VERSION 5.7 ;
BUSBITCHARS "[]" ;
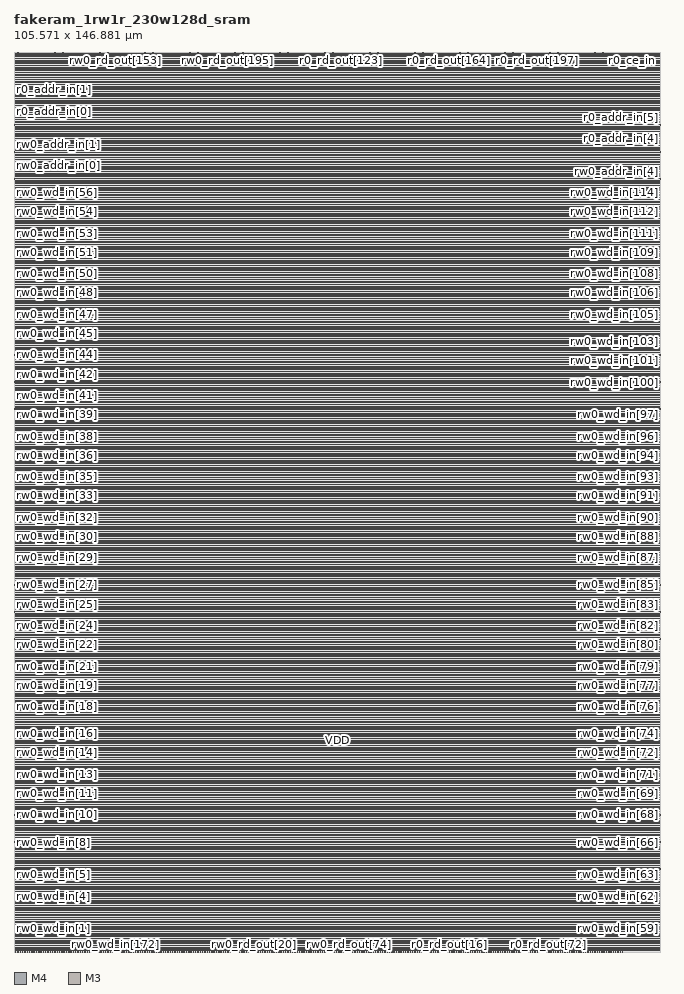
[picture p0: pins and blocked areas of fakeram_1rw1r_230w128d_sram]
MACRO fakeram_1rw1r_230w128d_sram
  FOREIGN fakeram_1rw1r_230w128d_sram 0 0 ;
  SYMMETRY X Y R90 ;
  SIZE 105.571 BY 146.881 ;
  CLASS BLOCK ;
  PIN rw0_wd_in[0]
    DIRECTION INPUT ;
    USE SIGNAL ;
    SHAPE ABUTMENT ;
    PORT
      LAYER M4 ;
      RECT 0.000 0.276 0.072 0.300 ;
    END
  END rw0_wd_in[0]
  PIN rw0_wd_in[1]
    DIRECTION INPUT ;
    USE SIGNAL ;
    SHAPE ABUTMENT ;
    PORT
      LAYER M4 ;
      RECT 0.000 2.484 0.072 2.508 ;
    END
  END rw0_wd_in[1]
  PIN rw0_wd_in[2]
    DIRECTION INPUT ;
    USE SIGNAL ;
    SHAPE ABUTMENT ;
    PORT
      LAYER M4 ;
      RECT 0.000 4.692 0.072 4.716 ;
    END
  END rw0_wd_in[2]
  PIN rw0_wd_in[3]
    DIRECTION INPUT ;
    USE SIGNAL ;
    SHAPE ABUTMENT ;
    PORT
      LAYER M4 ;
      RECT 0.000 6.900 0.072 6.924 ;
    END
  END rw0_wd_in[3]
  PIN rw0_wd_in[4]
    DIRECTION INPUT ;
    USE SIGNAL ;
    SHAPE ABUTMENT ;
    PORT
      LAYER M4 ;
      RECT 0.000 9.108 0.072 9.132 ;
    END
  END rw0_wd_in[4]
  PIN rw0_wd_in[5]
    DIRECTION INPUT ;
    USE SIGNAL ;
    SHAPE ABUTMENT ;
    PORT
      LAYER M4 ;
      RECT 0.000 11.316 0.072 11.340 ;
    END
  END rw0_wd_in[5]
  PIN rw0_wd_in[6]
    DIRECTION INPUT ;
    USE SIGNAL ;
    SHAPE ABUTMENT ;
    PORT
      LAYER M4 ;
      RECT 0.000 13.524 0.072 13.548 ;
    END
  END rw0_wd_in[6]
  PIN rw0_wd_in[7]
    DIRECTION INPUT ;
    USE SIGNAL ;
    SHAPE ABUTMENT ;
    PORT
      LAYER M4 ;
      RECT 0.000 15.732 0.072 15.756 ;
    END
  END rw0_wd_in[7]
  PIN rw0_wd_in[8]
    DIRECTION INPUT ;
    USE SIGNAL ;
    SHAPE ABUTMENT ;
    PORT
      LAYER M4 ;
      RECT 0.000 17.940 0.072 17.964 ;
    END
  END rw0_wd_in[8]
  PIN rw0_wd_in[9]
    DIRECTION INPUT ;
    USE SIGNAL ;
    SHAPE ABUTMENT ;
    PORT
      LAYER M4 ;
      RECT 0.000 20.148 0.072 20.172 ;
    END
  END rw0_wd_in[9]
  PIN rw0_wd_in[10]
    DIRECTION INPUT ;
    USE SIGNAL ;
    SHAPE ABUTMENT ;
    PORT
      LAYER M4 ;
      RECT 0.000 22.356 0.072 22.380 ;
    END
  END rw0_wd_in[10]
  PIN rw0_wd_in[11]
    DIRECTION INPUT ;
    USE SIGNAL ;
    SHAPE ABUTMENT ;
    PORT
      LAYER M4 ;
      RECT 0.000 24.564 0.072 24.588 ;
    END
  END rw0_wd_in[11]
  PIN rw0_wd_in[12]
    DIRECTION INPUT ;
    USE SIGNAL ;
    SHAPE ABUTMENT ;
    PORT
      LAYER M4 ;
      RECT 0.000 26.772 0.072 26.796 ;
    END
  END rw0_wd_in[12]
  PIN rw0_wd_in[13]
    DIRECTION INPUT ;
    USE SIGNAL ;
    SHAPE ABUTMENT ;
    PORT
      LAYER M4 ;
      RECT 0.000 28.980 0.072 29.004 ;
    END
  END rw0_wd_in[13]
  PIN rw0_wd_in[14]
    DIRECTION INPUT ;
    USE SIGNAL ;
    SHAPE ABUTMENT ;
    PORT
      LAYER M4 ;
      RECT 0.000 31.188 0.072 31.212 ;
    END
  END rw0_wd_in[14]
  PIN rw0_wd_in[15]
    DIRECTION INPUT ;
    USE SIGNAL ;
    SHAPE ABUTMENT ;
    PORT
      LAYER M4 ;
      RECT 0.000 33.396 0.072 33.420 ;
    END
  END rw0_wd_in[15]
  PIN rw0_wd_in[16]
    DIRECTION INPUT ;
    USE SIGNAL ;
    SHAPE ABUTMENT ;
    PORT
      LAYER M4 ;
      RECT 0.000 35.604 0.072 35.628 ;
    END
  END rw0_wd_in[16]
  PIN rw0_wd_in[17]
    DIRECTION INPUT ;
    USE SIGNAL ;
    SHAPE ABUTMENT ;
    PORT
      LAYER M4 ;
      RECT 0.000 37.812 0.072 37.836 ;
    END
  END rw0_wd_in[17]
  PIN rw0_wd_in[18]
    DIRECTION INPUT ;
    USE SIGNAL ;
    SHAPE ABUTMENT ;
    PORT
      LAYER M4 ;
      RECT 0.000 40.020 0.072 40.044 ;
    END
  END rw0_wd_in[18]
  PIN rw0_wd_in[19]
    DIRECTION INPUT ;
    USE SIGNAL ;
    SHAPE ABUTMENT ;
    PORT
      LAYER M4 ;
      RECT 0.000 42.228 0.072 42.252 ;
    END
  END rw0_wd_in[19]
  PIN rw0_wd_in[20]
    DIRECTION INPUT ;
    USE SIGNAL ;
    SHAPE ABUTMENT ;
    PORT
      LAYER M4 ;
      RECT 0.000 44.436 0.072 44.460 ;
    END
  END rw0_wd_in[20]
  PIN rw0_wd_in[21]
    DIRECTION INPUT ;
    USE SIGNAL ;
    SHAPE ABUTMENT ;
    PORT
      LAYER M4 ;
      RECT 0.000 46.644 0.072 46.668 ;
    END
  END rw0_wd_in[21]
  PIN rw0_wd_in[22]
    DIRECTION INPUT ;
    USE SIGNAL ;
    SHAPE ABUTMENT ;
    PORT
      LAYER M4 ;
      RECT 0.000 48.852 0.072 48.876 ;
    END
  END rw0_wd_in[22]
  PIN rw0_wd_in[23]
    DIRECTION INPUT ;
    USE SIGNAL ;
    SHAPE ABUTMENT ;
    PORT
      LAYER M4 ;
      RECT 0.000 51.060 0.072 51.084 ;
    END
  END rw0_wd_in[23]
  PIN rw0_wd_in[24]
    DIRECTION INPUT ;
    USE SIGNAL ;
    SHAPE ABUTMENT ;
    PORT
      LAYER M4 ;
      RECT 0.000 53.268 0.072 53.292 ;
    END
  END rw0_wd_in[24]
  PIN rw0_wd_in[25]
    DIRECTION INPUT ;
    USE SIGNAL ;
    SHAPE ABUTMENT ;
    PORT
      LAYER M4 ;
      RECT 0.000 55.476 0.072 55.500 ;
    END
  END rw0_wd_in[25]
  PIN rw0_wd_in[26]
    DIRECTION INPUT ;
    USE SIGNAL ;
    SHAPE ABUTMENT ;
    PORT
      LAYER M4 ;
      RECT 0.000 57.684 0.072 57.708 ;
    END
  END rw0_wd_in[26]
  PIN rw0_wd_in[27]
    DIRECTION INPUT ;
    USE SIGNAL ;
    SHAPE ABUTMENT ;
    PORT
      LAYER M4 ;
      RECT 0.000 59.892 0.072 59.916 ;
    END
  END rw0_wd_in[27]
  PIN rw0_wd_in[28]
    DIRECTION INPUT ;
    USE SIGNAL ;
    SHAPE ABUTMENT ;
    PORT
      LAYER M4 ;
      RECT 0.000 62.100 0.072 62.124 ;
    END
  END rw0_wd_in[28]
  PIN rw0_wd_in[29]
    DIRECTION INPUT ;
    USE SIGNAL ;
    SHAPE ABUTMENT ;
    PORT
      LAYER M4 ;
      RECT 0.000 64.308 0.072 64.332 ;
    END
  END rw0_wd_in[29]
  PIN rw0_wd_in[30]
    DIRECTION INPUT ;
    USE SIGNAL ;
    SHAPE ABUTMENT ;
    PORT
      LAYER M4 ;
      RECT 0.000 66.516 0.072 66.540 ;
    END
  END rw0_wd_in[30]
  PIN rw0_wd_in[31]
    DIRECTION INPUT ;
    USE SIGNAL ;
    SHAPE ABUTMENT ;
    PORT
      LAYER M4 ;
      RECT 0.000 68.724 0.072 68.748 ;
    END
  END rw0_wd_in[31]
  PIN rw0_wd_in[32]
    DIRECTION INPUT ;
    USE SIGNAL ;
    SHAPE ABUTMENT ;
    PORT
      LAYER M4 ;
      RECT 0.000 70.932 0.072 70.956 ;
    END
  END rw0_wd_in[32]
  PIN rw0_wd_in[33]
    DIRECTION INPUT ;
    USE SIGNAL ;
    SHAPE ABUTMENT ;
    PORT
      LAYER M4 ;
      RECT 0.000 73.140 0.072 73.164 ;
    END
  END rw0_wd_in[33]
  PIN rw0_wd_in[34]
    DIRECTION INPUT ;
    USE SIGNAL ;
    SHAPE ABUTMENT ;
    PORT
      LAYER M4 ;
      RECT 0.000 75.348 0.072 75.372 ;
    END
  END rw0_wd_in[34]
  PIN rw0_wd_in[35]
    DIRECTION INPUT ;
    USE SIGNAL ;
    SHAPE ABUTMENT ;
    PORT
      LAYER M4 ;
      RECT 0.000 77.556 0.072 77.580 ;
    END
  END rw0_wd_in[35]
  PIN rw0_wd_in[36]
    DIRECTION INPUT ;
    USE SIGNAL ;
    SHAPE ABUTMENT ;
    PORT
      LAYER M4 ;
      RECT 0.000 79.764 0.072 79.788 ;
    END
  END rw0_wd_in[36]
  PIN rw0_wd_in[37]
    DIRECTION INPUT ;
    USE SIGNAL ;
    SHAPE ABUTMENT ;
    PORT
      LAYER M4 ;
      RECT 0.000 81.972 0.072 81.996 ;
    END
  END rw0_wd_in[37]
  PIN rw0_wd_in[38]
    DIRECTION INPUT ;
    USE SIGNAL ;
    SHAPE ABUTMENT ;
    PORT
      LAYER M4 ;
      RECT 0.000 84.180 0.072 84.204 ;
    END
  END rw0_wd_in[38]
  PIN rw0_wd_in[39]
    DIRECTION INPUT ;
    USE SIGNAL ;
    SHAPE ABUTMENT ;
    PORT
      LAYER M4 ;
      RECT 0.000 86.388 0.072 86.412 ;
    END
  END rw0_wd_in[39]
  PIN rw0_wd_in[40]
    DIRECTION INPUT ;
    USE SIGNAL ;
    SHAPE ABUTMENT ;
    PORT
      LAYER M4 ;
      RECT 0.000 88.596 0.072 88.620 ;
    END
  END rw0_wd_in[40]
  PIN rw0_wd_in[41]
    DIRECTION INPUT ;
    USE SIGNAL ;
    SHAPE ABUTMENT ;
    PORT
      LAYER M4 ;
      RECT 0.000 90.804 0.072 90.828 ;
    END
  END rw0_wd_in[41]
  PIN rw0_wd_in[42]
    DIRECTION INPUT ;
    USE SIGNAL ;
    SHAPE ABUTMENT ;
    PORT
      LAYER M4 ;
      RECT 0.000 93.012 0.072 93.036 ;
    END
  END rw0_wd_in[42]
  PIN rw0_wd_in[43]
    DIRECTION INPUT ;
    USE SIGNAL ;
    SHAPE ABUTMENT ;
    PORT
      LAYER M4 ;
      RECT 0.000 95.220 0.072 95.244 ;
    END
  END rw0_wd_in[43]
  PIN rw0_wd_in[44]
    DIRECTION INPUT ;
    USE SIGNAL ;
    SHAPE ABUTMENT ;
    PORT
      LAYER M4 ;
      RECT 0.000 97.428 0.072 97.452 ;
    END
  END rw0_wd_in[44]
  PIN rw0_wd_in[45]
    DIRECTION INPUT ;
    USE SIGNAL ;
    SHAPE ABUTMENT ;
    PORT
      LAYER M4 ;
      RECT 0.000 99.636 0.072 99.660 ;
    END
  END rw0_wd_in[45]
  PIN rw0_wd_in[46]
    DIRECTION INPUT ;
    USE SIGNAL ;
    SHAPE ABUTMENT ;
    PORT
      LAYER M4 ;
      RECT 0.000 101.844 0.072 101.868 ;
    END
  END rw0_wd_in[46]
  PIN rw0_wd_in[47]
    DIRECTION INPUT ;
    USE SIGNAL ;
    SHAPE ABUTMENT ;
    PORT
      LAYER M4 ;
      RECT 0.000 104.052 0.072 104.076 ;
    END
  END rw0_wd_in[47]
  PIN rw0_wd_in[48]
    DIRECTION INPUT ;
    USE SIGNAL ;
    SHAPE ABUTMENT ;
    PORT
      LAYER M4 ;
      RECT 0.000 106.260 0.072 106.284 ;
    END
  END rw0_wd_in[48]
  PIN rw0_wd_in[49]
    DIRECTION INPUT ;
    USE SIGNAL ;
    SHAPE ABUTMENT ;
    PORT
      LAYER M4 ;
      RECT 0.000 108.468 0.072 108.492 ;
    END
  END rw0_wd_in[49]
  PIN rw0_wd_in[50]
    DIRECTION INPUT ;
    USE SIGNAL ;
    SHAPE ABUTMENT ;
    PORT
      LAYER M4 ;
      RECT 0.000 110.676 0.072 110.700 ;
    END
  END rw0_wd_in[50]
  PIN rw0_wd_in[51]
    DIRECTION INPUT ;
    USE SIGNAL ;
    SHAPE ABUTMENT ;
    PORT
      LAYER M4 ;
      RECT 0.000 112.884 0.072 112.908 ;
    END
  END rw0_wd_in[51]
  PIN rw0_wd_in[52]
    DIRECTION INPUT ;
    USE SIGNAL ;
    SHAPE ABUTMENT ;
    PORT
      LAYER M4 ;
      RECT 0.000 115.092 0.072 115.116 ;
    END
  END rw0_wd_in[52]
  PIN rw0_wd_in[53]
    DIRECTION INPUT ;
    USE SIGNAL ;
    SHAPE ABUTMENT ;
    PORT
      LAYER M4 ;
      RECT 0.000 117.300 0.072 117.324 ;
    END
  END rw0_wd_in[53]
  PIN rw0_wd_in[54]
    DIRECTION INPUT ;
    USE SIGNAL ;
    SHAPE ABUTMENT ;
    PORT
      LAYER M4 ;
      RECT 0.000 119.508 0.072 119.532 ;
    END
  END rw0_wd_in[54]
  PIN rw0_wd_in[55]
    DIRECTION INPUT ;
    USE SIGNAL ;
    SHAPE ABUTMENT ;
    PORT
      LAYER M4 ;
      RECT 0.000 121.716 0.072 121.740 ;
    END
  END rw0_wd_in[55]
  PIN rw0_wd_in[56]
    DIRECTION INPUT ;
    USE SIGNAL ;
    SHAPE ABUTMENT ;
    PORT
      LAYER M4 ;
      RECT 0.000 123.924 0.072 123.948 ;
    END
  END rw0_wd_in[56]
  PIN rw0_wd_in[57]
    DIRECTION INPUT ;
    USE SIGNAL ;
    SHAPE ABUTMENT ;
    PORT
      LAYER M4 ;
      RECT 0.000 126.132 0.072 126.156 ;
    END
  END rw0_wd_in[57]
  PIN rw0_wd_in[58]
    DIRECTION INPUT ;
    USE SIGNAL ;
    SHAPE ABUTMENT ;
    PORT
      LAYER M4 ;
      RECT 105.499 0.276 105.571 0.300 ;
    END
  END rw0_wd_in[58]
  PIN rw0_wd_in[59]
    DIRECTION INPUT ;
    USE SIGNAL ;
    SHAPE ABUTMENT ;
    PORT
      LAYER M4 ;
      RECT 105.499 2.484 105.571 2.508 ;
    END
  END rw0_wd_in[59]
  PIN rw0_wd_in[60]
    DIRECTION INPUT ;
    USE SIGNAL ;
    SHAPE ABUTMENT ;
    PORT
      LAYER M4 ;
      RECT 105.499 4.692 105.571 4.716 ;
    END
  END rw0_wd_in[60]
  PIN rw0_wd_in[61]
    DIRECTION INPUT ;
    USE SIGNAL ;
    SHAPE ABUTMENT ;
    PORT
      LAYER M4 ;
      RECT 105.499 6.900 105.571 6.924 ;
    END
  END rw0_wd_in[61]
  PIN rw0_wd_in[62]
    DIRECTION INPUT ;
    USE SIGNAL ;
    SHAPE ABUTMENT ;
    PORT
      LAYER M4 ;
      RECT 105.499 9.108 105.571 9.132 ;
    END
  END rw0_wd_in[62]
  PIN rw0_wd_in[63]
    DIRECTION INPUT ;
    USE SIGNAL ;
    SHAPE ABUTMENT ;
    PORT
      LAYER M4 ;
      RECT 105.499 11.316 105.571 11.340 ;
    END
  END rw0_wd_in[63]
  PIN rw0_wd_in[64]
    DIRECTION INPUT ;
    USE SIGNAL ;
    SHAPE ABUTMENT ;
    PORT
      LAYER M4 ;
      RECT 105.499 13.524 105.571 13.548 ;
    END
  END rw0_wd_in[64]
  PIN rw0_wd_in[65]
    DIRECTION INPUT ;
    USE SIGNAL ;
    SHAPE ABUTMENT ;
    PORT
      LAYER M4 ;
      RECT 105.499 15.732 105.571 15.756 ;
    END
  END rw0_wd_in[65]
  PIN rw0_wd_in[66]
    DIRECTION INPUT ;
    USE SIGNAL ;
    SHAPE ABUTMENT ;
    PORT
      LAYER M4 ;
      RECT 105.499 17.940 105.571 17.964 ;
    END
  END rw0_wd_in[66]
  PIN rw0_wd_in[67]
    DIRECTION INPUT ;
    USE SIGNAL ;
    SHAPE ABUTMENT ;
    PORT
      LAYER M4 ;
      RECT 105.499 20.148 105.571 20.172 ;
    END
  END rw0_wd_in[67]
  PIN rw0_wd_in[68]
    DIRECTION INPUT ;
    USE SIGNAL ;
    SHAPE ABUTMENT ;
    PORT
      LAYER M4 ;
      RECT 105.499 22.356 105.571 22.380 ;
    END
  END rw0_wd_in[68]
  PIN rw0_wd_in[69]
    DIRECTION INPUT ;
    USE SIGNAL ;
    SHAPE ABUTMENT ;
    PORT
      LAYER M4 ;
      RECT 105.499 24.564 105.571 24.588 ;
    END
  END rw0_wd_in[69]
  PIN rw0_wd_in[70]
    DIRECTION INPUT ;
    USE SIGNAL ;
    SHAPE ABUTMENT ;
    PORT
      LAYER M4 ;
      RECT 105.499 26.772 105.571 26.796 ;
    END
  END rw0_wd_in[70]
  PIN rw0_wd_in[71]
    DIRECTION INPUT ;
    USE SIGNAL ;
    SHAPE ABUTMENT ;
    PORT
      LAYER M4 ;
      RECT 105.499 28.980 105.571 29.004 ;
    END
  END rw0_wd_in[71]
  PIN rw0_wd_in[72]
    DIRECTION INPUT ;
    USE SIGNAL ;
    SHAPE ABUTMENT ;
    PORT
      LAYER M4 ;
      RECT 105.499 31.188 105.571 31.212 ;
    END
  END rw0_wd_in[72]
  PIN rw0_wd_in[73]
    DIRECTION INPUT ;
    USE SIGNAL ;
    SHAPE ABUTMENT ;
    PORT
      LAYER M4 ;
      RECT 105.499 33.396 105.571 33.420 ;
    END
  END rw0_wd_in[73]
  PIN rw0_wd_in[74]
    DIRECTION INPUT ;
    USE SIGNAL ;
    SHAPE ABUTMENT ;
    PORT
      LAYER M4 ;
      RECT 105.499 35.604 105.571 35.628 ;
    END
  END rw0_wd_in[74]
  PIN rw0_wd_in[75]
    DIRECTION INPUT ;
    USE SIGNAL ;
    SHAPE ABUTMENT ;
    PORT
      LAYER M4 ;
      RECT 105.499 37.812 105.571 37.836 ;
    END
  END rw0_wd_in[75]
  PIN rw0_wd_in[76]
    DIRECTION INPUT ;
    USE SIGNAL ;
    SHAPE ABUTMENT ;
    PORT
      LAYER M4 ;
      RECT 105.499 40.020 105.571 40.044 ;
    END
  END rw0_wd_in[76]
  PIN rw0_wd_in[77]
    DIRECTION INPUT ;
    USE SIGNAL ;
    SHAPE ABUTMENT ;
    PORT
      LAYER M4 ;
      RECT 105.499 42.228 105.571 42.252 ;
    END
  END rw0_wd_in[77]
  PIN rw0_wd_in[78]
    DIRECTION INPUT ;
    USE SIGNAL ;
    SHAPE ABUTMENT ;
    PORT
      LAYER M4 ;
      RECT 105.499 44.436 105.571 44.460 ;
    END
  END rw0_wd_in[78]
  PIN rw0_wd_in[79]
    DIRECTION INPUT ;
    USE SIGNAL ;
    SHAPE ABUTMENT ;
    PORT
      LAYER M4 ;
      RECT 105.499 46.644 105.571 46.668 ;
    END
  END rw0_wd_in[79]
  PIN rw0_wd_in[80]
    DIRECTION INPUT ;
    USE SIGNAL ;
    SHAPE ABUTMENT ;
    PORT
      LAYER M4 ;
      RECT 105.499 48.852 105.571 48.876 ;
    END
  END rw0_wd_in[80]
  PIN rw0_wd_in[81]
    DIRECTION INPUT ;
    USE SIGNAL ;
    SHAPE ABUTMENT ;
    PORT
      LAYER M4 ;
      RECT 105.499 51.060 105.571 51.084 ;
    END
  END rw0_wd_in[81]
  PIN rw0_wd_in[82]
    DIRECTION INPUT ;
    USE SIGNAL ;
    SHAPE ABUTMENT ;
    PORT
      LAYER M4 ;
      RECT 105.499 53.268 105.571 53.292 ;
    END
  END rw0_wd_in[82]
  PIN rw0_wd_in[83]
    DIRECTION INPUT ;
    USE SIGNAL ;
    SHAPE ABUTMENT ;
    PORT
      LAYER M4 ;
      RECT 105.499 55.476 105.571 55.500 ;
    END
  END rw0_wd_in[83]
  PIN rw0_wd_in[84]
    DIRECTION INPUT ;
    USE SIGNAL ;
    SHAPE ABUTMENT ;
    PORT
      LAYER M4 ;
      RECT 105.499 57.684 105.571 57.708 ;
    END
  END rw0_wd_in[84]
  PIN rw0_wd_in[85]
    DIRECTION INPUT ;
    USE SIGNAL ;
    SHAPE ABUTMENT ;
    PORT
      LAYER M4 ;
      RECT 105.499 59.892 105.571 59.916 ;
    END
  END rw0_wd_in[85]
  PIN rw0_wd_in[86]
    DIRECTION INPUT ;
    USE SIGNAL ;
    SHAPE ABUTMENT ;
    PORT
      LAYER M4 ;
      RECT 105.499 62.100 105.571 62.124 ;
    END
  END rw0_wd_in[86]
  PIN rw0_wd_in[87]
    DIRECTION INPUT ;
    USE SIGNAL ;
    SHAPE ABUTMENT ;
    PORT
      LAYER M4 ;
      RECT 105.499 64.308 105.571 64.332 ;
    END
  END rw0_wd_in[87]
  PIN rw0_wd_in[88]
    DIRECTION INPUT ;
    USE SIGNAL ;
    SHAPE ABUTMENT ;
    PORT
      LAYER M4 ;
      RECT 105.499 66.516 105.571 66.540 ;
    END
  END rw0_wd_in[88]
  PIN rw0_wd_in[89]
    DIRECTION INPUT ;
    USE SIGNAL ;
    SHAPE ABUTMENT ;
    PORT
      LAYER M4 ;
      RECT 105.499 68.724 105.571 68.748 ;
    END
  END rw0_wd_in[89]
  PIN rw0_wd_in[90]
    DIRECTION INPUT ;
    USE SIGNAL ;
    SHAPE ABUTMENT ;
    PORT
      LAYER M4 ;
      RECT 105.499 70.932 105.571 70.956 ;
    END
  END rw0_wd_in[90]
  PIN rw0_wd_in[91]
    DIRECTION INPUT ;
    USE SIGNAL ;
    SHAPE ABUTMENT ;
    PORT
      LAYER M4 ;
      RECT 105.499 73.140 105.571 73.164 ;
    END
  END rw0_wd_in[91]
  PIN rw0_wd_in[92]
    DIRECTION INPUT ;
    USE SIGNAL ;
    SHAPE ABUTMENT ;
    PORT
      LAYER M4 ;
      RECT 105.499 75.348 105.571 75.372 ;
    END
  END rw0_wd_in[92]
  PIN rw0_wd_in[93]
    DIRECTION INPUT ;
    USE SIGNAL ;
    SHAPE ABUTMENT ;
    PORT
      LAYER M4 ;
      RECT 105.499 77.556 105.571 77.580 ;
    END
  END rw0_wd_in[93]
  PIN rw0_wd_in[94]
    DIRECTION INPUT ;
    USE SIGNAL ;
    SHAPE ABUTMENT ;
    PORT
      LAYER M4 ;
      RECT 105.499 79.764 105.571 79.788 ;
    END
  END rw0_wd_in[94]
  PIN rw0_wd_in[95]
    DIRECTION INPUT ;
    USE SIGNAL ;
    SHAPE ABUTMENT ;
    PORT
      LAYER M4 ;
      RECT 105.499 81.972 105.571 81.996 ;
    END
  END rw0_wd_in[95]
  PIN rw0_wd_in[96]
    DIRECTION INPUT ;
    USE SIGNAL ;
    SHAPE ABUTMENT ;
    PORT
      LAYER M4 ;
      RECT 105.499 84.180 105.571 84.204 ;
    END
  END rw0_wd_in[96]
  PIN rw0_wd_in[97]
    DIRECTION INPUT ;
    USE SIGNAL ;
    SHAPE ABUTMENT ;
    PORT
      LAYER M4 ;
      RECT 105.499 86.388 105.571 86.412 ;
    END
  END rw0_wd_in[97]
  PIN rw0_wd_in[98]
    DIRECTION INPUT ;
    USE SIGNAL ;
    SHAPE ABUTMENT ;
    PORT
      LAYER M4 ;
      RECT 105.499 88.596 105.571 88.620 ;
    END
  END rw0_wd_in[98]
  PIN rw0_wd_in[99]
    DIRECTION INPUT ;
    USE SIGNAL ;
    SHAPE ABUTMENT ;
    PORT
      LAYER M4 ;
      RECT 105.499 90.804 105.571 90.828 ;
    END
  END rw0_wd_in[99]
  PIN rw0_wd_in[100]
    DIRECTION INPUT ;
    USE SIGNAL ;
    SHAPE ABUTMENT ;
    PORT
      LAYER M4 ;
      RECT 105.499 93.012 105.571 93.036 ;
    END
  END rw0_wd_in[100]
  PIN rw0_wd_in[101]
    DIRECTION INPUT ;
    USE SIGNAL ;
    SHAPE ABUTMENT ;
    PORT
      LAYER M4 ;
      RECT 105.499 95.220 105.571 95.244 ;
    END
  END rw0_wd_in[101]
  PIN rw0_wd_in[102]
    DIRECTION INPUT ;
    USE SIGNAL ;
    SHAPE ABUTMENT ;
    PORT
      LAYER M4 ;
      RECT 105.499 97.428 105.571 97.452 ;
    END
  END rw0_wd_in[102]
  PIN rw0_wd_in[103]
    DIRECTION INPUT ;
    USE SIGNAL ;
    SHAPE ABUTMENT ;
    PORT
      LAYER M4 ;
      RECT 105.499 99.636 105.571 99.660 ;
    END
  END rw0_wd_in[103]
  PIN rw0_wd_in[104]
    DIRECTION INPUT ;
    USE SIGNAL ;
    SHAPE ABUTMENT ;
    PORT
      LAYER M4 ;
      RECT 105.499 101.844 105.571 101.868 ;
    END
  END rw0_wd_in[104]
  PIN rw0_wd_in[105]
    DIRECTION INPUT ;
    USE SIGNAL ;
    SHAPE ABUTMENT ;
    PORT
      LAYER M4 ;
      RECT 105.499 104.052 105.571 104.076 ;
    END
  END rw0_wd_in[105]
  PIN rw0_wd_in[106]
    DIRECTION INPUT ;
    USE SIGNAL ;
    SHAPE ABUTMENT ;
    PORT
      LAYER M4 ;
      RECT 105.499 106.260 105.571 106.284 ;
    END
  END rw0_wd_in[106]
  PIN rw0_wd_in[107]
    DIRECTION INPUT ;
    USE SIGNAL ;
    SHAPE ABUTMENT ;
    PORT
      LAYER M4 ;
      RECT 105.499 108.468 105.571 108.492 ;
    END
  END rw0_wd_in[107]
  PIN rw0_wd_in[108]
    DIRECTION INPUT ;
    USE SIGNAL ;
    SHAPE ABUTMENT ;
    PORT
      LAYER M4 ;
      RECT 105.499 110.676 105.571 110.700 ;
    END
  END rw0_wd_in[108]
  PIN rw0_wd_in[109]
    DIRECTION INPUT ;
    USE SIGNAL ;
    SHAPE ABUTMENT ;
    PORT
      LAYER M4 ;
      RECT 105.499 112.884 105.571 112.908 ;
    END
  END rw0_wd_in[109]
  PIN rw0_wd_in[110]
    DIRECTION INPUT ;
    USE SIGNAL ;
    SHAPE ABUTMENT ;
    PORT
      LAYER M4 ;
      RECT 105.499 115.092 105.571 115.116 ;
    END
  END rw0_wd_in[110]
  PIN rw0_wd_in[111]
    DIRECTION INPUT ;
    USE SIGNAL ;
    SHAPE ABUTMENT ;
    PORT
      LAYER M4 ;
      RECT 105.499 117.300 105.571 117.324 ;
    END
  END rw0_wd_in[111]
  PIN rw0_wd_in[112]
    DIRECTION INPUT ;
    USE SIGNAL ;
    SHAPE ABUTMENT ;
    PORT
      LAYER M4 ;
      RECT 105.499 119.508 105.571 119.532 ;
    END
  END rw0_wd_in[112]
  PIN rw0_wd_in[113]
    DIRECTION INPUT ;
    USE SIGNAL ;
    SHAPE ABUTMENT ;
    PORT
      LAYER M4 ;
      RECT 105.499 121.716 105.571 121.740 ;
    END
  END rw0_wd_in[113]
  PIN rw0_wd_in[114]
    DIRECTION INPUT ;
    USE SIGNAL ;
    SHAPE ABUTMENT ;
    PORT
      LAYER M4 ;
      RECT 105.499 123.924 105.571 123.948 ;
    END
  END rw0_wd_in[114]
  PIN rw0_wd_in[115]
    DIRECTION INPUT ;
    USE SIGNAL ;
    SHAPE ABUTMENT ;
    PORT
      LAYER M3 ;
      RECT 0.207 0.000 0.225 0.054 ;
    END
  END rw0_wd_in[115]
  PIN rw0_wd_in[116]
    DIRECTION INPUT ;
    USE SIGNAL ;
    SHAPE ABUTMENT ;
    PORT
      LAYER M3 ;
      RECT 0.495 0.000 0.513 0.054 ;
    END
  END rw0_wd_in[116]
  PIN rw0_wd_in[117]
    DIRECTION INPUT ;
    USE SIGNAL ;
    SHAPE ABUTMENT ;
    PORT
      LAYER M3 ;
      RECT 0.783 0.000 0.801 0.054 ;
    END
  END rw0_wd_in[117]
  PIN rw0_wd_in[118]
    DIRECTION INPUT ;
    USE SIGNAL ;
    SHAPE ABUTMENT ;
    PORT
      LAYER M3 ;
      RECT 1.071 0.000 1.089 0.054 ;
    END
  END rw0_wd_in[118]
  PIN rw0_wd_in[119]
    DIRECTION INPUT ;
    USE SIGNAL ;
    SHAPE ABUTMENT ;
    PORT
      LAYER M3 ;
      RECT 1.359 0.000 1.377 0.054 ;
    END
  END rw0_wd_in[119]
  PIN rw0_wd_in[120]
    DIRECTION INPUT ;
    USE SIGNAL ;
    SHAPE ABUTMENT ;
    PORT
      LAYER M3 ;
      RECT 1.647 0.000 1.665 0.054 ;
    END
  END rw0_wd_in[120]
  PIN rw0_wd_in[121]
    DIRECTION INPUT ;
    USE SIGNAL ;
    SHAPE ABUTMENT ;
    PORT
      LAYER M3 ;
      RECT 1.935 0.000 1.953 0.054 ;
    END
  END rw0_wd_in[121]
  PIN rw0_wd_in[122]
    DIRECTION INPUT ;
    USE SIGNAL ;
    SHAPE ABUTMENT ;
    PORT
      LAYER M3 ;
      RECT 2.223 0.000 2.241 0.054 ;
    END
  END rw0_wd_in[122]
  PIN rw0_wd_in[123]
    DIRECTION INPUT ;
    USE SIGNAL ;
    SHAPE ABUTMENT ;
    PORT
      LAYER M3 ;
      RECT 2.511 0.000 2.529 0.054 ;
    END
  END rw0_wd_in[123]
  PIN rw0_wd_in[124]
    DIRECTION INPUT ;
    USE SIGNAL ;
    SHAPE ABUTMENT ;
    PORT
      LAYER M3 ;
      RECT 2.799 0.000 2.817 0.054 ;
    END
  END rw0_wd_in[124]
  PIN rw0_wd_in[125]
    DIRECTION INPUT ;
    USE SIGNAL ;
    SHAPE ABUTMENT ;
    PORT
      LAYER M3 ;
      RECT 3.087 0.000 3.105 0.054 ;
    END
  END rw0_wd_in[125]
  PIN rw0_wd_in[126]
    DIRECTION INPUT ;
    USE SIGNAL ;
    SHAPE ABUTMENT ;
    PORT
      LAYER M3 ;
      RECT 3.375 0.000 3.393 0.054 ;
    END
  END rw0_wd_in[126]
  PIN rw0_wd_in[127]
    DIRECTION INPUT ;
    USE SIGNAL ;
    SHAPE ABUTMENT ;
    PORT
      LAYER M3 ;
      RECT 3.663 0.000 3.681 0.054 ;
    END
  END rw0_wd_in[127]
  PIN rw0_wd_in[128]
    DIRECTION INPUT ;
    USE SIGNAL ;
    SHAPE ABUTMENT ;
    PORT
      LAYER M3 ;
      RECT 3.951 0.000 3.969 0.054 ;
    END
  END rw0_wd_in[128]
  PIN rw0_wd_in[129]
    DIRECTION INPUT ;
    USE SIGNAL ;
    SHAPE ABUTMENT ;
    PORT
      LAYER M3 ;
      RECT 4.239 0.000 4.257 0.054 ;
    END
  END rw0_wd_in[129]
  PIN rw0_wd_in[130]
    DIRECTION INPUT ;
    USE SIGNAL ;
    SHAPE ABUTMENT ;
    PORT
      LAYER M3 ;
      RECT 4.527 0.000 4.545 0.054 ;
    END
  END rw0_wd_in[130]
  PIN rw0_wd_in[131]
    DIRECTION INPUT ;
    USE SIGNAL ;
    SHAPE ABUTMENT ;
    PORT
      LAYER M3 ;
      RECT 4.815 0.000 4.833 0.054 ;
    END
  END rw0_wd_in[131]
  PIN rw0_wd_in[132]
    DIRECTION INPUT ;
    USE SIGNAL ;
    SHAPE ABUTMENT ;
    PORT
      LAYER M3 ;
      RECT 5.103 0.000 5.121 0.054 ;
    END
  END rw0_wd_in[132]
  PIN rw0_wd_in[133]
    DIRECTION INPUT ;
    USE SIGNAL ;
    SHAPE ABUTMENT ;
    PORT
      LAYER M3 ;
      RECT 5.391 0.000 5.409 0.054 ;
    END
  END rw0_wd_in[133]
  PIN rw0_wd_in[134]
    DIRECTION INPUT ;
    USE SIGNAL ;
    SHAPE ABUTMENT ;
    PORT
      LAYER M3 ;
      RECT 5.679 0.000 5.697 0.054 ;
    END
  END rw0_wd_in[134]
  PIN rw0_wd_in[135]
    DIRECTION INPUT ;
    USE SIGNAL ;
    SHAPE ABUTMENT ;
    PORT
      LAYER M3 ;
      RECT 5.967 0.000 5.985 0.054 ;
    END
  END rw0_wd_in[135]
  PIN rw0_wd_in[136]
    DIRECTION INPUT ;
    USE SIGNAL ;
    SHAPE ABUTMENT ;
    PORT
      LAYER M3 ;
      RECT 6.255 0.000 6.273 0.054 ;
    END
  END rw0_wd_in[136]
  PIN rw0_wd_in[137]
    DIRECTION INPUT ;
    USE SIGNAL ;
    SHAPE ABUTMENT ;
    PORT
      LAYER M3 ;
      RECT 6.543 0.000 6.561 0.054 ;
    END
  END rw0_wd_in[137]
  PIN rw0_wd_in[138]
    DIRECTION INPUT ;
    USE SIGNAL ;
    SHAPE ABUTMENT ;
    PORT
      LAYER M3 ;
      RECT 6.831 0.000 6.849 0.054 ;
    END
  END rw0_wd_in[138]
  PIN rw0_wd_in[139]
    DIRECTION INPUT ;
    USE SIGNAL ;
    SHAPE ABUTMENT ;
    PORT
      LAYER M3 ;
      RECT 7.119 0.000 7.137 0.054 ;
    END
  END rw0_wd_in[139]
  PIN rw0_wd_in[140]
    DIRECTION INPUT ;
    USE SIGNAL ;
    SHAPE ABUTMENT ;
    PORT
      LAYER M3 ;
      RECT 7.407 0.000 7.425 0.054 ;
    END
  END rw0_wd_in[140]
  PIN rw0_wd_in[141]
    DIRECTION INPUT ;
    USE SIGNAL ;
    SHAPE ABUTMENT ;
    PORT
      LAYER M3 ;
      RECT 7.695 0.000 7.713 0.054 ;
    END
  END rw0_wd_in[141]
  PIN rw0_wd_in[142]
    DIRECTION INPUT ;
    USE SIGNAL ;
    SHAPE ABUTMENT ;
    PORT
      LAYER M3 ;
      RECT 7.983 0.000 8.001 0.054 ;
    END
  END rw0_wd_in[142]
  PIN rw0_wd_in[143]
    DIRECTION INPUT ;
    USE SIGNAL ;
    SHAPE ABUTMENT ;
    PORT
      LAYER M3 ;
      RECT 8.271 0.000 8.289 0.054 ;
    END
  END rw0_wd_in[143]
  PIN rw0_wd_in[144]
    DIRECTION INPUT ;
    USE SIGNAL ;
    SHAPE ABUTMENT ;
    PORT
      LAYER M3 ;
      RECT 8.559 0.000 8.577 0.054 ;
    END
  END rw0_wd_in[144]
  PIN rw0_wd_in[145]
    DIRECTION INPUT ;
    USE SIGNAL ;
    SHAPE ABUTMENT ;
    PORT
      LAYER M3 ;
      RECT 8.847 0.000 8.865 0.054 ;
    END
  END rw0_wd_in[145]
  PIN rw0_wd_in[146]
    DIRECTION INPUT ;
    USE SIGNAL ;
    SHAPE ABUTMENT ;
    PORT
      LAYER M3 ;
      RECT 9.135 0.000 9.153 0.054 ;
    END
  END rw0_wd_in[146]
  PIN rw0_wd_in[147]
    DIRECTION INPUT ;
    USE SIGNAL ;
    SHAPE ABUTMENT ;
    PORT
      LAYER M3 ;
      RECT 9.423 0.000 9.441 0.054 ;
    END
  END rw0_wd_in[147]
  PIN rw0_wd_in[148]
    DIRECTION INPUT ;
    USE SIGNAL ;
    SHAPE ABUTMENT ;
    PORT
      LAYER M3 ;
      RECT 9.711 0.000 9.729 0.054 ;
    END
  END rw0_wd_in[148]
  PIN rw0_wd_in[149]
    DIRECTION INPUT ;
    USE SIGNAL ;
    SHAPE ABUTMENT ;
    PORT
      LAYER M3 ;
      RECT 9.999 0.000 10.017 0.054 ;
    END
  END rw0_wd_in[149]
  PIN rw0_wd_in[150]
    DIRECTION INPUT ;
    USE SIGNAL ;
    SHAPE ABUTMENT ;
    PORT
      LAYER M3 ;
      RECT 10.287 0.000 10.305 0.054 ;
    END
  END rw0_wd_in[150]
  PIN rw0_wd_in[151]
    DIRECTION INPUT ;
    USE SIGNAL ;
    SHAPE ABUTMENT ;
    PORT
      LAYER M3 ;
      RECT 10.575 0.000 10.593 0.054 ;
    END
  END rw0_wd_in[151]
  PIN rw0_wd_in[152]
    DIRECTION INPUT ;
    USE SIGNAL ;
    SHAPE ABUTMENT ;
    PORT
      LAYER M3 ;
      RECT 10.863 0.000 10.881 0.054 ;
    END
  END rw0_wd_in[152]
  PIN rw0_wd_in[153]
    DIRECTION INPUT ;
    USE SIGNAL ;
    SHAPE ABUTMENT ;
    PORT
      LAYER M3 ;
      RECT 11.151 0.000 11.169 0.054 ;
    END
  END rw0_wd_in[153]
  PIN rw0_wd_in[154]
    DIRECTION INPUT ;
    USE SIGNAL ;
    SHAPE ABUTMENT ;
    PORT
      LAYER M3 ;
      RECT 11.439 0.000 11.457 0.054 ;
    END
  END rw0_wd_in[154]
  PIN rw0_wd_in[155]
    DIRECTION INPUT ;
    USE SIGNAL ;
    SHAPE ABUTMENT ;
    PORT
      LAYER M3 ;
      RECT 11.727 0.000 11.745 0.054 ;
    END
  END rw0_wd_in[155]
  PIN rw0_wd_in[156]
    DIRECTION INPUT ;
    USE SIGNAL ;
    SHAPE ABUTMENT ;
    PORT
      LAYER M3 ;
      RECT 12.015 0.000 12.033 0.054 ;
    END
  END rw0_wd_in[156]
  PIN rw0_wd_in[157]
    DIRECTION INPUT ;
    USE SIGNAL ;
    SHAPE ABUTMENT ;
    PORT
      LAYER M3 ;
      RECT 12.303 0.000 12.321 0.054 ;
    END
  END rw0_wd_in[157]
  PIN rw0_wd_in[158]
    DIRECTION INPUT ;
    USE SIGNAL ;
    SHAPE ABUTMENT ;
    PORT
      LAYER M3 ;
      RECT 12.591 0.000 12.609 0.054 ;
    END
  END rw0_wd_in[158]
  PIN rw0_wd_in[159]
    DIRECTION INPUT ;
    USE SIGNAL ;
    SHAPE ABUTMENT ;
    PORT
      LAYER M3 ;
      RECT 12.879 0.000 12.897 0.054 ;
    END
  END rw0_wd_in[159]
  PIN rw0_wd_in[160]
    DIRECTION INPUT ;
    USE SIGNAL ;
    SHAPE ABUTMENT ;
    PORT
      LAYER M3 ;
      RECT 13.167 0.000 13.185 0.054 ;
    END
  END rw0_wd_in[160]
  PIN rw0_wd_in[161]
    DIRECTION INPUT ;
    USE SIGNAL ;
    SHAPE ABUTMENT ;
    PORT
      LAYER M3 ;
      RECT 13.455 0.000 13.473 0.054 ;
    END
  END rw0_wd_in[161]
  PIN rw0_wd_in[162]
    DIRECTION INPUT ;
    USE SIGNAL ;
    SHAPE ABUTMENT ;
    PORT
      LAYER M3 ;
      RECT 13.743 0.000 13.761 0.054 ;
    END
  END rw0_wd_in[162]
  PIN rw0_wd_in[163]
    DIRECTION INPUT ;
    USE SIGNAL ;
    SHAPE ABUTMENT ;
    PORT
      LAYER M3 ;
      RECT 14.031 0.000 14.049 0.054 ;
    END
  END rw0_wd_in[163]
  PIN rw0_wd_in[164]
    DIRECTION INPUT ;
    USE SIGNAL ;
    SHAPE ABUTMENT ;
    PORT
      LAYER M3 ;
      RECT 14.319 0.000 14.337 0.054 ;
    END
  END rw0_wd_in[164]
  PIN rw0_wd_in[165]
    DIRECTION INPUT ;
    USE SIGNAL ;
    SHAPE ABUTMENT ;
    PORT
      LAYER M3 ;
      RECT 14.607 0.000 14.625 0.054 ;
    END
  END rw0_wd_in[165]
  PIN rw0_wd_in[166]
    DIRECTION INPUT ;
    USE SIGNAL ;
    SHAPE ABUTMENT ;
    PORT
      LAYER M3 ;
      RECT 14.895 0.000 14.913 0.054 ;
    END
  END rw0_wd_in[166]
  PIN rw0_wd_in[167]
    DIRECTION INPUT ;
    USE SIGNAL ;
    SHAPE ABUTMENT ;
    PORT
      LAYER M3 ;
      RECT 15.183 0.000 15.201 0.054 ;
    END
  END rw0_wd_in[167]
  PIN rw0_wd_in[168]
    DIRECTION INPUT ;
    USE SIGNAL ;
    SHAPE ABUTMENT ;
    PORT
      LAYER M3 ;
      RECT 15.471 0.000 15.489 0.054 ;
    END
  END rw0_wd_in[168]
  PIN rw0_wd_in[169]
    DIRECTION INPUT ;
    USE SIGNAL ;
    SHAPE ABUTMENT ;
    PORT
      LAYER M3 ;
      RECT 15.759 0.000 15.777 0.054 ;
    END
  END rw0_wd_in[169]
  PIN rw0_wd_in[170]
    DIRECTION INPUT ;
    USE SIGNAL ;
    SHAPE ABUTMENT ;
    PORT
      LAYER M3 ;
      RECT 16.047 0.000 16.065 0.054 ;
    END
  END rw0_wd_in[170]
  PIN rw0_wd_in[171]
    DIRECTION INPUT ;
    USE SIGNAL ;
    SHAPE ABUTMENT ;
    PORT
      LAYER M3 ;
      RECT 16.335 0.000 16.353 0.054 ;
    END
  END rw0_wd_in[171]
  PIN rw0_wd_in[172]
    DIRECTION INPUT ;
    USE SIGNAL ;
    SHAPE ABUTMENT ;
    PORT
      LAYER M3 ;
      RECT 16.623 0.000 16.641 0.054 ;
    END
  END rw0_wd_in[172]
  PIN rw0_wd_in[173]
    DIRECTION INPUT ;
    USE SIGNAL ;
    SHAPE ABUTMENT ;
    PORT
      LAYER M3 ;
      RECT 16.911 0.000 16.929 0.054 ;
    END
  END rw0_wd_in[173]
  PIN rw0_wd_in[174]
    DIRECTION INPUT ;
    USE SIGNAL ;
    SHAPE ABUTMENT ;
    PORT
      LAYER M3 ;
      RECT 17.199 0.000 17.217 0.054 ;
    END
  END rw0_wd_in[174]
  PIN rw0_wd_in[175]
    DIRECTION INPUT ;
    USE SIGNAL ;
    SHAPE ABUTMENT ;
    PORT
      LAYER M3 ;
      RECT 17.487 0.000 17.505 0.054 ;
    END
  END rw0_wd_in[175]
  PIN rw0_wd_in[176]
    DIRECTION INPUT ;
    USE SIGNAL ;
    SHAPE ABUTMENT ;
    PORT
      LAYER M3 ;
      RECT 17.775 0.000 17.793 0.054 ;
    END
  END rw0_wd_in[176]
  PIN rw0_wd_in[177]
    DIRECTION INPUT ;
    USE SIGNAL ;
    SHAPE ABUTMENT ;
    PORT
      LAYER M3 ;
      RECT 18.063 0.000 18.081 0.054 ;
    END
  END rw0_wd_in[177]
  PIN rw0_wd_in[178]
    DIRECTION INPUT ;
    USE SIGNAL ;
    SHAPE ABUTMENT ;
    PORT
      LAYER M3 ;
      RECT 18.351 0.000 18.369 0.054 ;
    END
  END rw0_wd_in[178]
  PIN rw0_wd_in[179]
    DIRECTION INPUT ;
    USE SIGNAL ;
    SHAPE ABUTMENT ;
    PORT
      LAYER M3 ;
      RECT 18.639 0.000 18.657 0.054 ;
    END
  END rw0_wd_in[179]
  PIN rw0_wd_in[180]
    DIRECTION INPUT ;
    USE SIGNAL ;
    SHAPE ABUTMENT ;
    PORT
      LAYER M3 ;
      RECT 18.927 0.000 18.945 0.054 ;
    END
  END rw0_wd_in[180]
  PIN rw0_wd_in[181]
    DIRECTION INPUT ;
    USE SIGNAL ;
    SHAPE ABUTMENT ;
    PORT
      LAYER M3 ;
      RECT 19.215 0.000 19.233 0.054 ;
    END
  END rw0_wd_in[181]
  PIN rw0_wd_in[182]
    DIRECTION INPUT ;
    USE SIGNAL ;
    SHAPE ABUTMENT ;
    PORT
      LAYER M3 ;
      RECT 19.503 0.000 19.521 0.054 ;
    END
  END rw0_wd_in[182]
  PIN rw0_wd_in[183]
    DIRECTION INPUT ;
    USE SIGNAL ;
    SHAPE ABUTMENT ;
    PORT
      LAYER M3 ;
      RECT 19.791 0.000 19.809 0.054 ;
    END
  END rw0_wd_in[183]
  PIN rw0_wd_in[184]
    DIRECTION INPUT ;
    USE SIGNAL ;
    SHAPE ABUTMENT ;
    PORT
      LAYER M3 ;
      RECT 20.079 0.000 20.097 0.054 ;
    END
  END rw0_wd_in[184]
  PIN rw0_wd_in[185]
    DIRECTION INPUT ;
    USE SIGNAL ;
    SHAPE ABUTMENT ;
    PORT
      LAYER M3 ;
      RECT 20.367 0.000 20.385 0.054 ;
    END
  END rw0_wd_in[185]
  PIN rw0_wd_in[186]
    DIRECTION INPUT ;
    USE SIGNAL ;
    SHAPE ABUTMENT ;
    PORT
      LAYER M3 ;
      RECT 20.655 0.000 20.673 0.054 ;
    END
  END rw0_wd_in[186]
  PIN rw0_wd_in[187]
    DIRECTION INPUT ;
    USE SIGNAL ;
    SHAPE ABUTMENT ;
    PORT
      LAYER M3 ;
      RECT 20.943 0.000 20.961 0.054 ;
    END
  END rw0_wd_in[187]
  PIN rw0_wd_in[188]
    DIRECTION INPUT ;
    USE SIGNAL ;
    SHAPE ABUTMENT ;
    PORT
      LAYER M3 ;
      RECT 21.231 0.000 21.249 0.054 ;
    END
  END rw0_wd_in[188]
  PIN rw0_wd_in[189]
    DIRECTION INPUT ;
    USE SIGNAL ;
    SHAPE ABUTMENT ;
    PORT
      LAYER M3 ;
      RECT 21.519 0.000 21.537 0.054 ;
    END
  END rw0_wd_in[189]
  PIN rw0_wd_in[190]
    DIRECTION INPUT ;
    USE SIGNAL ;
    SHAPE ABUTMENT ;
    PORT
      LAYER M3 ;
      RECT 21.807 0.000 21.825 0.054 ;
    END
  END rw0_wd_in[190]
  PIN rw0_wd_in[191]
    DIRECTION INPUT ;
    USE SIGNAL ;
    SHAPE ABUTMENT ;
    PORT
      LAYER M3 ;
      RECT 22.095 0.000 22.113 0.054 ;
    END
  END rw0_wd_in[191]
  PIN rw0_wd_in[192]
    DIRECTION INPUT ;
    USE SIGNAL ;
    SHAPE ABUTMENT ;
    PORT
      LAYER M3 ;
      RECT 22.383 0.000 22.401 0.054 ;
    END
  END rw0_wd_in[192]
  PIN rw0_wd_in[193]
    DIRECTION INPUT ;
    USE SIGNAL ;
    SHAPE ABUTMENT ;
    PORT
      LAYER M3 ;
      RECT 22.671 0.000 22.689 0.054 ;
    END
  END rw0_wd_in[193]
  PIN rw0_wd_in[194]
    DIRECTION INPUT ;
    USE SIGNAL ;
    SHAPE ABUTMENT ;
    PORT
      LAYER M3 ;
      RECT 22.959 0.000 22.977 0.054 ;
    END
  END rw0_wd_in[194]
  PIN rw0_wd_in[195]
    DIRECTION INPUT ;
    USE SIGNAL ;
    SHAPE ABUTMENT ;
    PORT
      LAYER M3 ;
      RECT 23.247 0.000 23.265 0.054 ;
    END
  END rw0_wd_in[195]
  PIN rw0_wd_in[196]
    DIRECTION INPUT ;
    USE SIGNAL ;
    SHAPE ABUTMENT ;
    PORT
      LAYER M3 ;
      RECT 23.535 0.000 23.553 0.054 ;
    END
  END rw0_wd_in[196]
  PIN rw0_wd_in[197]
    DIRECTION INPUT ;
    USE SIGNAL ;
    SHAPE ABUTMENT ;
    PORT
      LAYER M3 ;
      RECT 23.823 0.000 23.841 0.054 ;
    END
  END rw0_wd_in[197]
  PIN rw0_wd_in[198]
    DIRECTION INPUT ;
    USE SIGNAL ;
    SHAPE ABUTMENT ;
    PORT
      LAYER M3 ;
      RECT 24.111 0.000 24.129 0.054 ;
    END
  END rw0_wd_in[198]
  PIN rw0_wd_in[199]
    DIRECTION INPUT ;
    USE SIGNAL ;
    SHAPE ABUTMENT ;
    PORT
      LAYER M3 ;
      RECT 24.399 0.000 24.417 0.054 ;
    END
  END rw0_wd_in[199]
  PIN rw0_wd_in[200]
    DIRECTION INPUT ;
    USE SIGNAL ;
    SHAPE ABUTMENT ;
    PORT
      LAYER M3 ;
      RECT 24.687 0.000 24.705 0.054 ;
    END
  END rw0_wd_in[200]
  PIN rw0_wd_in[201]
    DIRECTION INPUT ;
    USE SIGNAL ;
    SHAPE ABUTMENT ;
    PORT
      LAYER M3 ;
      RECT 24.975 0.000 24.993 0.054 ;
    END
  END rw0_wd_in[201]
  PIN rw0_wd_in[202]
    DIRECTION INPUT ;
    USE SIGNAL ;
    SHAPE ABUTMENT ;
    PORT
      LAYER M3 ;
      RECT 25.263 0.000 25.281 0.054 ;
    END
  END rw0_wd_in[202]
  PIN rw0_wd_in[203]
    DIRECTION INPUT ;
    USE SIGNAL ;
    SHAPE ABUTMENT ;
    PORT
      LAYER M3 ;
      RECT 25.551 0.000 25.569 0.054 ;
    END
  END rw0_wd_in[203]
  PIN rw0_wd_in[204]
    DIRECTION INPUT ;
    USE SIGNAL ;
    SHAPE ABUTMENT ;
    PORT
      LAYER M3 ;
      RECT 25.839 0.000 25.857 0.054 ;
    END
  END rw0_wd_in[204]
  PIN rw0_wd_in[205]
    DIRECTION INPUT ;
    USE SIGNAL ;
    SHAPE ABUTMENT ;
    PORT
      LAYER M3 ;
      RECT 26.127 0.000 26.145 0.054 ;
    END
  END rw0_wd_in[205]
  PIN rw0_wd_in[206]
    DIRECTION INPUT ;
    USE SIGNAL ;
    SHAPE ABUTMENT ;
    PORT
      LAYER M3 ;
      RECT 26.415 0.000 26.433 0.054 ;
    END
  END rw0_wd_in[206]
  PIN rw0_wd_in[207]
    DIRECTION INPUT ;
    USE SIGNAL ;
    SHAPE ABUTMENT ;
    PORT
      LAYER M3 ;
      RECT 26.703 0.000 26.721 0.054 ;
    END
  END rw0_wd_in[207]
  PIN rw0_wd_in[208]
    DIRECTION INPUT ;
    USE SIGNAL ;
    SHAPE ABUTMENT ;
    PORT
      LAYER M3 ;
      RECT 26.991 0.000 27.009 0.054 ;
    END
  END rw0_wd_in[208]
  PIN rw0_wd_in[209]
    DIRECTION INPUT ;
    USE SIGNAL ;
    SHAPE ABUTMENT ;
    PORT
      LAYER M3 ;
      RECT 27.279 0.000 27.297 0.054 ;
    END
  END rw0_wd_in[209]
  PIN rw0_wd_in[210]
    DIRECTION INPUT ;
    USE SIGNAL ;
    SHAPE ABUTMENT ;
    PORT
      LAYER M3 ;
      RECT 27.567 0.000 27.585 0.054 ;
    END
  END rw0_wd_in[210]
  PIN rw0_wd_in[211]
    DIRECTION INPUT ;
    USE SIGNAL ;
    SHAPE ABUTMENT ;
    PORT
      LAYER M3 ;
      RECT 27.855 0.000 27.873 0.054 ;
    END
  END rw0_wd_in[211]
  PIN rw0_wd_in[212]
    DIRECTION INPUT ;
    USE SIGNAL ;
    SHAPE ABUTMENT ;
    PORT
      LAYER M3 ;
      RECT 28.143 0.000 28.161 0.054 ;
    END
  END rw0_wd_in[212]
  PIN rw0_wd_in[213]
    DIRECTION INPUT ;
    USE SIGNAL ;
    SHAPE ABUTMENT ;
    PORT
      LAYER M3 ;
      RECT 28.431 0.000 28.449 0.054 ;
    END
  END rw0_wd_in[213]
  PIN rw0_wd_in[214]
    DIRECTION INPUT ;
    USE SIGNAL ;
    SHAPE ABUTMENT ;
    PORT
      LAYER M3 ;
      RECT 28.719 0.000 28.737 0.054 ;
    END
  END rw0_wd_in[214]
  PIN rw0_wd_in[215]
    DIRECTION INPUT ;
    USE SIGNAL ;
    SHAPE ABUTMENT ;
    PORT
      LAYER M3 ;
      RECT 29.007 0.000 29.025 0.054 ;
    END
  END rw0_wd_in[215]
  PIN rw0_wd_in[216]
    DIRECTION INPUT ;
    USE SIGNAL ;
    SHAPE ABUTMENT ;
    PORT
      LAYER M3 ;
      RECT 29.295 0.000 29.313 0.054 ;
    END
  END rw0_wd_in[216]
  PIN rw0_wd_in[217]
    DIRECTION INPUT ;
    USE SIGNAL ;
    SHAPE ABUTMENT ;
    PORT
      LAYER M3 ;
      RECT 29.583 0.000 29.601 0.054 ;
    END
  END rw0_wd_in[217]
  PIN rw0_wd_in[218]
    DIRECTION INPUT ;
    USE SIGNAL ;
    SHAPE ABUTMENT ;
    PORT
      LAYER M3 ;
      RECT 29.871 0.000 29.889 0.054 ;
    END
  END rw0_wd_in[218]
  PIN rw0_wd_in[219]
    DIRECTION INPUT ;
    USE SIGNAL ;
    SHAPE ABUTMENT ;
    PORT
      LAYER M3 ;
      RECT 30.159 0.000 30.177 0.054 ;
    END
  END rw0_wd_in[219]
  PIN rw0_wd_in[220]
    DIRECTION INPUT ;
    USE SIGNAL ;
    SHAPE ABUTMENT ;
    PORT
      LAYER M3 ;
      RECT 30.447 0.000 30.465 0.054 ;
    END
  END rw0_wd_in[220]
  PIN rw0_wd_in[221]
    DIRECTION INPUT ;
    USE SIGNAL ;
    SHAPE ABUTMENT ;
    PORT
      LAYER M3 ;
      RECT 30.735 0.000 30.753 0.054 ;
    END
  END rw0_wd_in[221]
  PIN rw0_wd_in[222]
    DIRECTION INPUT ;
    USE SIGNAL ;
    SHAPE ABUTMENT ;
    PORT
      LAYER M3 ;
      RECT 31.023 0.000 31.041 0.054 ;
    END
  END rw0_wd_in[222]
  PIN rw0_wd_in[223]
    DIRECTION INPUT ;
    USE SIGNAL ;
    SHAPE ABUTMENT ;
    PORT
      LAYER M3 ;
      RECT 31.311 0.000 31.329 0.054 ;
    END
  END rw0_wd_in[223]
  PIN rw0_wd_in[224]
    DIRECTION INPUT ;
    USE SIGNAL ;
    SHAPE ABUTMENT ;
    PORT
      LAYER M3 ;
      RECT 31.599 0.000 31.617 0.054 ;
    END
  END rw0_wd_in[224]
  PIN rw0_wd_in[225]
    DIRECTION INPUT ;
    USE SIGNAL ;
    SHAPE ABUTMENT ;
    PORT
      LAYER M3 ;
      RECT 31.887 0.000 31.905 0.054 ;
    END
  END rw0_wd_in[225]
  PIN rw0_wd_in[226]
    DIRECTION INPUT ;
    USE SIGNAL ;
    SHAPE ABUTMENT ;
    PORT
      LAYER M3 ;
      RECT 32.175 0.000 32.193 0.054 ;
    END
  END rw0_wd_in[226]
  PIN rw0_wd_in[227]
    DIRECTION INPUT ;
    USE SIGNAL ;
    SHAPE ABUTMENT ;
    PORT
      LAYER M3 ;
      RECT 32.463 0.000 32.481 0.054 ;
    END
  END rw0_wd_in[227]
  PIN rw0_wd_in[228]
    DIRECTION INPUT ;
    USE SIGNAL ;
    SHAPE ABUTMENT ;
    PORT
      LAYER M3 ;
      RECT 32.751 0.000 32.769 0.054 ;
    END
  END rw0_wd_in[228]
  PIN rw0_wd_in[229]
    DIRECTION INPUT ;
    USE SIGNAL ;
    SHAPE ABUTMENT ;
    PORT
      LAYER M3 ;
      RECT 33.039 0.000 33.057 0.054 ;
    END
  END rw0_wd_in[229]
  PIN rw0_rd_out[0]
    DIRECTION OUTPUT ;
    USE SIGNAL ;
    SHAPE ABUTMENT ;
    PORT
      LAYER M3 ;
      RECT 33.327 0.000 33.345 0.054 ;
    END
  END rw0_rd_out[0]
  PIN rw0_rd_out[1]
    DIRECTION OUTPUT ;
    USE SIGNAL ;
    SHAPE ABUTMENT ;
    PORT
      LAYER M3 ;
      RECT 33.615 0.000 33.633 0.054 ;
    END
  END rw0_rd_out[1]
  PIN rw0_rd_out[2]
    DIRECTION OUTPUT ;
    USE SIGNAL ;
    SHAPE ABUTMENT ;
    PORT
      LAYER M3 ;
      RECT 33.903 0.000 33.921 0.054 ;
    END
  END rw0_rd_out[2]
  PIN rw0_rd_out[3]
    DIRECTION OUTPUT ;
    USE SIGNAL ;
    SHAPE ABUTMENT ;
    PORT
      LAYER M3 ;
      RECT 34.191 0.000 34.209 0.054 ;
    END
  END rw0_rd_out[3]
  PIN rw0_rd_out[4]
    DIRECTION OUTPUT ;
    USE SIGNAL ;
    SHAPE ABUTMENT ;
    PORT
      LAYER M3 ;
      RECT 34.479 0.000 34.497 0.054 ;
    END
  END rw0_rd_out[4]
  PIN rw0_rd_out[5]
    DIRECTION OUTPUT ;
    USE SIGNAL ;
    SHAPE ABUTMENT ;
    PORT
      LAYER M3 ;
      RECT 34.767 0.000 34.785 0.054 ;
    END
  END rw0_rd_out[5]
  PIN rw0_rd_out[6]
    DIRECTION OUTPUT ;
    USE SIGNAL ;
    SHAPE ABUTMENT ;
    PORT
      LAYER M3 ;
      RECT 35.055 0.000 35.073 0.054 ;
    END
  END rw0_rd_out[6]
  PIN rw0_rd_out[7]
    DIRECTION OUTPUT ;
    USE SIGNAL ;
    SHAPE ABUTMENT ;
    PORT
      LAYER M3 ;
      RECT 35.343 0.000 35.361 0.054 ;
    END
  END rw0_rd_out[7]
  PIN rw0_rd_out[8]
    DIRECTION OUTPUT ;
    USE SIGNAL ;
    SHAPE ABUTMENT ;
    PORT
      LAYER M3 ;
      RECT 35.631 0.000 35.649 0.054 ;
    END
  END rw0_rd_out[8]
  PIN rw0_rd_out[9]
    DIRECTION OUTPUT ;
    USE SIGNAL ;
    SHAPE ABUTMENT ;
    PORT
      LAYER M3 ;
      RECT 35.919 0.000 35.937 0.054 ;
    END
  END rw0_rd_out[9]
  PIN rw0_rd_out[10]
    DIRECTION OUTPUT ;
    USE SIGNAL ;
    SHAPE ABUTMENT ;
    PORT
      LAYER M3 ;
      RECT 36.207 0.000 36.225 0.054 ;
    END
  END rw0_rd_out[10]
  PIN rw0_rd_out[11]
    DIRECTION OUTPUT ;
    USE SIGNAL ;
    SHAPE ABUTMENT ;
    PORT
      LAYER M3 ;
      RECT 36.495 0.000 36.513 0.054 ;
    END
  END rw0_rd_out[11]
  PIN rw0_rd_out[12]
    DIRECTION OUTPUT ;
    USE SIGNAL ;
    SHAPE ABUTMENT ;
    PORT
      LAYER M3 ;
      RECT 36.783 0.000 36.801 0.054 ;
    END
  END rw0_rd_out[12]
  PIN rw0_rd_out[13]
    DIRECTION OUTPUT ;
    USE SIGNAL ;
    SHAPE ABUTMENT ;
    PORT
      LAYER M3 ;
      RECT 37.071 0.000 37.089 0.054 ;
    END
  END rw0_rd_out[13]
  PIN rw0_rd_out[14]
    DIRECTION OUTPUT ;
    USE SIGNAL ;
    SHAPE ABUTMENT ;
    PORT
      LAYER M3 ;
      RECT 37.359 0.000 37.377 0.054 ;
    END
  END rw0_rd_out[14]
  PIN rw0_rd_out[15]
    DIRECTION OUTPUT ;
    USE SIGNAL ;
    SHAPE ABUTMENT ;
    PORT
      LAYER M3 ;
      RECT 37.647 0.000 37.665 0.054 ;
    END
  END rw0_rd_out[15]
  PIN rw0_rd_out[16]
    DIRECTION OUTPUT ;
    USE SIGNAL ;
    SHAPE ABUTMENT ;
    PORT
      LAYER M3 ;
      RECT 37.935 0.000 37.953 0.054 ;
    END
  END rw0_rd_out[16]
  PIN rw0_rd_out[17]
    DIRECTION OUTPUT ;
    USE SIGNAL ;
    SHAPE ABUTMENT ;
    PORT
      LAYER M3 ;
      RECT 38.223 0.000 38.241 0.054 ;
    END
  END rw0_rd_out[17]
  PIN rw0_rd_out[18]
    DIRECTION OUTPUT ;
    USE SIGNAL ;
    SHAPE ABUTMENT ;
    PORT
      LAYER M3 ;
      RECT 38.511 0.000 38.529 0.054 ;
    END
  END rw0_rd_out[18]
  PIN rw0_rd_out[19]
    DIRECTION OUTPUT ;
    USE SIGNAL ;
    SHAPE ABUTMENT ;
    PORT
      LAYER M3 ;
      RECT 38.799 0.000 38.817 0.054 ;
    END
  END rw0_rd_out[19]
  PIN rw0_rd_out[20]
    DIRECTION OUTPUT ;
    USE SIGNAL ;
    SHAPE ABUTMENT ;
    PORT
      LAYER M3 ;
      RECT 39.087 0.000 39.105 0.054 ;
    END
  END rw0_rd_out[20]
  PIN rw0_rd_out[21]
    DIRECTION OUTPUT ;
    USE SIGNAL ;
    SHAPE ABUTMENT ;
    PORT
      LAYER M3 ;
      RECT 39.375 0.000 39.393 0.054 ;
    END
  END rw0_rd_out[21]
  PIN rw0_rd_out[22]
    DIRECTION OUTPUT ;
    USE SIGNAL ;
    SHAPE ABUTMENT ;
    PORT
      LAYER M3 ;
      RECT 39.663 0.000 39.681 0.054 ;
    END
  END rw0_rd_out[22]
  PIN rw0_rd_out[23]
    DIRECTION OUTPUT ;
    USE SIGNAL ;
    SHAPE ABUTMENT ;
    PORT
      LAYER M3 ;
      RECT 39.951 0.000 39.969 0.054 ;
    END
  END rw0_rd_out[23]
  PIN rw0_rd_out[24]
    DIRECTION OUTPUT ;
    USE SIGNAL ;
    SHAPE ABUTMENT ;
    PORT
      LAYER M3 ;
      RECT 40.239 0.000 40.257 0.054 ;
    END
  END rw0_rd_out[24]
  PIN rw0_rd_out[25]
    DIRECTION OUTPUT ;
    USE SIGNAL ;
    SHAPE ABUTMENT ;
    PORT
      LAYER M3 ;
      RECT 40.527 0.000 40.545 0.054 ;
    END
  END rw0_rd_out[25]
  PIN rw0_rd_out[26]
    DIRECTION OUTPUT ;
    USE SIGNAL ;
    SHAPE ABUTMENT ;
    PORT
      LAYER M3 ;
      RECT 40.815 0.000 40.833 0.054 ;
    END
  END rw0_rd_out[26]
  PIN rw0_rd_out[27]
    DIRECTION OUTPUT ;
    USE SIGNAL ;
    SHAPE ABUTMENT ;
    PORT
      LAYER M3 ;
      RECT 41.103 0.000 41.121 0.054 ;
    END
  END rw0_rd_out[27]
  PIN rw0_rd_out[28]
    DIRECTION OUTPUT ;
    USE SIGNAL ;
    SHAPE ABUTMENT ;
    PORT
      LAYER M3 ;
      RECT 41.391 0.000 41.409 0.054 ;
    END
  END rw0_rd_out[28]
  PIN rw0_rd_out[29]
    DIRECTION OUTPUT ;
    USE SIGNAL ;
    SHAPE ABUTMENT ;
    PORT
      LAYER M3 ;
      RECT 41.679 0.000 41.697 0.054 ;
    END
  END rw0_rd_out[29]
  PIN rw0_rd_out[30]
    DIRECTION OUTPUT ;
    USE SIGNAL ;
    SHAPE ABUTMENT ;
    PORT
      LAYER M3 ;
      RECT 41.967 0.000 41.985 0.054 ;
    END
  END rw0_rd_out[30]
  PIN rw0_rd_out[31]
    DIRECTION OUTPUT ;
    USE SIGNAL ;
    SHAPE ABUTMENT ;
    PORT
      LAYER M3 ;
      RECT 42.255 0.000 42.273 0.054 ;
    END
  END rw0_rd_out[31]
  PIN rw0_rd_out[32]
    DIRECTION OUTPUT ;
    USE SIGNAL ;
    SHAPE ABUTMENT ;
    PORT
      LAYER M3 ;
      RECT 42.543 0.000 42.561 0.054 ;
    END
  END rw0_rd_out[32]
  PIN rw0_rd_out[33]
    DIRECTION OUTPUT ;
    USE SIGNAL ;
    SHAPE ABUTMENT ;
    PORT
      LAYER M3 ;
      RECT 42.831 0.000 42.849 0.054 ;
    END
  END rw0_rd_out[33]
  PIN rw0_rd_out[34]
    DIRECTION OUTPUT ;
    USE SIGNAL ;
    SHAPE ABUTMENT ;
    PORT
      LAYER M3 ;
      RECT 43.119 0.000 43.137 0.054 ;
    END
  END rw0_rd_out[34]
  PIN rw0_rd_out[35]
    DIRECTION OUTPUT ;
    USE SIGNAL ;
    SHAPE ABUTMENT ;
    PORT
      LAYER M3 ;
      RECT 43.407 0.000 43.425 0.054 ;
    END
  END rw0_rd_out[35]
  PIN rw0_rd_out[36]
    DIRECTION OUTPUT ;
    USE SIGNAL ;
    SHAPE ABUTMENT ;
    PORT
      LAYER M3 ;
      RECT 43.695 0.000 43.713 0.054 ;
    END
  END rw0_rd_out[36]
  PIN rw0_rd_out[37]
    DIRECTION OUTPUT ;
    USE SIGNAL ;
    SHAPE ABUTMENT ;
    PORT
      LAYER M3 ;
      RECT 43.983 0.000 44.001 0.054 ;
    END
  END rw0_rd_out[37]
  PIN rw0_rd_out[38]
    DIRECTION OUTPUT ;
    USE SIGNAL ;
    SHAPE ABUTMENT ;
    PORT
      LAYER M3 ;
      RECT 44.271 0.000 44.289 0.054 ;
    END
  END rw0_rd_out[38]
  PIN rw0_rd_out[39]
    DIRECTION OUTPUT ;
    USE SIGNAL ;
    SHAPE ABUTMENT ;
    PORT
      LAYER M3 ;
      RECT 44.559 0.000 44.577 0.054 ;
    END
  END rw0_rd_out[39]
  PIN rw0_rd_out[40]
    DIRECTION OUTPUT ;
    USE SIGNAL ;
    SHAPE ABUTMENT ;
    PORT
      LAYER M3 ;
      RECT 44.847 0.000 44.865 0.054 ;
    END
  END rw0_rd_out[40]
  PIN rw0_rd_out[41]
    DIRECTION OUTPUT ;
    USE SIGNAL ;
    SHAPE ABUTMENT ;
    PORT
      LAYER M3 ;
      RECT 45.135 0.000 45.153 0.054 ;
    END
  END rw0_rd_out[41]
  PIN rw0_rd_out[42]
    DIRECTION OUTPUT ;
    USE SIGNAL ;
    SHAPE ABUTMENT ;
    PORT
      LAYER M3 ;
      RECT 45.423 0.000 45.441 0.054 ;
    END
  END rw0_rd_out[42]
  PIN rw0_rd_out[43]
    DIRECTION OUTPUT ;
    USE SIGNAL ;
    SHAPE ABUTMENT ;
    PORT
      LAYER M3 ;
      RECT 45.711 0.000 45.729 0.054 ;
    END
  END rw0_rd_out[43]
  PIN rw0_rd_out[44]
    DIRECTION OUTPUT ;
    USE SIGNAL ;
    SHAPE ABUTMENT ;
    PORT
      LAYER M3 ;
      RECT 45.999 0.000 46.017 0.054 ;
    END
  END rw0_rd_out[44]
  PIN rw0_rd_out[45]
    DIRECTION OUTPUT ;
    USE SIGNAL ;
    SHAPE ABUTMENT ;
    PORT
      LAYER M3 ;
      RECT 46.287 0.000 46.305 0.054 ;
    END
  END rw0_rd_out[45]
  PIN rw0_rd_out[46]
    DIRECTION OUTPUT ;
    USE SIGNAL ;
    SHAPE ABUTMENT ;
    PORT
      LAYER M3 ;
      RECT 46.575 0.000 46.593 0.054 ;
    END
  END rw0_rd_out[46]
  PIN rw0_rd_out[47]
    DIRECTION OUTPUT ;
    USE SIGNAL ;
    SHAPE ABUTMENT ;
    PORT
      LAYER M3 ;
      RECT 46.863 0.000 46.881 0.054 ;
    END
  END rw0_rd_out[47]
  PIN rw0_rd_out[48]
    DIRECTION OUTPUT ;
    USE SIGNAL ;
    SHAPE ABUTMENT ;
    PORT
      LAYER M3 ;
      RECT 47.151 0.000 47.169 0.054 ;
    END
  END rw0_rd_out[48]
  PIN rw0_rd_out[49]
    DIRECTION OUTPUT ;
    USE SIGNAL ;
    SHAPE ABUTMENT ;
    PORT
      LAYER M3 ;
      RECT 47.439 0.000 47.457 0.054 ;
    END
  END rw0_rd_out[49]
  PIN rw0_rd_out[50]
    DIRECTION OUTPUT ;
    USE SIGNAL ;
    SHAPE ABUTMENT ;
    PORT
      LAYER M3 ;
      RECT 47.727 0.000 47.745 0.054 ;
    END
  END rw0_rd_out[50]
  PIN rw0_rd_out[51]
    DIRECTION OUTPUT ;
    USE SIGNAL ;
    SHAPE ABUTMENT ;
    PORT
      LAYER M3 ;
      RECT 48.015 0.000 48.033 0.054 ;
    END
  END rw0_rd_out[51]
  PIN rw0_rd_out[52]
    DIRECTION OUTPUT ;
    USE SIGNAL ;
    SHAPE ABUTMENT ;
    PORT
      LAYER M3 ;
      RECT 48.303 0.000 48.321 0.054 ;
    END
  END rw0_rd_out[52]
  PIN rw0_rd_out[53]
    DIRECTION OUTPUT ;
    USE SIGNAL ;
    SHAPE ABUTMENT ;
    PORT
      LAYER M3 ;
      RECT 48.591 0.000 48.609 0.054 ;
    END
  END rw0_rd_out[53]
  PIN rw0_rd_out[54]
    DIRECTION OUTPUT ;
    USE SIGNAL ;
    SHAPE ABUTMENT ;
    PORT
      LAYER M3 ;
      RECT 48.879 0.000 48.897 0.054 ;
    END
  END rw0_rd_out[54]
  PIN rw0_rd_out[55]
    DIRECTION OUTPUT ;
    USE SIGNAL ;
    SHAPE ABUTMENT ;
    PORT
      LAYER M3 ;
      RECT 49.167 0.000 49.185 0.054 ;
    END
  END rw0_rd_out[55]
  PIN rw0_rd_out[56]
    DIRECTION OUTPUT ;
    USE SIGNAL ;
    SHAPE ABUTMENT ;
    PORT
      LAYER M3 ;
      RECT 49.455 0.000 49.473 0.054 ;
    END
  END rw0_rd_out[56]
  PIN rw0_rd_out[57]
    DIRECTION OUTPUT ;
    USE SIGNAL ;
    SHAPE ABUTMENT ;
    PORT
      LAYER M3 ;
      RECT 49.743 0.000 49.761 0.054 ;
    END
  END rw0_rd_out[57]
  PIN rw0_rd_out[58]
    DIRECTION OUTPUT ;
    USE SIGNAL ;
    SHAPE ABUTMENT ;
    PORT
      LAYER M3 ;
      RECT 50.031 0.000 50.049 0.054 ;
    END
  END rw0_rd_out[58]
  PIN rw0_rd_out[59]
    DIRECTION OUTPUT ;
    USE SIGNAL ;
    SHAPE ABUTMENT ;
    PORT
      LAYER M3 ;
      RECT 50.319 0.000 50.337 0.054 ;
    END
  END rw0_rd_out[59]
  PIN rw0_rd_out[60]
    DIRECTION OUTPUT ;
    USE SIGNAL ;
    SHAPE ABUTMENT ;
    PORT
      LAYER M3 ;
      RECT 50.607 0.000 50.625 0.054 ;
    END
  END rw0_rd_out[60]
  PIN rw0_rd_out[61]
    DIRECTION OUTPUT ;
    USE SIGNAL ;
    SHAPE ABUTMENT ;
    PORT
      LAYER M3 ;
      RECT 50.895 0.000 50.913 0.054 ;
    END
  END rw0_rd_out[61]
  PIN rw0_rd_out[62]
    DIRECTION OUTPUT ;
    USE SIGNAL ;
    SHAPE ABUTMENT ;
    PORT
      LAYER M3 ;
      RECT 51.183 0.000 51.201 0.054 ;
    END
  END rw0_rd_out[62]
  PIN rw0_rd_out[63]
    DIRECTION OUTPUT ;
    USE SIGNAL ;
    SHAPE ABUTMENT ;
    PORT
      LAYER M3 ;
      RECT 51.471 0.000 51.489 0.054 ;
    END
  END rw0_rd_out[63]
  PIN rw0_rd_out[64]
    DIRECTION OUTPUT ;
    USE SIGNAL ;
    SHAPE ABUTMENT ;
    PORT
      LAYER M3 ;
      RECT 51.759 0.000 51.777 0.054 ;
    END
  END rw0_rd_out[64]
  PIN rw0_rd_out[65]
    DIRECTION OUTPUT ;
    USE SIGNAL ;
    SHAPE ABUTMENT ;
    PORT
      LAYER M3 ;
      RECT 52.047 0.000 52.065 0.054 ;
    END
  END rw0_rd_out[65]
  PIN rw0_rd_out[66]
    DIRECTION OUTPUT ;
    USE SIGNAL ;
    SHAPE ABUTMENT ;
    PORT
      LAYER M3 ;
      RECT 52.335 0.000 52.353 0.054 ;
    END
  END rw0_rd_out[66]
  PIN rw0_rd_out[67]
    DIRECTION OUTPUT ;
    USE SIGNAL ;
    SHAPE ABUTMENT ;
    PORT
      LAYER M3 ;
      RECT 52.623 0.000 52.641 0.054 ;
    END
  END rw0_rd_out[67]
  PIN rw0_rd_out[68]
    DIRECTION OUTPUT ;
    USE SIGNAL ;
    SHAPE ABUTMENT ;
    PORT
      LAYER M3 ;
      RECT 52.911 0.000 52.929 0.054 ;
    END
  END rw0_rd_out[68]
  PIN rw0_rd_out[69]
    DIRECTION OUTPUT ;
    USE SIGNAL ;
    SHAPE ABUTMENT ;
    PORT
      LAYER M3 ;
      RECT 53.199 0.000 53.217 0.054 ;
    END
  END rw0_rd_out[69]
  PIN rw0_rd_out[70]
    DIRECTION OUTPUT ;
    USE SIGNAL ;
    SHAPE ABUTMENT ;
    PORT
      LAYER M3 ;
      RECT 53.487 0.000 53.505 0.054 ;
    END
  END rw0_rd_out[70]
  PIN rw0_rd_out[71]
    DIRECTION OUTPUT ;
    USE SIGNAL ;
    SHAPE ABUTMENT ;
    PORT
      LAYER M3 ;
      RECT 53.775 0.000 53.793 0.054 ;
    END
  END rw0_rd_out[71]
  PIN rw0_rd_out[72]
    DIRECTION OUTPUT ;
    USE SIGNAL ;
    SHAPE ABUTMENT ;
    PORT
      LAYER M3 ;
      RECT 54.063 0.000 54.081 0.054 ;
    END
  END rw0_rd_out[72]
  PIN rw0_rd_out[73]
    DIRECTION OUTPUT ;
    USE SIGNAL ;
    SHAPE ABUTMENT ;
    PORT
      LAYER M3 ;
      RECT 54.351 0.000 54.369 0.054 ;
    END
  END rw0_rd_out[73]
  PIN rw0_rd_out[74]
    DIRECTION OUTPUT ;
    USE SIGNAL ;
    SHAPE ABUTMENT ;
    PORT
      LAYER M3 ;
      RECT 54.639 0.000 54.657 0.054 ;
    END
  END rw0_rd_out[74]
  PIN rw0_rd_out[75]
    DIRECTION OUTPUT ;
    USE SIGNAL ;
    SHAPE ABUTMENT ;
    PORT
      LAYER M3 ;
      RECT 54.927 0.000 54.945 0.054 ;
    END
  END rw0_rd_out[75]
  PIN rw0_rd_out[76]
    DIRECTION OUTPUT ;
    USE SIGNAL ;
    SHAPE ABUTMENT ;
    PORT
      LAYER M3 ;
      RECT 55.215 0.000 55.233 0.054 ;
    END
  END rw0_rd_out[76]
  PIN rw0_rd_out[77]
    DIRECTION OUTPUT ;
    USE SIGNAL ;
    SHAPE ABUTMENT ;
    PORT
      LAYER M3 ;
      RECT 55.503 0.000 55.521 0.054 ;
    END
  END rw0_rd_out[77]
  PIN rw0_rd_out[78]
    DIRECTION OUTPUT ;
    USE SIGNAL ;
    SHAPE ABUTMENT ;
    PORT
      LAYER M3 ;
      RECT 55.791 0.000 55.809 0.054 ;
    END
  END rw0_rd_out[78]
  PIN rw0_rd_out[79]
    DIRECTION OUTPUT ;
    USE SIGNAL ;
    SHAPE ABUTMENT ;
    PORT
      LAYER M3 ;
      RECT 56.079 0.000 56.097 0.054 ;
    END
  END rw0_rd_out[79]
  PIN rw0_rd_out[80]
    DIRECTION OUTPUT ;
    USE SIGNAL ;
    SHAPE ABUTMENT ;
    PORT
      LAYER M3 ;
      RECT 56.367 0.000 56.385 0.054 ;
    END
  END rw0_rd_out[80]
  PIN rw0_rd_out[81]
    DIRECTION OUTPUT ;
    USE SIGNAL ;
    SHAPE ABUTMENT ;
    PORT
      LAYER M3 ;
      RECT 56.655 0.000 56.673 0.054 ;
    END
  END rw0_rd_out[81]
  PIN rw0_rd_out[82]
    DIRECTION OUTPUT ;
    USE SIGNAL ;
    SHAPE ABUTMENT ;
    PORT
      LAYER M3 ;
      RECT 56.943 0.000 56.961 0.054 ;
    END
  END rw0_rd_out[82]
  PIN rw0_rd_out[83]
    DIRECTION OUTPUT ;
    USE SIGNAL ;
    SHAPE ABUTMENT ;
    PORT
      LAYER M3 ;
      RECT 57.231 0.000 57.249 0.054 ;
    END
  END rw0_rd_out[83]
  PIN rw0_rd_out[84]
    DIRECTION OUTPUT ;
    USE SIGNAL ;
    SHAPE ABUTMENT ;
    PORT
      LAYER M3 ;
      RECT 57.519 0.000 57.537 0.054 ;
    END
  END rw0_rd_out[84]
  PIN rw0_rd_out[85]
    DIRECTION OUTPUT ;
    USE SIGNAL ;
    SHAPE ABUTMENT ;
    PORT
      LAYER M3 ;
      RECT 57.807 0.000 57.825 0.054 ;
    END
  END rw0_rd_out[85]
  PIN rw0_rd_out[86]
    DIRECTION OUTPUT ;
    USE SIGNAL ;
    SHAPE ABUTMENT ;
    PORT
      LAYER M3 ;
      RECT 58.095 0.000 58.113 0.054 ;
    END
  END rw0_rd_out[86]
  PIN rw0_rd_out[87]
    DIRECTION OUTPUT ;
    USE SIGNAL ;
    SHAPE ABUTMENT ;
    PORT
      LAYER M3 ;
      RECT 58.383 0.000 58.401 0.054 ;
    END
  END rw0_rd_out[87]
  PIN rw0_rd_out[88]
    DIRECTION OUTPUT ;
    USE SIGNAL ;
    SHAPE ABUTMENT ;
    PORT
      LAYER M3 ;
      RECT 58.671 0.000 58.689 0.054 ;
    END
  END rw0_rd_out[88]
  PIN rw0_rd_out[89]
    DIRECTION OUTPUT ;
    USE SIGNAL ;
    SHAPE ABUTMENT ;
    PORT
      LAYER M3 ;
      RECT 58.959 0.000 58.977 0.054 ;
    END
  END rw0_rd_out[89]
  PIN rw0_rd_out[90]
    DIRECTION OUTPUT ;
    USE SIGNAL ;
    SHAPE ABUTMENT ;
    PORT
      LAYER M3 ;
      RECT 59.247 0.000 59.265 0.054 ;
    END
  END rw0_rd_out[90]
  PIN rw0_rd_out[91]
    DIRECTION OUTPUT ;
    USE SIGNAL ;
    SHAPE ABUTMENT ;
    PORT
      LAYER M3 ;
      RECT 59.535 0.000 59.553 0.054 ;
    END
  END rw0_rd_out[91]
  PIN rw0_rd_out[92]
    DIRECTION OUTPUT ;
    USE SIGNAL ;
    SHAPE ABUTMENT ;
    PORT
      LAYER M3 ;
      RECT 59.823 0.000 59.841 0.054 ;
    END
  END rw0_rd_out[92]
  PIN rw0_rd_out[93]
    DIRECTION OUTPUT ;
    USE SIGNAL ;
    SHAPE ABUTMENT ;
    PORT
      LAYER M3 ;
      RECT 60.111 0.000 60.129 0.054 ;
    END
  END rw0_rd_out[93]
  PIN rw0_rd_out[94]
    DIRECTION OUTPUT ;
    USE SIGNAL ;
    SHAPE ABUTMENT ;
    PORT
      LAYER M3 ;
      RECT 60.399 0.000 60.417 0.054 ;
    END
  END rw0_rd_out[94]
  PIN rw0_rd_out[95]
    DIRECTION OUTPUT ;
    USE SIGNAL ;
    SHAPE ABUTMENT ;
    PORT
      LAYER M3 ;
      RECT 60.687 0.000 60.705 0.054 ;
    END
  END rw0_rd_out[95]
  PIN rw0_rd_out[96]
    DIRECTION OUTPUT ;
    USE SIGNAL ;
    SHAPE ABUTMENT ;
    PORT
      LAYER M3 ;
      RECT 60.975 0.000 60.993 0.054 ;
    END
  END rw0_rd_out[96]
  PIN rw0_rd_out[97]
    DIRECTION OUTPUT ;
    USE SIGNAL ;
    SHAPE ABUTMENT ;
    PORT
      LAYER M3 ;
      RECT 61.263 0.000 61.281 0.054 ;
    END
  END rw0_rd_out[97]
  PIN rw0_rd_out[98]
    DIRECTION OUTPUT ;
    USE SIGNAL ;
    SHAPE ABUTMENT ;
    PORT
      LAYER M3 ;
      RECT 61.551 0.000 61.569 0.054 ;
    END
  END rw0_rd_out[98]
  PIN rw0_rd_out[99]
    DIRECTION OUTPUT ;
    USE SIGNAL ;
    SHAPE ABUTMENT ;
    PORT
      LAYER M3 ;
      RECT 61.839 0.000 61.857 0.054 ;
    END
  END rw0_rd_out[99]
  PIN rw0_rd_out[100]
    DIRECTION OUTPUT ;
    USE SIGNAL ;
    SHAPE ABUTMENT ;
    PORT
      LAYER M3 ;
      RECT 62.127 0.000 62.145 0.054 ;
    END
  END rw0_rd_out[100]
  PIN rw0_rd_out[101]
    DIRECTION OUTPUT ;
    USE SIGNAL ;
    SHAPE ABUTMENT ;
    PORT
      LAYER M3 ;
      RECT 62.415 0.000 62.433 0.054 ;
    END
  END rw0_rd_out[101]
  PIN rw0_rd_out[102]
    DIRECTION OUTPUT ;
    USE SIGNAL ;
    SHAPE ABUTMENT ;
    PORT
      LAYER M3 ;
      RECT 62.703 0.000 62.721 0.054 ;
    END
  END rw0_rd_out[102]
  PIN rw0_rd_out[103]
    DIRECTION OUTPUT ;
    USE SIGNAL ;
    SHAPE ABUTMENT ;
    PORT
      LAYER M3 ;
      RECT 62.991 0.000 63.009 0.054 ;
    END
  END rw0_rd_out[103]
  PIN rw0_rd_out[104]
    DIRECTION OUTPUT ;
    USE SIGNAL ;
    SHAPE ABUTMENT ;
    PORT
      LAYER M3 ;
      RECT 63.279 0.000 63.297 0.054 ;
    END
  END rw0_rd_out[104]
  PIN rw0_rd_out[105]
    DIRECTION OUTPUT ;
    USE SIGNAL ;
    SHAPE ABUTMENT ;
    PORT
      LAYER M3 ;
      RECT 63.567 0.000 63.585 0.054 ;
    END
  END rw0_rd_out[105]
  PIN rw0_rd_out[106]
    DIRECTION OUTPUT ;
    USE SIGNAL ;
    SHAPE ABUTMENT ;
    PORT
      LAYER M3 ;
      RECT 63.855 0.000 63.873 0.054 ;
    END
  END rw0_rd_out[106]
  PIN rw0_rd_out[107]
    DIRECTION OUTPUT ;
    USE SIGNAL ;
    SHAPE ABUTMENT ;
    PORT
      LAYER M3 ;
      RECT 64.143 0.000 64.161 0.054 ;
    END
  END rw0_rd_out[107]
  PIN rw0_rd_out[108]
    DIRECTION OUTPUT ;
    USE SIGNAL ;
    SHAPE ABUTMENT ;
    PORT
      LAYER M3 ;
      RECT 64.431 0.000 64.449 0.054 ;
    END
  END rw0_rd_out[108]
  PIN rw0_rd_out[109]
    DIRECTION OUTPUT ;
    USE SIGNAL ;
    SHAPE ABUTMENT ;
    PORT
      LAYER M3 ;
      RECT 64.719 0.000 64.737 0.054 ;
    END
  END rw0_rd_out[109]
  PIN rw0_rd_out[110]
    DIRECTION OUTPUT ;
    USE SIGNAL ;
    SHAPE ABUTMENT ;
    PORT
      LAYER M3 ;
      RECT 65.007 0.000 65.025 0.054 ;
    END
  END rw0_rd_out[110]
  PIN rw0_rd_out[111]
    DIRECTION OUTPUT ;
    USE SIGNAL ;
    SHAPE ABUTMENT ;
    PORT
      LAYER M3 ;
      RECT 65.295 0.000 65.313 0.054 ;
    END
  END rw0_rd_out[111]
  PIN rw0_rd_out[112]
    DIRECTION OUTPUT ;
    USE SIGNAL ;
    SHAPE ABUTMENT ;
    PORT
      LAYER M3 ;
      RECT 65.583 0.000 65.601 0.054 ;
    END
  END rw0_rd_out[112]
  PIN rw0_rd_out[113]
    DIRECTION OUTPUT ;
    USE SIGNAL ;
    SHAPE ABUTMENT ;
    PORT
      LAYER M3 ;
      RECT 65.871 0.000 65.889 0.054 ;
    END
  END rw0_rd_out[113]
  PIN rw0_rd_out[114]
    DIRECTION OUTPUT ;
    USE SIGNAL ;
    SHAPE ABUTMENT ;
    PORT
      LAYER M3 ;
      RECT 66.159 0.000 66.177 0.054 ;
    END
  END rw0_rd_out[114]
  PIN rw0_rd_out[115]
    DIRECTION OUTPUT ;
    USE SIGNAL ;
    SHAPE ABUTMENT ;
    PORT
      LAYER M3 ;
      RECT 0.207 146.827 0.225 146.881 ;
    END
  END rw0_rd_out[115]
  PIN rw0_rd_out[116]
    DIRECTION OUTPUT ;
    USE SIGNAL ;
    SHAPE ABUTMENT ;
    PORT
      LAYER M3 ;
      RECT 0.639 146.827 0.657 146.881 ;
    END
  END rw0_rd_out[116]
  PIN rw0_rd_out[117]
    DIRECTION OUTPUT ;
    USE SIGNAL ;
    SHAPE ABUTMENT ;
    PORT
      LAYER M3 ;
      RECT 1.071 146.827 1.089 146.881 ;
    END
  END rw0_rd_out[117]
  PIN rw0_rd_out[118]
    DIRECTION OUTPUT ;
    USE SIGNAL ;
    SHAPE ABUTMENT ;
    PORT
      LAYER M3 ;
      RECT 1.503 146.827 1.521 146.881 ;
    END
  END rw0_rd_out[118]
  PIN rw0_rd_out[119]
    DIRECTION OUTPUT ;
    USE SIGNAL ;
    SHAPE ABUTMENT ;
    PORT
      LAYER M3 ;
      RECT 1.935 146.827 1.953 146.881 ;
    END
  END rw0_rd_out[119]
  PIN rw0_rd_out[120]
    DIRECTION OUTPUT ;
    USE SIGNAL ;
    SHAPE ABUTMENT ;
    PORT
      LAYER M3 ;
      RECT 2.367 146.827 2.385 146.881 ;
    END
  END rw0_rd_out[120]
  PIN rw0_rd_out[121]
    DIRECTION OUTPUT ;
    USE SIGNAL ;
    SHAPE ABUTMENT ;
    PORT
      LAYER M3 ;
      RECT 2.799 146.827 2.817 146.881 ;
    END
  END rw0_rd_out[121]
  PIN rw0_rd_out[122]
    DIRECTION OUTPUT ;
    USE SIGNAL ;
    SHAPE ABUTMENT ;
    PORT
      LAYER M3 ;
      RECT 3.231 146.827 3.249 146.881 ;
    END
  END rw0_rd_out[122]
  PIN rw0_rd_out[123]
    DIRECTION OUTPUT ;
    USE SIGNAL ;
    SHAPE ABUTMENT ;
    PORT
      LAYER M3 ;
      RECT 3.663 146.827 3.681 146.881 ;
    END
  END rw0_rd_out[123]
  PIN rw0_rd_out[124]
    DIRECTION OUTPUT ;
    USE SIGNAL ;
    SHAPE ABUTMENT ;
    PORT
      LAYER M3 ;
      RECT 4.095 146.827 4.113 146.881 ;
    END
  END rw0_rd_out[124]
  PIN rw0_rd_out[125]
    DIRECTION OUTPUT ;
    USE SIGNAL ;
    SHAPE ABUTMENT ;
    PORT
      LAYER M3 ;
      RECT 4.527 146.827 4.545 146.881 ;
    END
  END rw0_rd_out[125]
  PIN rw0_rd_out[126]
    DIRECTION OUTPUT ;
    USE SIGNAL ;
    SHAPE ABUTMENT ;
    PORT
      LAYER M3 ;
      RECT 4.959 146.827 4.977 146.881 ;
    END
  END rw0_rd_out[126]
  PIN rw0_rd_out[127]
    DIRECTION OUTPUT ;
    USE SIGNAL ;
    SHAPE ABUTMENT ;
    PORT
      LAYER M3 ;
      RECT 5.391 146.827 5.409 146.881 ;
    END
  END rw0_rd_out[127]
  PIN rw0_rd_out[128]
    DIRECTION OUTPUT ;
    USE SIGNAL ;
    SHAPE ABUTMENT ;
    PORT
      LAYER M3 ;
      RECT 5.823 146.827 5.841 146.881 ;
    END
  END rw0_rd_out[128]
  PIN rw0_rd_out[129]
    DIRECTION OUTPUT ;
    USE SIGNAL ;
    SHAPE ABUTMENT ;
    PORT
      LAYER M3 ;
      RECT 6.255 146.827 6.273 146.881 ;
    END
  END rw0_rd_out[129]
  PIN rw0_rd_out[130]
    DIRECTION OUTPUT ;
    USE SIGNAL ;
    SHAPE ABUTMENT ;
    PORT
      LAYER M3 ;
      RECT 6.687 146.827 6.705 146.881 ;
    END
  END rw0_rd_out[130]
  PIN rw0_rd_out[131]
    DIRECTION OUTPUT ;
    USE SIGNAL ;
    SHAPE ABUTMENT ;
    PORT
      LAYER M3 ;
      RECT 7.119 146.827 7.137 146.881 ;
    END
  END rw0_rd_out[131]
  PIN rw0_rd_out[132]
    DIRECTION OUTPUT ;
    USE SIGNAL ;
    SHAPE ABUTMENT ;
    PORT
      LAYER M3 ;
      RECT 7.551 146.827 7.569 146.881 ;
    END
  END rw0_rd_out[132]
  PIN rw0_rd_out[133]
    DIRECTION OUTPUT ;
    USE SIGNAL ;
    SHAPE ABUTMENT ;
    PORT
      LAYER M3 ;
      RECT 7.983 146.827 8.001 146.881 ;
    END
  END rw0_rd_out[133]
  PIN rw0_rd_out[134]
    DIRECTION OUTPUT ;
    USE SIGNAL ;
    SHAPE ABUTMENT ;
    PORT
      LAYER M3 ;
      RECT 8.415 146.827 8.433 146.881 ;
    END
  END rw0_rd_out[134]
  PIN rw0_rd_out[135]
    DIRECTION OUTPUT ;
    USE SIGNAL ;
    SHAPE ABUTMENT ;
    PORT
      LAYER M3 ;
      RECT 8.847 146.827 8.865 146.881 ;
    END
  END rw0_rd_out[135]
  PIN rw0_rd_out[136]
    DIRECTION OUTPUT ;
    USE SIGNAL ;
    SHAPE ABUTMENT ;
    PORT
      LAYER M3 ;
      RECT 9.279 146.827 9.297 146.881 ;
    END
  END rw0_rd_out[136]
  PIN rw0_rd_out[137]
    DIRECTION OUTPUT ;
    USE SIGNAL ;
    SHAPE ABUTMENT ;
    PORT
      LAYER M3 ;
      RECT 9.711 146.827 9.729 146.881 ;
    END
  END rw0_rd_out[137]
  PIN rw0_rd_out[138]
    DIRECTION OUTPUT ;
    USE SIGNAL ;
    SHAPE ABUTMENT ;
    PORT
      LAYER M3 ;
      RECT 10.143 146.827 10.161 146.881 ;
    END
  END rw0_rd_out[138]
  PIN rw0_rd_out[139]
    DIRECTION OUTPUT ;
    USE SIGNAL ;
    SHAPE ABUTMENT ;
    PORT
      LAYER M3 ;
      RECT 10.575 146.827 10.593 146.881 ;
    END
  END rw0_rd_out[139]
  PIN rw0_rd_out[140]
    DIRECTION OUTPUT ;
    USE SIGNAL ;
    SHAPE ABUTMENT ;
    PORT
      LAYER M3 ;
      RECT 11.007 146.827 11.025 146.881 ;
    END
  END rw0_rd_out[140]
  PIN rw0_rd_out[141]
    DIRECTION OUTPUT ;
    USE SIGNAL ;
    SHAPE ABUTMENT ;
    PORT
      LAYER M3 ;
      RECT 11.439 146.827 11.457 146.881 ;
    END
  END rw0_rd_out[141]
  PIN rw0_rd_out[142]
    DIRECTION OUTPUT ;
    USE SIGNAL ;
    SHAPE ABUTMENT ;
    PORT
      LAYER M3 ;
      RECT 11.871 146.827 11.889 146.881 ;
    END
  END rw0_rd_out[142]
  PIN rw0_rd_out[143]
    DIRECTION OUTPUT ;
    USE SIGNAL ;
    SHAPE ABUTMENT ;
    PORT
      LAYER M3 ;
      RECT 12.303 146.827 12.321 146.881 ;
    END
  END rw0_rd_out[143]
  PIN rw0_rd_out[144]
    DIRECTION OUTPUT ;
    USE SIGNAL ;
    SHAPE ABUTMENT ;
    PORT
      LAYER M3 ;
      RECT 12.735 146.827 12.753 146.881 ;
    END
  END rw0_rd_out[144]
  PIN rw0_rd_out[145]
    DIRECTION OUTPUT ;
    USE SIGNAL ;
    SHAPE ABUTMENT ;
    PORT
      LAYER M3 ;
      RECT 13.167 146.827 13.185 146.881 ;
    END
  END rw0_rd_out[145]
  PIN rw0_rd_out[146]
    DIRECTION OUTPUT ;
    USE SIGNAL ;
    SHAPE ABUTMENT ;
    PORT
      LAYER M3 ;
      RECT 13.599 146.827 13.617 146.881 ;
    END
  END rw0_rd_out[146]
  PIN rw0_rd_out[147]
    DIRECTION OUTPUT ;
    USE SIGNAL ;
    SHAPE ABUTMENT ;
    PORT
      LAYER M3 ;
      RECT 14.031 146.827 14.049 146.881 ;
    END
  END rw0_rd_out[147]
  PIN rw0_rd_out[148]
    DIRECTION OUTPUT ;
    USE SIGNAL ;
    SHAPE ABUTMENT ;
    PORT
      LAYER M3 ;
      RECT 14.463 146.827 14.481 146.881 ;
    END
  END rw0_rd_out[148]
  PIN rw0_rd_out[149]
    DIRECTION OUTPUT ;
    USE SIGNAL ;
    SHAPE ABUTMENT ;
    PORT
      LAYER M3 ;
      RECT 14.895 146.827 14.913 146.881 ;
    END
  END rw0_rd_out[149]
  PIN rw0_rd_out[150]
    DIRECTION OUTPUT ;
    USE SIGNAL ;
    SHAPE ABUTMENT ;
    PORT
      LAYER M3 ;
      RECT 15.327 146.827 15.345 146.881 ;
    END
  END rw0_rd_out[150]
  PIN rw0_rd_out[151]
    DIRECTION OUTPUT ;
    USE SIGNAL ;
    SHAPE ABUTMENT ;
    PORT
      LAYER M3 ;
      RECT 15.759 146.827 15.777 146.881 ;
    END
  END rw0_rd_out[151]
  PIN rw0_rd_out[152]
    DIRECTION OUTPUT ;
    USE SIGNAL ;
    SHAPE ABUTMENT ;
    PORT
      LAYER M3 ;
      RECT 16.191 146.827 16.209 146.881 ;
    END
  END rw0_rd_out[152]
  PIN rw0_rd_out[153]
    DIRECTION OUTPUT ;
    USE SIGNAL ;
    SHAPE ABUTMENT ;
    PORT
      LAYER M3 ;
      RECT 16.623 146.827 16.641 146.881 ;
    END
  END rw0_rd_out[153]
  PIN rw0_rd_out[154]
    DIRECTION OUTPUT ;
    USE SIGNAL ;
    SHAPE ABUTMENT ;
    PORT
      LAYER M3 ;
      RECT 17.055 146.827 17.073 146.881 ;
    END
  END rw0_rd_out[154]
  PIN rw0_rd_out[155]
    DIRECTION OUTPUT ;
    USE SIGNAL ;
    SHAPE ABUTMENT ;
    PORT
      LAYER M3 ;
      RECT 17.487 146.827 17.505 146.881 ;
    END
  END rw0_rd_out[155]
  PIN rw0_rd_out[156]
    DIRECTION OUTPUT ;
    USE SIGNAL ;
    SHAPE ABUTMENT ;
    PORT
      LAYER M3 ;
      RECT 17.919 146.827 17.937 146.881 ;
    END
  END rw0_rd_out[156]
  PIN rw0_rd_out[157]
    DIRECTION OUTPUT ;
    USE SIGNAL ;
    SHAPE ABUTMENT ;
    PORT
      LAYER M3 ;
      RECT 18.351 146.827 18.369 146.881 ;
    END
  END rw0_rd_out[157]
  PIN rw0_rd_out[158]
    DIRECTION OUTPUT ;
    USE SIGNAL ;
    SHAPE ABUTMENT ;
    PORT
      LAYER M3 ;
      RECT 18.783 146.827 18.801 146.881 ;
    END
  END rw0_rd_out[158]
  PIN rw0_rd_out[159]
    DIRECTION OUTPUT ;
    USE SIGNAL ;
    SHAPE ABUTMENT ;
    PORT
      LAYER M3 ;
      RECT 19.215 146.827 19.233 146.881 ;
    END
  END rw0_rd_out[159]
  PIN rw0_rd_out[160]
    DIRECTION OUTPUT ;
    USE SIGNAL ;
    SHAPE ABUTMENT ;
    PORT
      LAYER M3 ;
      RECT 19.647 146.827 19.665 146.881 ;
    END
  END rw0_rd_out[160]
  PIN rw0_rd_out[161]
    DIRECTION OUTPUT ;
    USE SIGNAL ;
    SHAPE ABUTMENT ;
    PORT
      LAYER M3 ;
      RECT 20.079 146.827 20.097 146.881 ;
    END
  END rw0_rd_out[161]
  PIN rw0_rd_out[162]
    DIRECTION OUTPUT ;
    USE SIGNAL ;
    SHAPE ABUTMENT ;
    PORT
      LAYER M3 ;
      RECT 20.511 146.827 20.529 146.881 ;
    END
  END rw0_rd_out[162]
  PIN rw0_rd_out[163]
    DIRECTION OUTPUT ;
    USE SIGNAL ;
    SHAPE ABUTMENT ;
    PORT
      LAYER M3 ;
      RECT 20.943 146.827 20.961 146.881 ;
    END
  END rw0_rd_out[163]
  PIN rw0_rd_out[164]
    DIRECTION OUTPUT ;
    USE SIGNAL ;
    SHAPE ABUTMENT ;
    PORT
      LAYER M3 ;
      RECT 21.375 146.827 21.393 146.881 ;
    END
  END rw0_rd_out[164]
  PIN rw0_rd_out[165]
    DIRECTION OUTPUT ;
    USE SIGNAL ;
    SHAPE ABUTMENT ;
    PORT
      LAYER M3 ;
      RECT 21.807 146.827 21.825 146.881 ;
    END
  END rw0_rd_out[165]
  PIN rw0_rd_out[166]
    DIRECTION OUTPUT ;
    USE SIGNAL ;
    SHAPE ABUTMENT ;
    PORT
      LAYER M3 ;
      RECT 22.239 146.827 22.257 146.881 ;
    END
  END rw0_rd_out[166]
  PIN rw0_rd_out[167]
    DIRECTION OUTPUT ;
    USE SIGNAL ;
    SHAPE ABUTMENT ;
    PORT
      LAYER M3 ;
      RECT 22.671 146.827 22.689 146.881 ;
    END
  END rw0_rd_out[167]
  PIN rw0_rd_out[168]
    DIRECTION OUTPUT ;
    USE SIGNAL ;
    SHAPE ABUTMENT ;
    PORT
      LAYER M3 ;
      RECT 23.103 146.827 23.121 146.881 ;
    END
  END rw0_rd_out[168]
  PIN rw0_rd_out[169]
    DIRECTION OUTPUT ;
    USE SIGNAL ;
    SHAPE ABUTMENT ;
    PORT
      LAYER M3 ;
      RECT 23.535 146.827 23.553 146.881 ;
    END
  END rw0_rd_out[169]
  PIN rw0_rd_out[170]
    DIRECTION OUTPUT ;
    USE SIGNAL ;
    SHAPE ABUTMENT ;
    PORT
      LAYER M3 ;
      RECT 23.967 146.827 23.985 146.881 ;
    END
  END rw0_rd_out[170]
  PIN rw0_rd_out[171]
    DIRECTION OUTPUT ;
    USE SIGNAL ;
    SHAPE ABUTMENT ;
    PORT
      LAYER M3 ;
      RECT 24.399 146.827 24.417 146.881 ;
    END
  END rw0_rd_out[171]
  PIN rw0_rd_out[172]
    DIRECTION OUTPUT ;
    USE SIGNAL ;
    SHAPE ABUTMENT ;
    PORT
      LAYER M3 ;
      RECT 24.831 146.827 24.849 146.881 ;
    END
  END rw0_rd_out[172]
  PIN rw0_rd_out[173]
    DIRECTION OUTPUT ;
    USE SIGNAL ;
    SHAPE ABUTMENT ;
    PORT
      LAYER M3 ;
      RECT 25.263 146.827 25.281 146.881 ;
    END
  END rw0_rd_out[173]
  PIN rw0_rd_out[174]
    DIRECTION OUTPUT ;
    USE SIGNAL ;
    SHAPE ABUTMENT ;
    PORT
      LAYER M3 ;
      RECT 25.695 146.827 25.713 146.881 ;
    END
  END rw0_rd_out[174]
  PIN rw0_rd_out[175]
    DIRECTION OUTPUT ;
    USE SIGNAL ;
    SHAPE ABUTMENT ;
    PORT
      LAYER M3 ;
      RECT 26.127 146.827 26.145 146.881 ;
    END
  END rw0_rd_out[175]
  PIN rw0_rd_out[176]
    DIRECTION OUTPUT ;
    USE SIGNAL ;
    SHAPE ABUTMENT ;
    PORT
      LAYER M3 ;
      RECT 26.559 146.827 26.577 146.881 ;
    END
  END rw0_rd_out[176]
  PIN rw0_rd_out[177]
    DIRECTION OUTPUT ;
    USE SIGNAL ;
    SHAPE ABUTMENT ;
    PORT
      LAYER M3 ;
      RECT 26.991 146.827 27.009 146.881 ;
    END
  END rw0_rd_out[177]
  PIN rw0_rd_out[178]
    DIRECTION OUTPUT ;
    USE SIGNAL ;
    SHAPE ABUTMENT ;
    PORT
      LAYER M3 ;
      RECT 27.423 146.827 27.441 146.881 ;
    END
  END rw0_rd_out[178]
  PIN rw0_rd_out[179]
    DIRECTION OUTPUT ;
    USE SIGNAL ;
    SHAPE ABUTMENT ;
    PORT
      LAYER M3 ;
      RECT 27.855 146.827 27.873 146.881 ;
    END
  END rw0_rd_out[179]
  PIN rw0_rd_out[180]
    DIRECTION OUTPUT ;
    USE SIGNAL ;
    SHAPE ABUTMENT ;
    PORT
      LAYER M3 ;
      RECT 28.287 146.827 28.305 146.881 ;
    END
  END rw0_rd_out[180]
  PIN rw0_rd_out[181]
    DIRECTION OUTPUT ;
    USE SIGNAL ;
    SHAPE ABUTMENT ;
    PORT
      LAYER M3 ;
      RECT 28.719 146.827 28.737 146.881 ;
    END
  END rw0_rd_out[181]
  PIN rw0_rd_out[182]
    DIRECTION OUTPUT ;
    USE SIGNAL ;
    SHAPE ABUTMENT ;
    PORT
      LAYER M3 ;
      RECT 29.151 146.827 29.169 146.881 ;
    END
  END rw0_rd_out[182]
  PIN rw0_rd_out[183]
    DIRECTION OUTPUT ;
    USE SIGNAL ;
    SHAPE ABUTMENT ;
    PORT
      LAYER M3 ;
      RECT 29.583 146.827 29.601 146.881 ;
    END
  END rw0_rd_out[183]
  PIN rw0_rd_out[184]
    DIRECTION OUTPUT ;
    USE SIGNAL ;
    SHAPE ABUTMENT ;
    PORT
      LAYER M3 ;
      RECT 30.015 146.827 30.033 146.881 ;
    END
  END rw0_rd_out[184]
  PIN rw0_rd_out[185]
    DIRECTION OUTPUT ;
    USE SIGNAL ;
    SHAPE ABUTMENT ;
    PORT
      LAYER M3 ;
      RECT 30.447 146.827 30.465 146.881 ;
    END
  END rw0_rd_out[185]
  PIN rw0_rd_out[186]
    DIRECTION OUTPUT ;
    USE SIGNAL ;
    SHAPE ABUTMENT ;
    PORT
      LAYER M3 ;
      RECT 30.879 146.827 30.897 146.881 ;
    END
  END rw0_rd_out[186]
  PIN rw0_rd_out[187]
    DIRECTION OUTPUT ;
    USE SIGNAL ;
    SHAPE ABUTMENT ;
    PORT
      LAYER M3 ;
      RECT 31.311 146.827 31.329 146.881 ;
    END
  END rw0_rd_out[187]
  PIN rw0_rd_out[188]
    DIRECTION OUTPUT ;
    USE SIGNAL ;
    SHAPE ABUTMENT ;
    PORT
      LAYER M3 ;
      RECT 31.743 146.827 31.761 146.881 ;
    END
  END rw0_rd_out[188]
  PIN rw0_rd_out[189]
    DIRECTION OUTPUT ;
    USE SIGNAL ;
    SHAPE ABUTMENT ;
    PORT
      LAYER M3 ;
      RECT 32.175 146.827 32.193 146.881 ;
    END
  END rw0_rd_out[189]
  PIN rw0_rd_out[190]
    DIRECTION OUTPUT ;
    USE SIGNAL ;
    SHAPE ABUTMENT ;
    PORT
      LAYER M3 ;
      RECT 32.607 146.827 32.625 146.881 ;
    END
  END rw0_rd_out[190]
  PIN rw0_rd_out[191]
    DIRECTION OUTPUT ;
    USE SIGNAL ;
    SHAPE ABUTMENT ;
    PORT
      LAYER M3 ;
      RECT 33.039 146.827 33.057 146.881 ;
    END
  END rw0_rd_out[191]
  PIN rw0_rd_out[192]
    DIRECTION OUTPUT ;
    USE SIGNAL ;
    SHAPE ABUTMENT ;
    PORT
      LAYER M3 ;
      RECT 33.471 146.827 33.489 146.881 ;
    END
  END rw0_rd_out[192]
  PIN rw0_rd_out[193]
    DIRECTION OUTPUT ;
    USE SIGNAL ;
    SHAPE ABUTMENT ;
    PORT
      LAYER M3 ;
      RECT 33.903 146.827 33.921 146.881 ;
    END
  END rw0_rd_out[193]
  PIN rw0_rd_out[194]
    DIRECTION OUTPUT ;
    USE SIGNAL ;
    SHAPE ABUTMENT ;
    PORT
      LAYER M3 ;
      RECT 34.335 146.827 34.353 146.881 ;
    END
  END rw0_rd_out[194]
  PIN rw0_rd_out[195]
    DIRECTION OUTPUT ;
    USE SIGNAL ;
    SHAPE ABUTMENT ;
    PORT
      LAYER M3 ;
      RECT 34.767 146.827 34.785 146.881 ;
    END
  END rw0_rd_out[195]
  PIN rw0_rd_out[196]
    DIRECTION OUTPUT ;
    USE SIGNAL ;
    SHAPE ABUTMENT ;
    PORT
      LAYER M3 ;
      RECT 35.199 146.827 35.217 146.881 ;
    END
  END rw0_rd_out[196]
  PIN rw0_rd_out[197]
    DIRECTION OUTPUT ;
    USE SIGNAL ;
    SHAPE ABUTMENT ;
    PORT
      LAYER M3 ;
      RECT 35.631 146.827 35.649 146.881 ;
    END
  END rw0_rd_out[197]
  PIN rw0_rd_out[198]
    DIRECTION OUTPUT ;
    USE SIGNAL ;
    SHAPE ABUTMENT ;
    PORT
      LAYER M3 ;
      RECT 36.063 146.827 36.081 146.881 ;
    END
  END rw0_rd_out[198]
  PIN rw0_rd_out[199]
    DIRECTION OUTPUT ;
    USE SIGNAL ;
    SHAPE ABUTMENT ;
    PORT
      LAYER M3 ;
      RECT 36.495 146.827 36.513 146.881 ;
    END
  END rw0_rd_out[199]
  PIN rw0_rd_out[200]
    DIRECTION OUTPUT ;
    USE SIGNAL ;
    SHAPE ABUTMENT ;
    PORT
      LAYER M3 ;
      RECT 36.927 146.827 36.945 146.881 ;
    END
  END rw0_rd_out[200]
  PIN rw0_rd_out[201]
    DIRECTION OUTPUT ;
    USE SIGNAL ;
    SHAPE ABUTMENT ;
    PORT
      LAYER M3 ;
      RECT 37.359 146.827 37.377 146.881 ;
    END
  END rw0_rd_out[201]
  PIN rw0_rd_out[202]
    DIRECTION OUTPUT ;
    USE SIGNAL ;
    SHAPE ABUTMENT ;
    PORT
      LAYER M3 ;
      RECT 37.791 146.827 37.809 146.881 ;
    END
  END rw0_rd_out[202]
  PIN rw0_rd_out[203]
    DIRECTION OUTPUT ;
    USE SIGNAL ;
    SHAPE ABUTMENT ;
    PORT
      LAYER M3 ;
      RECT 38.223 146.827 38.241 146.881 ;
    END
  END rw0_rd_out[203]
  PIN rw0_rd_out[204]
    DIRECTION OUTPUT ;
    USE SIGNAL ;
    SHAPE ABUTMENT ;
    PORT
      LAYER M3 ;
      RECT 38.655 146.827 38.673 146.881 ;
    END
  END rw0_rd_out[204]
  PIN rw0_rd_out[205]
    DIRECTION OUTPUT ;
    USE SIGNAL ;
    SHAPE ABUTMENT ;
    PORT
      LAYER M3 ;
      RECT 39.087 146.827 39.105 146.881 ;
    END
  END rw0_rd_out[205]
  PIN rw0_rd_out[206]
    DIRECTION OUTPUT ;
    USE SIGNAL ;
    SHAPE ABUTMENT ;
    PORT
      LAYER M3 ;
      RECT 39.519 146.827 39.537 146.881 ;
    END
  END rw0_rd_out[206]
  PIN rw0_rd_out[207]
    DIRECTION OUTPUT ;
    USE SIGNAL ;
    SHAPE ABUTMENT ;
    PORT
      LAYER M3 ;
      RECT 39.951 146.827 39.969 146.881 ;
    END
  END rw0_rd_out[207]
  PIN rw0_rd_out[208]
    DIRECTION OUTPUT ;
    USE SIGNAL ;
    SHAPE ABUTMENT ;
    PORT
      LAYER M3 ;
      RECT 40.383 146.827 40.401 146.881 ;
    END
  END rw0_rd_out[208]
  PIN rw0_rd_out[209]
    DIRECTION OUTPUT ;
    USE SIGNAL ;
    SHAPE ABUTMENT ;
    PORT
      LAYER M3 ;
      RECT 40.815 146.827 40.833 146.881 ;
    END
  END rw0_rd_out[209]
  PIN rw0_rd_out[210]
    DIRECTION OUTPUT ;
    USE SIGNAL ;
    SHAPE ABUTMENT ;
    PORT
      LAYER M3 ;
      RECT 41.247 146.827 41.265 146.881 ;
    END
  END rw0_rd_out[210]
  PIN rw0_rd_out[211]
    DIRECTION OUTPUT ;
    USE SIGNAL ;
    SHAPE ABUTMENT ;
    PORT
      LAYER M3 ;
      RECT 41.679 146.827 41.697 146.881 ;
    END
  END rw0_rd_out[211]
  PIN rw0_rd_out[212]
    DIRECTION OUTPUT ;
    USE SIGNAL ;
    SHAPE ABUTMENT ;
    PORT
      LAYER M3 ;
      RECT 42.111 146.827 42.129 146.881 ;
    END
  END rw0_rd_out[212]
  PIN rw0_rd_out[213]
    DIRECTION OUTPUT ;
    USE SIGNAL ;
    SHAPE ABUTMENT ;
    PORT
      LAYER M3 ;
      RECT 42.543 146.827 42.561 146.881 ;
    END
  END rw0_rd_out[213]
  PIN rw0_rd_out[214]
    DIRECTION OUTPUT ;
    USE SIGNAL ;
    SHAPE ABUTMENT ;
    PORT
      LAYER M3 ;
      RECT 42.975 146.827 42.993 146.881 ;
    END
  END rw0_rd_out[214]
  PIN rw0_rd_out[215]
    DIRECTION OUTPUT ;
    USE SIGNAL ;
    SHAPE ABUTMENT ;
    PORT
      LAYER M3 ;
      RECT 43.407 146.827 43.425 146.881 ;
    END
  END rw0_rd_out[215]
  PIN rw0_rd_out[216]
    DIRECTION OUTPUT ;
    USE SIGNAL ;
    SHAPE ABUTMENT ;
    PORT
      LAYER M3 ;
      RECT 43.839 146.827 43.857 146.881 ;
    END
  END rw0_rd_out[216]
  PIN rw0_rd_out[217]
    DIRECTION OUTPUT ;
    USE SIGNAL ;
    SHAPE ABUTMENT ;
    PORT
      LAYER M3 ;
      RECT 44.271 146.827 44.289 146.881 ;
    END
  END rw0_rd_out[217]
  PIN rw0_rd_out[218]
    DIRECTION OUTPUT ;
    USE SIGNAL ;
    SHAPE ABUTMENT ;
    PORT
      LAYER M3 ;
      RECT 44.703 146.827 44.721 146.881 ;
    END
  END rw0_rd_out[218]
  PIN rw0_rd_out[219]
    DIRECTION OUTPUT ;
    USE SIGNAL ;
    SHAPE ABUTMENT ;
    PORT
      LAYER M3 ;
      RECT 45.135 146.827 45.153 146.881 ;
    END
  END rw0_rd_out[219]
  PIN rw0_rd_out[220]
    DIRECTION OUTPUT ;
    USE SIGNAL ;
    SHAPE ABUTMENT ;
    PORT
      LAYER M3 ;
      RECT 45.567 146.827 45.585 146.881 ;
    END
  END rw0_rd_out[220]
  PIN rw0_rd_out[221]
    DIRECTION OUTPUT ;
    USE SIGNAL ;
    SHAPE ABUTMENT ;
    PORT
      LAYER M3 ;
      RECT 45.999 146.827 46.017 146.881 ;
    END
  END rw0_rd_out[221]
  PIN rw0_rd_out[222]
    DIRECTION OUTPUT ;
    USE SIGNAL ;
    SHAPE ABUTMENT ;
    PORT
      LAYER M3 ;
      RECT 46.431 146.827 46.449 146.881 ;
    END
  END rw0_rd_out[222]
  PIN rw0_rd_out[223]
    DIRECTION OUTPUT ;
    USE SIGNAL ;
    SHAPE ABUTMENT ;
    PORT
      LAYER M3 ;
      RECT 46.863 146.827 46.881 146.881 ;
    END
  END rw0_rd_out[223]
  PIN rw0_rd_out[224]
    DIRECTION OUTPUT ;
    USE SIGNAL ;
    SHAPE ABUTMENT ;
    PORT
      LAYER M3 ;
      RECT 47.295 146.827 47.313 146.881 ;
    END
  END rw0_rd_out[224]
  PIN rw0_rd_out[225]
    DIRECTION OUTPUT ;
    USE SIGNAL ;
    SHAPE ABUTMENT ;
    PORT
      LAYER M3 ;
      RECT 47.727 146.827 47.745 146.881 ;
    END
  END rw0_rd_out[225]
  PIN rw0_rd_out[226]
    DIRECTION OUTPUT ;
    USE SIGNAL ;
    SHAPE ABUTMENT ;
    PORT
      LAYER M3 ;
      RECT 48.159 146.827 48.177 146.881 ;
    END
  END rw0_rd_out[226]
  PIN rw0_rd_out[227]
    DIRECTION OUTPUT ;
    USE SIGNAL ;
    SHAPE ABUTMENT ;
    PORT
      LAYER M3 ;
      RECT 48.591 146.827 48.609 146.881 ;
    END
  END rw0_rd_out[227]
  PIN rw0_rd_out[228]
    DIRECTION OUTPUT ;
    USE SIGNAL ;
    SHAPE ABUTMENT ;
    PORT
      LAYER M3 ;
      RECT 49.023 146.827 49.041 146.881 ;
    END
  END rw0_rd_out[228]
  PIN rw0_rd_out[229]
    DIRECTION OUTPUT ;
    USE SIGNAL ;
    SHAPE ABUTMENT ;
    PORT
      LAYER M3 ;
      RECT 49.455 146.827 49.473 146.881 ;
    END
  END rw0_rd_out[229]
  PIN r0_rd_out[0]
    DIRECTION OUTPUT ;
    USE SIGNAL ;
    SHAPE ABUTMENT ;
    PORT
      LAYER M3 ;
      RECT 66.447 0.000 66.465 0.054 ;
    END
  END r0_rd_out[0]
  PIN r0_rd_out[1]
    DIRECTION OUTPUT ;
    USE SIGNAL ;
    SHAPE ABUTMENT ;
    PORT
      LAYER M3 ;
      RECT 66.735 0.000 66.753 0.054 ;
    END
  END r0_rd_out[1]
  PIN r0_rd_out[2]
    DIRECTION OUTPUT ;
    USE SIGNAL ;
    SHAPE ABUTMENT ;
    PORT
      LAYER M3 ;
      RECT 67.023 0.000 67.041 0.054 ;
    END
  END r0_rd_out[2]
  PIN r0_rd_out[3]
    DIRECTION OUTPUT ;
    USE SIGNAL ;
    SHAPE ABUTMENT ;
    PORT
      LAYER M3 ;
      RECT 67.311 0.000 67.329 0.054 ;
    END
  END r0_rd_out[3]
  PIN r0_rd_out[4]
    DIRECTION OUTPUT ;
    USE SIGNAL ;
    SHAPE ABUTMENT ;
    PORT
      LAYER M3 ;
      RECT 67.599 0.000 67.617 0.054 ;
    END
  END r0_rd_out[4]
  PIN r0_rd_out[5]
    DIRECTION OUTPUT ;
    USE SIGNAL ;
    SHAPE ABUTMENT ;
    PORT
      LAYER M3 ;
      RECT 67.887 0.000 67.905 0.054 ;
    END
  END r0_rd_out[5]
  PIN r0_rd_out[6]
    DIRECTION OUTPUT ;
    USE SIGNAL ;
    SHAPE ABUTMENT ;
    PORT
      LAYER M3 ;
      RECT 68.175 0.000 68.193 0.054 ;
    END
  END r0_rd_out[6]
  PIN r0_rd_out[7]
    DIRECTION OUTPUT ;
    USE SIGNAL ;
    SHAPE ABUTMENT ;
    PORT
      LAYER M3 ;
      RECT 68.463 0.000 68.481 0.054 ;
    END
  END r0_rd_out[7]
  PIN r0_rd_out[8]
    DIRECTION OUTPUT ;
    USE SIGNAL ;
    SHAPE ABUTMENT ;
    PORT
      LAYER M3 ;
      RECT 68.751 0.000 68.769 0.054 ;
    END
  END r0_rd_out[8]
  PIN r0_rd_out[9]
    DIRECTION OUTPUT ;
    USE SIGNAL ;
    SHAPE ABUTMENT ;
    PORT
      LAYER M3 ;
      RECT 69.039 0.000 69.057 0.054 ;
    END
  END r0_rd_out[9]
  PIN r0_rd_out[10]
    DIRECTION OUTPUT ;
    USE SIGNAL ;
    SHAPE ABUTMENT ;
    PORT
      LAYER M3 ;
      RECT 69.327 0.000 69.345 0.054 ;
    END
  END r0_rd_out[10]
  PIN r0_rd_out[11]
    DIRECTION OUTPUT ;
    USE SIGNAL ;
    SHAPE ABUTMENT ;
    PORT
      LAYER M3 ;
      RECT 69.615 0.000 69.633 0.054 ;
    END
  END r0_rd_out[11]
  PIN r0_rd_out[12]
    DIRECTION OUTPUT ;
    USE SIGNAL ;
    SHAPE ABUTMENT ;
    PORT
      LAYER M3 ;
      RECT 69.903 0.000 69.921 0.054 ;
    END
  END r0_rd_out[12]
  PIN r0_rd_out[13]
    DIRECTION OUTPUT ;
    USE SIGNAL ;
    SHAPE ABUTMENT ;
    PORT
      LAYER M3 ;
      RECT 70.191 0.000 70.209 0.054 ;
    END
  END r0_rd_out[13]
  PIN r0_rd_out[14]
    DIRECTION OUTPUT ;
    USE SIGNAL ;
    SHAPE ABUTMENT ;
    PORT
      LAYER M3 ;
      RECT 70.479 0.000 70.497 0.054 ;
    END
  END r0_rd_out[14]
  PIN r0_rd_out[15]
    DIRECTION OUTPUT ;
    USE SIGNAL ;
    SHAPE ABUTMENT ;
    PORT
      LAYER M3 ;
      RECT 70.767 0.000 70.785 0.054 ;
    END
  END r0_rd_out[15]
  PIN r0_rd_out[16]
    DIRECTION OUTPUT ;
    USE SIGNAL ;
    SHAPE ABUTMENT ;
    PORT
      LAYER M3 ;
      RECT 71.055 0.000 71.073 0.054 ;
    END
  END r0_rd_out[16]
  PIN r0_rd_out[17]
    DIRECTION OUTPUT ;
    USE SIGNAL ;
    SHAPE ABUTMENT ;
    PORT
      LAYER M3 ;
      RECT 71.343 0.000 71.361 0.054 ;
    END
  END r0_rd_out[17]
  PIN r0_rd_out[18]
    DIRECTION OUTPUT ;
    USE SIGNAL ;
    SHAPE ABUTMENT ;
    PORT
      LAYER M3 ;
      RECT 71.631 0.000 71.649 0.054 ;
    END
  END r0_rd_out[18]
  PIN r0_rd_out[19]
    DIRECTION OUTPUT ;
    USE SIGNAL ;
    SHAPE ABUTMENT ;
    PORT
      LAYER M3 ;
      RECT 71.919 0.000 71.937 0.054 ;
    END
  END r0_rd_out[19]
  PIN r0_rd_out[20]
    DIRECTION OUTPUT ;
    USE SIGNAL ;
    SHAPE ABUTMENT ;
    PORT
      LAYER M3 ;
      RECT 72.207 0.000 72.225 0.054 ;
    END
  END r0_rd_out[20]
  PIN r0_rd_out[21]
    DIRECTION OUTPUT ;
    USE SIGNAL ;
    SHAPE ABUTMENT ;
    PORT
      LAYER M3 ;
      RECT 72.495 0.000 72.513 0.054 ;
    END
  END r0_rd_out[21]
  PIN r0_rd_out[22]
    DIRECTION OUTPUT ;
    USE SIGNAL ;
    SHAPE ABUTMENT ;
    PORT
      LAYER M3 ;
      RECT 72.783 0.000 72.801 0.054 ;
    END
  END r0_rd_out[22]
  PIN r0_rd_out[23]
    DIRECTION OUTPUT ;
    USE SIGNAL ;
    SHAPE ABUTMENT ;
    PORT
      LAYER M3 ;
      RECT 73.071 0.000 73.089 0.054 ;
    END
  END r0_rd_out[23]
  PIN r0_rd_out[24]
    DIRECTION OUTPUT ;
    USE SIGNAL ;
    SHAPE ABUTMENT ;
    PORT
      LAYER M3 ;
      RECT 73.359 0.000 73.377 0.054 ;
    END
  END r0_rd_out[24]
  PIN r0_rd_out[25]
    DIRECTION OUTPUT ;
    USE SIGNAL ;
    SHAPE ABUTMENT ;
    PORT
      LAYER M3 ;
      RECT 73.647 0.000 73.665 0.054 ;
    END
  END r0_rd_out[25]
  PIN r0_rd_out[26]
    DIRECTION OUTPUT ;
    USE SIGNAL ;
    SHAPE ABUTMENT ;
    PORT
      LAYER M3 ;
      RECT 73.935 0.000 73.953 0.054 ;
    END
  END r0_rd_out[26]
  PIN r0_rd_out[27]
    DIRECTION OUTPUT ;
    USE SIGNAL ;
    SHAPE ABUTMENT ;
    PORT
      LAYER M3 ;
      RECT 74.223 0.000 74.241 0.054 ;
    END
  END r0_rd_out[27]
  PIN r0_rd_out[28]
    DIRECTION OUTPUT ;
    USE SIGNAL ;
    SHAPE ABUTMENT ;
    PORT
      LAYER M3 ;
      RECT 74.511 0.000 74.529 0.054 ;
    END
  END r0_rd_out[28]
  PIN r0_rd_out[29]
    DIRECTION OUTPUT ;
    USE SIGNAL ;
    SHAPE ABUTMENT ;
    PORT
      LAYER M3 ;
      RECT 74.799 0.000 74.817 0.054 ;
    END
  END r0_rd_out[29]
  PIN r0_rd_out[30]
    DIRECTION OUTPUT ;
    USE SIGNAL ;
    SHAPE ABUTMENT ;
    PORT
      LAYER M3 ;
      RECT 75.087 0.000 75.105 0.054 ;
    END
  END r0_rd_out[30]
  PIN r0_rd_out[31]
    DIRECTION OUTPUT ;
    USE SIGNAL ;
    SHAPE ABUTMENT ;
    PORT
      LAYER M3 ;
      RECT 75.375 0.000 75.393 0.054 ;
    END
  END r0_rd_out[31]
  PIN r0_rd_out[32]
    DIRECTION OUTPUT ;
    USE SIGNAL ;
    SHAPE ABUTMENT ;
    PORT
      LAYER M3 ;
      RECT 75.663 0.000 75.681 0.054 ;
    END
  END r0_rd_out[32]
  PIN r0_rd_out[33]
    DIRECTION OUTPUT ;
    USE SIGNAL ;
    SHAPE ABUTMENT ;
    PORT
      LAYER M3 ;
      RECT 75.951 0.000 75.969 0.054 ;
    END
  END r0_rd_out[33]
  PIN r0_rd_out[34]
    DIRECTION OUTPUT ;
    USE SIGNAL ;
    SHAPE ABUTMENT ;
    PORT
      LAYER M3 ;
      RECT 76.239 0.000 76.257 0.054 ;
    END
  END r0_rd_out[34]
  PIN r0_rd_out[35]
    DIRECTION OUTPUT ;
    USE SIGNAL ;
    SHAPE ABUTMENT ;
    PORT
      LAYER M3 ;
      RECT 76.527 0.000 76.545 0.054 ;
    END
  END r0_rd_out[35]
  PIN r0_rd_out[36]
    DIRECTION OUTPUT ;
    USE SIGNAL ;
    SHAPE ABUTMENT ;
    PORT
      LAYER M3 ;
      RECT 76.815 0.000 76.833 0.054 ;
    END
  END r0_rd_out[36]
  PIN r0_rd_out[37]
    DIRECTION OUTPUT ;
    USE SIGNAL ;
    SHAPE ABUTMENT ;
    PORT
      LAYER M3 ;
      RECT 77.103 0.000 77.121 0.054 ;
    END
  END r0_rd_out[37]
  PIN r0_rd_out[38]
    DIRECTION OUTPUT ;
    USE SIGNAL ;
    SHAPE ABUTMENT ;
    PORT
      LAYER M3 ;
      RECT 77.391 0.000 77.409 0.054 ;
    END
  END r0_rd_out[38]
  PIN r0_rd_out[39]
    DIRECTION OUTPUT ;
    USE SIGNAL ;
    SHAPE ABUTMENT ;
    PORT
      LAYER M3 ;
      RECT 77.679 0.000 77.697 0.054 ;
    END
  END r0_rd_out[39]
  PIN r0_rd_out[40]
    DIRECTION OUTPUT ;
    USE SIGNAL ;
    SHAPE ABUTMENT ;
    PORT
      LAYER M3 ;
      RECT 77.967 0.000 77.985 0.054 ;
    END
  END r0_rd_out[40]
  PIN r0_rd_out[41]
    DIRECTION OUTPUT ;
    USE SIGNAL ;
    SHAPE ABUTMENT ;
    PORT
      LAYER M3 ;
      RECT 78.255 0.000 78.273 0.054 ;
    END
  END r0_rd_out[41]
  PIN r0_rd_out[42]
    DIRECTION OUTPUT ;
    USE SIGNAL ;
    SHAPE ABUTMENT ;
    PORT
      LAYER M3 ;
      RECT 78.543 0.000 78.561 0.054 ;
    END
  END r0_rd_out[42]
  PIN r0_rd_out[43]
    DIRECTION OUTPUT ;
    USE SIGNAL ;
    SHAPE ABUTMENT ;
    PORT
      LAYER M3 ;
      RECT 78.831 0.000 78.849 0.054 ;
    END
  END r0_rd_out[43]
  PIN r0_rd_out[44]
    DIRECTION OUTPUT ;
    USE SIGNAL ;
    SHAPE ABUTMENT ;
    PORT
      LAYER M3 ;
      RECT 79.119 0.000 79.137 0.054 ;
    END
  END r0_rd_out[44]
  PIN r0_rd_out[45]
    DIRECTION OUTPUT ;
    USE SIGNAL ;
    SHAPE ABUTMENT ;
    PORT
      LAYER M3 ;
      RECT 79.407 0.000 79.425 0.054 ;
    END
  END r0_rd_out[45]
  PIN r0_rd_out[46]
    DIRECTION OUTPUT ;
    USE SIGNAL ;
    SHAPE ABUTMENT ;
    PORT
      LAYER M3 ;
      RECT 79.695 0.000 79.713 0.054 ;
    END
  END r0_rd_out[46]
  PIN r0_rd_out[47]
    DIRECTION OUTPUT ;
    USE SIGNAL ;
    SHAPE ABUTMENT ;
    PORT
      LAYER M3 ;
      RECT 79.983 0.000 80.001 0.054 ;
    END
  END r0_rd_out[47]
  PIN r0_rd_out[48]
    DIRECTION OUTPUT ;
    USE SIGNAL ;
    SHAPE ABUTMENT ;
    PORT
      LAYER M3 ;
      RECT 80.271 0.000 80.289 0.054 ;
    END
  END r0_rd_out[48]
  PIN r0_rd_out[49]
    DIRECTION OUTPUT ;
    USE SIGNAL ;
    SHAPE ABUTMENT ;
    PORT
      LAYER M3 ;
      RECT 80.559 0.000 80.577 0.054 ;
    END
  END r0_rd_out[49]
  PIN r0_rd_out[50]
    DIRECTION OUTPUT ;
    USE SIGNAL ;
    SHAPE ABUTMENT ;
    PORT
      LAYER M3 ;
      RECT 80.847 0.000 80.865 0.054 ;
    END
  END r0_rd_out[50]
  PIN r0_rd_out[51]
    DIRECTION OUTPUT ;
    USE SIGNAL ;
    SHAPE ABUTMENT ;
    PORT
      LAYER M3 ;
      RECT 81.135 0.000 81.153 0.054 ;
    END
  END r0_rd_out[51]
  PIN r0_rd_out[52]
    DIRECTION OUTPUT ;
    USE SIGNAL ;
    SHAPE ABUTMENT ;
    PORT
      LAYER M3 ;
      RECT 81.423 0.000 81.441 0.054 ;
    END
  END r0_rd_out[52]
  PIN r0_rd_out[53]
    DIRECTION OUTPUT ;
    USE SIGNAL ;
    SHAPE ABUTMENT ;
    PORT
      LAYER M3 ;
      RECT 81.711 0.000 81.729 0.054 ;
    END
  END r0_rd_out[53]
  PIN r0_rd_out[54]
    DIRECTION OUTPUT ;
    USE SIGNAL ;
    SHAPE ABUTMENT ;
    PORT
      LAYER M3 ;
      RECT 81.999 0.000 82.017 0.054 ;
    END
  END r0_rd_out[54]
  PIN r0_rd_out[55]
    DIRECTION OUTPUT ;
    USE SIGNAL ;
    SHAPE ABUTMENT ;
    PORT
      LAYER M3 ;
      RECT 82.287 0.000 82.305 0.054 ;
    END
  END r0_rd_out[55]
  PIN r0_rd_out[56]
    DIRECTION OUTPUT ;
    USE SIGNAL ;
    SHAPE ABUTMENT ;
    PORT
      LAYER M3 ;
      RECT 82.575 0.000 82.593 0.054 ;
    END
  END r0_rd_out[56]
  PIN r0_rd_out[57]
    DIRECTION OUTPUT ;
    USE SIGNAL ;
    SHAPE ABUTMENT ;
    PORT
      LAYER M3 ;
      RECT 82.863 0.000 82.881 0.054 ;
    END
  END r0_rd_out[57]
  PIN r0_rd_out[58]
    DIRECTION OUTPUT ;
    USE SIGNAL ;
    SHAPE ABUTMENT ;
    PORT
      LAYER M3 ;
      RECT 83.151 0.000 83.169 0.054 ;
    END
  END r0_rd_out[58]
  PIN r0_rd_out[59]
    DIRECTION OUTPUT ;
    USE SIGNAL ;
    SHAPE ABUTMENT ;
    PORT
      LAYER M3 ;
      RECT 83.439 0.000 83.457 0.054 ;
    END
  END r0_rd_out[59]
  PIN r0_rd_out[60]
    DIRECTION OUTPUT ;
    USE SIGNAL ;
    SHAPE ABUTMENT ;
    PORT
      LAYER M3 ;
      RECT 83.727 0.000 83.745 0.054 ;
    END
  END r0_rd_out[60]
  PIN r0_rd_out[61]
    DIRECTION OUTPUT ;
    USE SIGNAL ;
    SHAPE ABUTMENT ;
    PORT
      LAYER M3 ;
      RECT 84.015 0.000 84.033 0.054 ;
    END
  END r0_rd_out[61]
  PIN r0_rd_out[62]
    DIRECTION OUTPUT ;
    USE SIGNAL ;
    SHAPE ABUTMENT ;
    PORT
      LAYER M3 ;
      RECT 84.303 0.000 84.321 0.054 ;
    END
  END r0_rd_out[62]
  PIN r0_rd_out[63]
    DIRECTION OUTPUT ;
    USE SIGNAL ;
    SHAPE ABUTMENT ;
    PORT
      LAYER M3 ;
      RECT 84.591 0.000 84.609 0.054 ;
    END
  END r0_rd_out[63]
  PIN r0_rd_out[64]
    DIRECTION OUTPUT ;
    USE SIGNAL ;
    SHAPE ABUTMENT ;
    PORT
      LAYER M3 ;
      RECT 84.879 0.000 84.897 0.054 ;
    END
  END r0_rd_out[64]
  PIN r0_rd_out[65]
    DIRECTION OUTPUT ;
    USE SIGNAL ;
    SHAPE ABUTMENT ;
    PORT
      LAYER M3 ;
      RECT 85.167 0.000 85.185 0.054 ;
    END
  END r0_rd_out[65]
  PIN r0_rd_out[66]
    DIRECTION OUTPUT ;
    USE SIGNAL ;
    SHAPE ABUTMENT ;
    PORT
      LAYER M3 ;
      RECT 85.455 0.000 85.473 0.054 ;
    END
  END r0_rd_out[66]
  PIN r0_rd_out[67]
    DIRECTION OUTPUT ;
    USE SIGNAL ;
    SHAPE ABUTMENT ;
    PORT
      LAYER M3 ;
      RECT 85.743 0.000 85.761 0.054 ;
    END
  END r0_rd_out[67]
  PIN r0_rd_out[68]
    DIRECTION OUTPUT ;
    USE SIGNAL ;
    SHAPE ABUTMENT ;
    PORT
      LAYER M3 ;
      RECT 86.031 0.000 86.049 0.054 ;
    END
  END r0_rd_out[68]
  PIN r0_rd_out[69]
    DIRECTION OUTPUT ;
    USE SIGNAL ;
    SHAPE ABUTMENT ;
    PORT
      LAYER M3 ;
      RECT 86.319 0.000 86.337 0.054 ;
    END
  END r0_rd_out[69]
  PIN r0_rd_out[70]
    DIRECTION OUTPUT ;
    USE SIGNAL ;
    SHAPE ABUTMENT ;
    PORT
      LAYER M3 ;
      RECT 86.607 0.000 86.625 0.054 ;
    END
  END r0_rd_out[70]
  PIN r0_rd_out[71]
    DIRECTION OUTPUT ;
    USE SIGNAL ;
    SHAPE ABUTMENT ;
    PORT
      LAYER M3 ;
      RECT 86.895 0.000 86.913 0.054 ;
    END
  END r0_rd_out[71]
  PIN r0_rd_out[72]
    DIRECTION OUTPUT ;
    USE SIGNAL ;
    SHAPE ABUTMENT ;
    PORT
      LAYER M3 ;
      RECT 87.183 0.000 87.201 0.054 ;
    END
  END r0_rd_out[72]
  PIN r0_rd_out[73]
    DIRECTION OUTPUT ;
    USE SIGNAL ;
    SHAPE ABUTMENT ;
    PORT
      LAYER M3 ;
      RECT 87.471 0.000 87.489 0.054 ;
    END
  END r0_rd_out[73]
  PIN r0_rd_out[74]
    DIRECTION OUTPUT ;
    USE SIGNAL ;
    SHAPE ABUTMENT ;
    PORT
      LAYER M3 ;
      RECT 87.759 0.000 87.777 0.054 ;
    END
  END r0_rd_out[74]
  PIN r0_rd_out[75]
    DIRECTION OUTPUT ;
    USE SIGNAL ;
    SHAPE ABUTMENT ;
    PORT
      LAYER M3 ;
      RECT 88.047 0.000 88.065 0.054 ;
    END
  END r0_rd_out[75]
  PIN r0_rd_out[76]
    DIRECTION OUTPUT ;
    USE SIGNAL ;
    SHAPE ABUTMENT ;
    PORT
      LAYER M3 ;
      RECT 88.335 0.000 88.353 0.054 ;
    END
  END r0_rd_out[76]
  PIN r0_rd_out[77]
    DIRECTION OUTPUT ;
    USE SIGNAL ;
    SHAPE ABUTMENT ;
    PORT
      LAYER M3 ;
      RECT 88.623 0.000 88.641 0.054 ;
    END
  END r0_rd_out[77]
  PIN r0_rd_out[78]
    DIRECTION OUTPUT ;
    USE SIGNAL ;
    SHAPE ABUTMENT ;
    PORT
      LAYER M3 ;
      RECT 88.911 0.000 88.929 0.054 ;
    END
  END r0_rd_out[78]
  PIN r0_rd_out[79]
    DIRECTION OUTPUT ;
    USE SIGNAL ;
    SHAPE ABUTMENT ;
    PORT
      LAYER M3 ;
      RECT 89.199 0.000 89.217 0.054 ;
    END
  END r0_rd_out[79]
  PIN r0_rd_out[80]
    DIRECTION OUTPUT ;
    USE SIGNAL ;
    SHAPE ABUTMENT ;
    PORT
      LAYER M3 ;
      RECT 89.487 0.000 89.505 0.054 ;
    END
  END r0_rd_out[80]
  PIN r0_rd_out[81]
    DIRECTION OUTPUT ;
    USE SIGNAL ;
    SHAPE ABUTMENT ;
    PORT
      LAYER M3 ;
      RECT 89.775 0.000 89.793 0.054 ;
    END
  END r0_rd_out[81]
  PIN r0_rd_out[82]
    DIRECTION OUTPUT ;
    USE SIGNAL ;
    SHAPE ABUTMENT ;
    PORT
      LAYER M3 ;
      RECT 90.063 0.000 90.081 0.054 ;
    END
  END r0_rd_out[82]
  PIN r0_rd_out[83]
    DIRECTION OUTPUT ;
    USE SIGNAL ;
    SHAPE ABUTMENT ;
    PORT
      LAYER M3 ;
      RECT 90.351 0.000 90.369 0.054 ;
    END
  END r0_rd_out[83]
  PIN r0_rd_out[84]
    DIRECTION OUTPUT ;
    USE SIGNAL ;
    SHAPE ABUTMENT ;
    PORT
      LAYER M3 ;
      RECT 90.639 0.000 90.657 0.054 ;
    END
  END r0_rd_out[84]
  PIN r0_rd_out[85]
    DIRECTION OUTPUT ;
    USE SIGNAL ;
    SHAPE ABUTMENT ;
    PORT
      LAYER M3 ;
      RECT 90.927 0.000 90.945 0.054 ;
    END
  END r0_rd_out[85]
  PIN r0_rd_out[86]
    DIRECTION OUTPUT ;
    USE SIGNAL ;
    SHAPE ABUTMENT ;
    PORT
      LAYER M3 ;
      RECT 91.215 0.000 91.233 0.054 ;
    END
  END r0_rd_out[86]
  PIN r0_rd_out[87]
    DIRECTION OUTPUT ;
    USE SIGNAL ;
    SHAPE ABUTMENT ;
    PORT
      LAYER M3 ;
      RECT 91.503 0.000 91.521 0.054 ;
    END
  END r0_rd_out[87]
  PIN r0_rd_out[88]
    DIRECTION OUTPUT ;
    USE SIGNAL ;
    SHAPE ABUTMENT ;
    PORT
      LAYER M3 ;
      RECT 91.791 0.000 91.809 0.054 ;
    END
  END r0_rd_out[88]
  PIN r0_rd_out[89]
    DIRECTION OUTPUT ;
    USE SIGNAL ;
    SHAPE ABUTMENT ;
    PORT
      LAYER M3 ;
      RECT 92.079 0.000 92.097 0.054 ;
    END
  END r0_rd_out[89]
  PIN r0_rd_out[90]
    DIRECTION OUTPUT ;
    USE SIGNAL ;
    SHAPE ABUTMENT ;
    PORT
      LAYER M3 ;
      RECT 92.367 0.000 92.385 0.054 ;
    END
  END r0_rd_out[90]
  PIN r0_rd_out[91]
    DIRECTION OUTPUT ;
    USE SIGNAL ;
    SHAPE ABUTMENT ;
    PORT
      LAYER M3 ;
      RECT 92.655 0.000 92.673 0.054 ;
    END
  END r0_rd_out[91]
  PIN r0_rd_out[92]
    DIRECTION OUTPUT ;
    USE SIGNAL ;
    SHAPE ABUTMENT ;
    PORT
      LAYER M3 ;
      RECT 92.943 0.000 92.961 0.054 ;
    END
  END r0_rd_out[92]
  PIN r0_rd_out[93]
    DIRECTION OUTPUT ;
    USE SIGNAL ;
    SHAPE ABUTMENT ;
    PORT
      LAYER M3 ;
      RECT 93.231 0.000 93.249 0.054 ;
    END
  END r0_rd_out[93]
  PIN r0_rd_out[94]
    DIRECTION OUTPUT ;
    USE SIGNAL ;
    SHAPE ABUTMENT ;
    PORT
      LAYER M3 ;
      RECT 93.519 0.000 93.537 0.054 ;
    END
  END r0_rd_out[94]
  PIN r0_rd_out[95]
    DIRECTION OUTPUT ;
    USE SIGNAL ;
    SHAPE ABUTMENT ;
    PORT
      LAYER M3 ;
      RECT 93.807 0.000 93.825 0.054 ;
    END
  END r0_rd_out[95]
  PIN r0_rd_out[96]
    DIRECTION OUTPUT ;
    USE SIGNAL ;
    SHAPE ABUTMENT ;
    PORT
      LAYER M3 ;
      RECT 94.095 0.000 94.113 0.054 ;
    END
  END r0_rd_out[96]
  PIN r0_rd_out[97]
    DIRECTION OUTPUT ;
    USE SIGNAL ;
    SHAPE ABUTMENT ;
    PORT
      LAYER M3 ;
      RECT 94.383 0.000 94.401 0.054 ;
    END
  END r0_rd_out[97]
  PIN r0_rd_out[98]
    DIRECTION OUTPUT ;
    USE SIGNAL ;
    SHAPE ABUTMENT ;
    PORT
      LAYER M3 ;
      RECT 94.671 0.000 94.689 0.054 ;
    END
  END r0_rd_out[98]
  PIN r0_rd_out[99]
    DIRECTION OUTPUT ;
    USE SIGNAL ;
    SHAPE ABUTMENT ;
    PORT
      LAYER M3 ;
      RECT 94.959 0.000 94.977 0.054 ;
    END
  END r0_rd_out[99]
  PIN r0_rd_out[100]
    DIRECTION OUTPUT ;
    USE SIGNAL ;
    SHAPE ABUTMENT ;
    PORT
      LAYER M3 ;
      RECT 95.247 0.000 95.265 0.054 ;
    END
  END r0_rd_out[100]
  PIN r0_rd_out[101]
    DIRECTION OUTPUT ;
    USE SIGNAL ;
    SHAPE ABUTMENT ;
    PORT
      LAYER M3 ;
      RECT 95.535 0.000 95.553 0.054 ;
    END
  END r0_rd_out[101]
  PIN r0_rd_out[102]
    DIRECTION OUTPUT ;
    USE SIGNAL ;
    SHAPE ABUTMENT ;
    PORT
      LAYER M3 ;
      RECT 95.823 0.000 95.841 0.054 ;
    END
  END r0_rd_out[102]
  PIN r0_rd_out[103]
    DIRECTION OUTPUT ;
    USE SIGNAL ;
    SHAPE ABUTMENT ;
    PORT
      LAYER M3 ;
      RECT 96.111 0.000 96.129 0.054 ;
    END
  END r0_rd_out[103]
  PIN r0_rd_out[104]
    DIRECTION OUTPUT ;
    USE SIGNAL ;
    SHAPE ABUTMENT ;
    PORT
      LAYER M3 ;
      RECT 96.399 0.000 96.417 0.054 ;
    END
  END r0_rd_out[104]
  PIN r0_rd_out[105]
    DIRECTION OUTPUT ;
    USE SIGNAL ;
    SHAPE ABUTMENT ;
    PORT
      LAYER M3 ;
      RECT 96.687 0.000 96.705 0.054 ;
    END
  END r0_rd_out[105]
  PIN r0_rd_out[106]
    DIRECTION OUTPUT ;
    USE SIGNAL ;
    SHAPE ABUTMENT ;
    PORT
      LAYER M3 ;
      RECT 96.975 0.000 96.993 0.054 ;
    END
  END r0_rd_out[106]
  PIN r0_rd_out[107]
    DIRECTION OUTPUT ;
    USE SIGNAL ;
    SHAPE ABUTMENT ;
    PORT
      LAYER M3 ;
      RECT 97.263 0.000 97.281 0.054 ;
    END
  END r0_rd_out[107]
  PIN r0_rd_out[108]
    DIRECTION OUTPUT ;
    USE SIGNAL ;
    SHAPE ABUTMENT ;
    PORT
      LAYER M3 ;
      RECT 97.551 0.000 97.569 0.054 ;
    END
  END r0_rd_out[108]
  PIN r0_rd_out[109]
    DIRECTION OUTPUT ;
    USE SIGNAL ;
    SHAPE ABUTMENT ;
    PORT
      LAYER M3 ;
      RECT 97.839 0.000 97.857 0.054 ;
    END
  END r0_rd_out[109]
  PIN r0_rd_out[110]
    DIRECTION OUTPUT ;
    USE SIGNAL ;
    SHAPE ABUTMENT ;
    PORT
      LAYER M3 ;
      RECT 98.127 0.000 98.145 0.054 ;
    END
  END r0_rd_out[110]
  PIN r0_rd_out[111]
    DIRECTION OUTPUT ;
    USE SIGNAL ;
    SHAPE ABUTMENT ;
    PORT
      LAYER M3 ;
      RECT 98.415 0.000 98.433 0.054 ;
    END
  END r0_rd_out[111]
  PIN r0_rd_out[112]
    DIRECTION OUTPUT ;
    USE SIGNAL ;
    SHAPE ABUTMENT ;
    PORT
      LAYER M3 ;
      RECT 98.703 0.000 98.721 0.054 ;
    END
  END r0_rd_out[112]
  PIN r0_rd_out[113]
    DIRECTION OUTPUT ;
    USE SIGNAL ;
    SHAPE ABUTMENT ;
    PORT
      LAYER M3 ;
      RECT 98.991 0.000 99.009 0.054 ;
    END
  END r0_rd_out[113]
  PIN r0_rd_out[114]
    DIRECTION OUTPUT ;
    USE SIGNAL ;
    SHAPE ABUTMENT ;
    PORT
      LAYER M3 ;
      RECT 99.279 0.000 99.297 0.054 ;
    END
  END r0_rd_out[114]
  PIN r0_rd_out[115]
    DIRECTION OUTPUT ;
    USE SIGNAL ;
    SHAPE ABUTMENT ;
    PORT
      LAYER M3 ;
      RECT 49.887 146.827 49.905 146.881 ;
    END
  END r0_rd_out[115]
  PIN r0_rd_out[116]
    DIRECTION OUTPUT ;
    USE SIGNAL ;
    SHAPE ABUTMENT ;
    PORT
      LAYER M3 ;
      RECT 50.319 146.827 50.337 146.881 ;
    END
  END r0_rd_out[116]
  PIN r0_rd_out[117]
    DIRECTION OUTPUT ;
    USE SIGNAL ;
    SHAPE ABUTMENT ;
    PORT
      LAYER M3 ;
      RECT 50.751 146.827 50.769 146.881 ;
    END
  END r0_rd_out[117]
  PIN r0_rd_out[118]
    DIRECTION OUTPUT ;
    USE SIGNAL ;
    SHAPE ABUTMENT ;
    PORT
      LAYER M3 ;
      RECT 51.183 146.827 51.201 146.881 ;
    END
  END r0_rd_out[118]
  PIN r0_rd_out[119]
    DIRECTION OUTPUT ;
    USE SIGNAL ;
    SHAPE ABUTMENT ;
    PORT
      LAYER M3 ;
      RECT 51.615 146.827 51.633 146.881 ;
    END
  END r0_rd_out[119]
  PIN r0_rd_out[120]
    DIRECTION OUTPUT ;
    USE SIGNAL ;
    SHAPE ABUTMENT ;
    PORT
      LAYER M3 ;
      RECT 52.047 146.827 52.065 146.881 ;
    END
  END r0_rd_out[120]
  PIN r0_rd_out[121]
    DIRECTION OUTPUT ;
    USE SIGNAL ;
    SHAPE ABUTMENT ;
    PORT
      LAYER M3 ;
      RECT 52.479 146.827 52.497 146.881 ;
    END
  END r0_rd_out[121]
  PIN r0_rd_out[122]
    DIRECTION OUTPUT ;
    USE SIGNAL ;
    SHAPE ABUTMENT ;
    PORT
      LAYER M3 ;
      RECT 52.911 146.827 52.929 146.881 ;
    END
  END r0_rd_out[122]
  PIN r0_rd_out[123]
    DIRECTION OUTPUT ;
    USE SIGNAL ;
    SHAPE ABUTMENT ;
    PORT
      LAYER M3 ;
      RECT 53.343 146.827 53.361 146.881 ;
    END
  END r0_rd_out[123]
  PIN r0_rd_out[124]
    DIRECTION OUTPUT ;
    USE SIGNAL ;
    SHAPE ABUTMENT ;
    PORT
      LAYER M3 ;
      RECT 53.775 146.827 53.793 146.881 ;
    END
  END r0_rd_out[124]
  PIN r0_rd_out[125]
    DIRECTION OUTPUT ;
    USE SIGNAL ;
    SHAPE ABUTMENT ;
    PORT
      LAYER M3 ;
      RECT 54.207 146.827 54.225 146.881 ;
    END
  END r0_rd_out[125]
  PIN r0_rd_out[126]
    DIRECTION OUTPUT ;
    USE SIGNAL ;
    SHAPE ABUTMENT ;
    PORT
      LAYER M3 ;
      RECT 54.639 146.827 54.657 146.881 ;
    END
  END r0_rd_out[126]
  PIN r0_rd_out[127]
    DIRECTION OUTPUT ;
    USE SIGNAL ;
    SHAPE ABUTMENT ;
    PORT
      LAYER M3 ;
      RECT 55.071 146.827 55.089 146.881 ;
    END
  END r0_rd_out[127]
  PIN r0_rd_out[128]
    DIRECTION OUTPUT ;
    USE SIGNAL ;
    SHAPE ABUTMENT ;
    PORT
      LAYER M3 ;
      RECT 55.503 146.827 55.521 146.881 ;
    END
  END r0_rd_out[128]
  PIN r0_rd_out[129]
    DIRECTION OUTPUT ;
    USE SIGNAL ;
    SHAPE ABUTMENT ;
    PORT
      LAYER M3 ;
      RECT 55.935 146.827 55.953 146.881 ;
    END
  END r0_rd_out[129]
  PIN r0_rd_out[130]
    DIRECTION OUTPUT ;
    USE SIGNAL ;
    SHAPE ABUTMENT ;
    PORT
      LAYER M3 ;
      RECT 56.367 146.827 56.385 146.881 ;
    END
  END r0_rd_out[130]
  PIN r0_rd_out[131]
    DIRECTION OUTPUT ;
    USE SIGNAL ;
    SHAPE ABUTMENT ;
    PORT
      LAYER M3 ;
      RECT 56.799 146.827 56.817 146.881 ;
    END
  END r0_rd_out[131]
  PIN r0_rd_out[132]
    DIRECTION OUTPUT ;
    USE SIGNAL ;
    SHAPE ABUTMENT ;
    PORT
      LAYER M3 ;
      RECT 57.231 146.827 57.249 146.881 ;
    END
  END r0_rd_out[132]
  PIN r0_rd_out[133]
    DIRECTION OUTPUT ;
    USE SIGNAL ;
    SHAPE ABUTMENT ;
    PORT
      LAYER M3 ;
      RECT 57.663 146.827 57.681 146.881 ;
    END
  END r0_rd_out[133]
  PIN r0_rd_out[134]
    DIRECTION OUTPUT ;
    USE SIGNAL ;
    SHAPE ABUTMENT ;
    PORT
      LAYER M3 ;
      RECT 58.095 146.827 58.113 146.881 ;
    END
  END r0_rd_out[134]
  PIN r0_rd_out[135]
    DIRECTION OUTPUT ;
    USE SIGNAL ;
    SHAPE ABUTMENT ;
    PORT
      LAYER M3 ;
      RECT 58.527 146.827 58.545 146.881 ;
    END
  END r0_rd_out[135]
  PIN r0_rd_out[136]
    DIRECTION OUTPUT ;
    USE SIGNAL ;
    SHAPE ABUTMENT ;
    PORT
      LAYER M3 ;
      RECT 58.959 146.827 58.977 146.881 ;
    END
  END r0_rd_out[136]
  PIN r0_rd_out[137]
    DIRECTION OUTPUT ;
    USE SIGNAL ;
    SHAPE ABUTMENT ;
    PORT
      LAYER M3 ;
      RECT 59.391 146.827 59.409 146.881 ;
    END
  END r0_rd_out[137]
  PIN r0_rd_out[138]
    DIRECTION OUTPUT ;
    USE SIGNAL ;
    SHAPE ABUTMENT ;
    PORT
      LAYER M3 ;
      RECT 59.823 146.827 59.841 146.881 ;
    END
  END r0_rd_out[138]
  PIN r0_rd_out[139]
    DIRECTION OUTPUT ;
    USE SIGNAL ;
    SHAPE ABUTMENT ;
    PORT
      LAYER M3 ;
      RECT 60.255 146.827 60.273 146.881 ;
    END
  END r0_rd_out[139]
  PIN r0_rd_out[140]
    DIRECTION OUTPUT ;
    USE SIGNAL ;
    SHAPE ABUTMENT ;
    PORT
      LAYER M3 ;
      RECT 60.687 146.827 60.705 146.881 ;
    END
  END r0_rd_out[140]
  PIN r0_rd_out[141]
    DIRECTION OUTPUT ;
    USE SIGNAL ;
    SHAPE ABUTMENT ;
    PORT
      LAYER M3 ;
      RECT 61.119 146.827 61.137 146.881 ;
    END
  END r0_rd_out[141]
  PIN r0_rd_out[142]
    DIRECTION OUTPUT ;
    USE SIGNAL ;
    SHAPE ABUTMENT ;
    PORT
      LAYER M3 ;
      RECT 61.551 146.827 61.569 146.881 ;
    END
  END r0_rd_out[142]
  PIN r0_rd_out[143]
    DIRECTION OUTPUT ;
    USE SIGNAL ;
    SHAPE ABUTMENT ;
    PORT
      LAYER M3 ;
      RECT 61.983 146.827 62.001 146.881 ;
    END
  END r0_rd_out[143]
  PIN r0_rd_out[144]
    DIRECTION OUTPUT ;
    USE SIGNAL ;
    SHAPE ABUTMENT ;
    PORT
      LAYER M3 ;
      RECT 62.415 146.827 62.433 146.881 ;
    END
  END r0_rd_out[144]
  PIN r0_rd_out[145]
    DIRECTION OUTPUT ;
    USE SIGNAL ;
    SHAPE ABUTMENT ;
    PORT
      LAYER M3 ;
      RECT 62.847 146.827 62.865 146.881 ;
    END
  END r0_rd_out[145]
  PIN r0_rd_out[146]
    DIRECTION OUTPUT ;
    USE SIGNAL ;
    SHAPE ABUTMENT ;
    PORT
      LAYER M3 ;
      RECT 63.279 146.827 63.297 146.881 ;
    END
  END r0_rd_out[146]
  PIN r0_rd_out[147]
    DIRECTION OUTPUT ;
    USE SIGNAL ;
    SHAPE ABUTMENT ;
    PORT
      LAYER M3 ;
      RECT 63.711 146.827 63.729 146.881 ;
    END
  END r0_rd_out[147]
  PIN r0_rd_out[148]
    DIRECTION OUTPUT ;
    USE SIGNAL ;
    SHAPE ABUTMENT ;
    PORT
      LAYER M3 ;
      RECT 64.143 146.827 64.161 146.881 ;
    END
  END r0_rd_out[148]
  PIN r0_rd_out[149]
    DIRECTION OUTPUT ;
    USE SIGNAL ;
    SHAPE ABUTMENT ;
    PORT
      LAYER M3 ;
      RECT 64.575 146.827 64.593 146.881 ;
    END
  END r0_rd_out[149]
  PIN r0_rd_out[150]
    DIRECTION OUTPUT ;
    USE SIGNAL ;
    SHAPE ABUTMENT ;
    PORT
      LAYER M3 ;
      RECT 65.007 146.827 65.025 146.881 ;
    END
  END r0_rd_out[150]
  PIN r0_rd_out[151]
    DIRECTION OUTPUT ;
    USE SIGNAL ;
    SHAPE ABUTMENT ;
    PORT
      LAYER M3 ;
      RECT 65.439 146.827 65.457 146.881 ;
    END
  END r0_rd_out[151]
  PIN r0_rd_out[152]
    DIRECTION OUTPUT ;
    USE SIGNAL ;
    SHAPE ABUTMENT ;
    PORT
      LAYER M3 ;
      RECT 65.871 146.827 65.889 146.881 ;
    END
  END r0_rd_out[152]
  PIN r0_rd_out[153]
    DIRECTION OUTPUT ;
    USE SIGNAL ;
    SHAPE ABUTMENT ;
    PORT
      LAYER M3 ;
      RECT 66.303 146.827 66.321 146.881 ;
    END
  END r0_rd_out[153]
  PIN r0_rd_out[154]
    DIRECTION OUTPUT ;
    USE SIGNAL ;
    SHAPE ABUTMENT ;
    PORT
      LAYER M3 ;
      RECT 66.735 146.827 66.753 146.881 ;
    END
  END r0_rd_out[154]
  PIN r0_rd_out[155]
    DIRECTION OUTPUT ;
    USE SIGNAL ;
    SHAPE ABUTMENT ;
    PORT
      LAYER M3 ;
      RECT 67.167 146.827 67.185 146.881 ;
    END
  END r0_rd_out[155]
  PIN r0_rd_out[156]
    DIRECTION OUTPUT ;
    USE SIGNAL ;
    SHAPE ABUTMENT ;
    PORT
      LAYER M3 ;
      RECT 67.599 146.827 67.617 146.881 ;
    END
  END r0_rd_out[156]
  PIN r0_rd_out[157]
    DIRECTION OUTPUT ;
    USE SIGNAL ;
    SHAPE ABUTMENT ;
    PORT
      LAYER M3 ;
      RECT 68.031 146.827 68.049 146.881 ;
    END
  END r0_rd_out[157]
  PIN r0_rd_out[158]
    DIRECTION OUTPUT ;
    USE SIGNAL ;
    SHAPE ABUTMENT ;
    PORT
      LAYER M3 ;
      RECT 68.463 146.827 68.481 146.881 ;
    END
  END r0_rd_out[158]
  PIN r0_rd_out[159]
    DIRECTION OUTPUT ;
    USE SIGNAL ;
    SHAPE ABUTMENT ;
    PORT
      LAYER M3 ;
      RECT 68.895 146.827 68.913 146.881 ;
    END
  END r0_rd_out[159]
  PIN r0_rd_out[160]
    DIRECTION OUTPUT ;
    USE SIGNAL ;
    SHAPE ABUTMENT ;
    PORT
      LAYER M3 ;
      RECT 69.327 146.827 69.345 146.881 ;
    END
  END r0_rd_out[160]
  PIN r0_rd_out[161]
    DIRECTION OUTPUT ;
    USE SIGNAL ;
    SHAPE ABUTMENT ;
    PORT
      LAYER M3 ;
      RECT 69.759 146.827 69.777 146.881 ;
    END
  END r0_rd_out[161]
  PIN r0_rd_out[162]
    DIRECTION OUTPUT ;
    USE SIGNAL ;
    SHAPE ABUTMENT ;
    PORT
      LAYER M3 ;
      RECT 70.191 146.827 70.209 146.881 ;
    END
  END r0_rd_out[162]
  PIN r0_rd_out[163]
    DIRECTION OUTPUT ;
    USE SIGNAL ;
    SHAPE ABUTMENT ;
    PORT
      LAYER M3 ;
      RECT 70.623 146.827 70.641 146.881 ;
    END
  END r0_rd_out[163]
  PIN r0_rd_out[164]
    DIRECTION OUTPUT ;
    USE SIGNAL ;
    SHAPE ABUTMENT ;
    PORT
      LAYER M3 ;
      RECT 71.055 146.827 71.073 146.881 ;
    END
  END r0_rd_out[164]
  PIN r0_rd_out[165]
    DIRECTION OUTPUT ;
    USE SIGNAL ;
    SHAPE ABUTMENT ;
    PORT
      LAYER M3 ;
      RECT 71.487 146.827 71.505 146.881 ;
    END
  END r0_rd_out[165]
  PIN r0_rd_out[166]
    DIRECTION OUTPUT ;
    USE SIGNAL ;
    SHAPE ABUTMENT ;
    PORT
      LAYER M3 ;
      RECT 71.919 146.827 71.937 146.881 ;
    END
  END r0_rd_out[166]
  PIN r0_rd_out[167]
    DIRECTION OUTPUT ;
    USE SIGNAL ;
    SHAPE ABUTMENT ;
    PORT
      LAYER M3 ;
      RECT 72.351 146.827 72.369 146.881 ;
    END
  END r0_rd_out[167]
  PIN r0_rd_out[168]
    DIRECTION OUTPUT ;
    USE SIGNAL ;
    SHAPE ABUTMENT ;
    PORT
      LAYER M3 ;
      RECT 72.783 146.827 72.801 146.881 ;
    END
  END r0_rd_out[168]
  PIN r0_rd_out[169]
    DIRECTION OUTPUT ;
    USE SIGNAL ;
    SHAPE ABUTMENT ;
    PORT
      LAYER M3 ;
      RECT 73.215 146.827 73.233 146.881 ;
    END
  END r0_rd_out[169]
  PIN r0_rd_out[170]
    DIRECTION OUTPUT ;
    USE SIGNAL ;
    SHAPE ABUTMENT ;
    PORT
      LAYER M3 ;
      RECT 73.647 146.827 73.665 146.881 ;
    END
  END r0_rd_out[170]
  PIN r0_rd_out[171]
    DIRECTION OUTPUT ;
    USE SIGNAL ;
    SHAPE ABUTMENT ;
    PORT
      LAYER M3 ;
      RECT 74.079 146.827 74.097 146.881 ;
    END
  END r0_rd_out[171]
  PIN r0_rd_out[172]
    DIRECTION OUTPUT ;
    USE SIGNAL ;
    SHAPE ABUTMENT ;
    PORT
      LAYER M3 ;
      RECT 74.511 146.827 74.529 146.881 ;
    END
  END r0_rd_out[172]
  PIN r0_rd_out[173]
    DIRECTION OUTPUT ;
    USE SIGNAL ;
    SHAPE ABUTMENT ;
    PORT
      LAYER M3 ;
      RECT 74.943 146.827 74.961 146.881 ;
    END
  END r0_rd_out[173]
  PIN r0_rd_out[174]
    DIRECTION OUTPUT ;
    USE SIGNAL ;
    SHAPE ABUTMENT ;
    PORT
      LAYER M3 ;
      RECT 75.375 146.827 75.393 146.881 ;
    END
  END r0_rd_out[174]
  PIN r0_rd_out[175]
    DIRECTION OUTPUT ;
    USE SIGNAL ;
    SHAPE ABUTMENT ;
    PORT
      LAYER M3 ;
      RECT 75.807 146.827 75.825 146.881 ;
    END
  END r0_rd_out[175]
  PIN r0_rd_out[176]
    DIRECTION OUTPUT ;
    USE SIGNAL ;
    SHAPE ABUTMENT ;
    PORT
      LAYER M3 ;
      RECT 76.239 146.827 76.257 146.881 ;
    END
  END r0_rd_out[176]
  PIN r0_rd_out[177]
    DIRECTION OUTPUT ;
    USE SIGNAL ;
    SHAPE ABUTMENT ;
    PORT
      LAYER M3 ;
      RECT 76.671 146.827 76.689 146.881 ;
    END
  END r0_rd_out[177]
  PIN r0_rd_out[178]
    DIRECTION OUTPUT ;
    USE SIGNAL ;
    SHAPE ABUTMENT ;
    PORT
      LAYER M3 ;
      RECT 77.103 146.827 77.121 146.881 ;
    END
  END r0_rd_out[178]
  PIN r0_rd_out[179]
    DIRECTION OUTPUT ;
    USE SIGNAL ;
    SHAPE ABUTMENT ;
    PORT
      LAYER M3 ;
      RECT 77.535 146.827 77.553 146.881 ;
    END
  END r0_rd_out[179]
  PIN r0_rd_out[180]
    DIRECTION OUTPUT ;
    USE SIGNAL ;
    SHAPE ABUTMENT ;
    PORT
      LAYER M3 ;
      RECT 77.967 146.827 77.985 146.881 ;
    END
  END r0_rd_out[180]
  PIN r0_rd_out[181]
    DIRECTION OUTPUT ;
    USE SIGNAL ;
    SHAPE ABUTMENT ;
    PORT
      LAYER M3 ;
      RECT 78.399 146.827 78.417 146.881 ;
    END
  END r0_rd_out[181]
  PIN r0_rd_out[182]
    DIRECTION OUTPUT ;
    USE SIGNAL ;
    SHAPE ABUTMENT ;
    PORT
      LAYER M3 ;
      RECT 78.831 146.827 78.849 146.881 ;
    END
  END r0_rd_out[182]
  PIN r0_rd_out[183]
    DIRECTION OUTPUT ;
    USE SIGNAL ;
    SHAPE ABUTMENT ;
    PORT
      LAYER M3 ;
      RECT 79.263 146.827 79.281 146.881 ;
    END
  END r0_rd_out[183]
  PIN r0_rd_out[184]
    DIRECTION OUTPUT ;
    USE SIGNAL ;
    SHAPE ABUTMENT ;
    PORT
      LAYER M3 ;
      RECT 79.695 146.827 79.713 146.881 ;
    END
  END r0_rd_out[184]
  PIN r0_rd_out[185]
    DIRECTION OUTPUT ;
    USE SIGNAL ;
    SHAPE ABUTMENT ;
    PORT
      LAYER M3 ;
      RECT 80.127 146.827 80.145 146.881 ;
    END
  END r0_rd_out[185]
  PIN r0_rd_out[186]
    DIRECTION OUTPUT ;
    USE SIGNAL ;
    SHAPE ABUTMENT ;
    PORT
      LAYER M3 ;
      RECT 80.559 146.827 80.577 146.881 ;
    END
  END r0_rd_out[186]
  PIN r0_rd_out[187]
    DIRECTION OUTPUT ;
    USE SIGNAL ;
    SHAPE ABUTMENT ;
    PORT
      LAYER M3 ;
      RECT 80.991 146.827 81.009 146.881 ;
    END
  END r0_rd_out[187]
  PIN r0_rd_out[188]
    DIRECTION OUTPUT ;
    USE SIGNAL ;
    SHAPE ABUTMENT ;
    PORT
      LAYER M3 ;
      RECT 81.423 146.827 81.441 146.881 ;
    END
  END r0_rd_out[188]
  PIN r0_rd_out[189]
    DIRECTION OUTPUT ;
    USE SIGNAL ;
    SHAPE ABUTMENT ;
    PORT
      LAYER M3 ;
      RECT 81.855 146.827 81.873 146.881 ;
    END
  END r0_rd_out[189]
  PIN r0_rd_out[190]
    DIRECTION OUTPUT ;
    USE SIGNAL ;
    SHAPE ABUTMENT ;
    PORT
      LAYER M3 ;
      RECT 82.287 146.827 82.305 146.881 ;
    END
  END r0_rd_out[190]
  PIN r0_rd_out[191]
    DIRECTION OUTPUT ;
    USE SIGNAL ;
    SHAPE ABUTMENT ;
    PORT
      LAYER M3 ;
      RECT 82.719 146.827 82.737 146.881 ;
    END
  END r0_rd_out[191]
  PIN r0_rd_out[192]
    DIRECTION OUTPUT ;
    USE SIGNAL ;
    SHAPE ABUTMENT ;
    PORT
      LAYER M3 ;
      RECT 83.151 146.827 83.169 146.881 ;
    END
  END r0_rd_out[192]
  PIN r0_rd_out[193]
    DIRECTION OUTPUT ;
    USE SIGNAL ;
    SHAPE ABUTMENT ;
    PORT
      LAYER M3 ;
      RECT 83.583 146.827 83.601 146.881 ;
    END
  END r0_rd_out[193]
  PIN r0_rd_out[194]
    DIRECTION OUTPUT ;
    USE SIGNAL ;
    SHAPE ABUTMENT ;
    PORT
      LAYER M3 ;
      RECT 84.015 146.827 84.033 146.881 ;
    END
  END r0_rd_out[194]
  PIN r0_rd_out[195]
    DIRECTION OUTPUT ;
    USE SIGNAL ;
    SHAPE ABUTMENT ;
    PORT
      LAYER M3 ;
      RECT 84.447 146.827 84.465 146.881 ;
    END
  END r0_rd_out[195]
  PIN r0_rd_out[196]
    DIRECTION OUTPUT ;
    USE SIGNAL ;
    SHAPE ABUTMENT ;
    PORT
      LAYER M3 ;
      RECT 84.879 146.827 84.897 146.881 ;
    END
  END r0_rd_out[196]
  PIN r0_rd_out[197]
    DIRECTION OUTPUT ;
    USE SIGNAL ;
    SHAPE ABUTMENT ;
    PORT
      LAYER M3 ;
      RECT 85.311 146.827 85.329 146.881 ;
    END
  END r0_rd_out[197]
  PIN r0_rd_out[198]
    DIRECTION OUTPUT ;
    USE SIGNAL ;
    SHAPE ABUTMENT ;
    PORT
      LAYER M3 ;
      RECT 85.743 146.827 85.761 146.881 ;
    END
  END r0_rd_out[198]
  PIN r0_rd_out[199]
    DIRECTION OUTPUT ;
    USE SIGNAL ;
    SHAPE ABUTMENT ;
    PORT
      LAYER M3 ;
      RECT 86.175 146.827 86.193 146.881 ;
    END
  END r0_rd_out[199]
  PIN r0_rd_out[200]
    DIRECTION OUTPUT ;
    USE SIGNAL ;
    SHAPE ABUTMENT ;
    PORT
      LAYER M3 ;
      RECT 86.607 146.827 86.625 146.881 ;
    END
  END r0_rd_out[200]
  PIN r0_rd_out[201]
    DIRECTION OUTPUT ;
    USE SIGNAL ;
    SHAPE ABUTMENT ;
    PORT
      LAYER M3 ;
      RECT 87.039 146.827 87.057 146.881 ;
    END
  END r0_rd_out[201]
  PIN r0_rd_out[202]
    DIRECTION OUTPUT ;
    USE SIGNAL ;
    SHAPE ABUTMENT ;
    PORT
      LAYER M3 ;
      RECT 87.471 146.827 87.489 146.881 ;
    END
  END r0_rd_out[202]
  PIN r0_rd_out[203]
    DIRECTION OUTPUT ;
    USE SIGNAL ;
    SHAPE ABUTMENT ;
    PORT
      LAYER M3 ;
      RECT 87.903 146.827 87.921 146.881 ;
    END
  END r0_rd_out[203]
  PIN r0_rd_out[204]
    DIRECTION OUTPUT ;
    USE SIGNAL ;
    SHAPE ABUTMENT ;
    PORT
      LAYER M3 ;
      RECT 88.335 146.827 88.353 146.881 ;
    END
  END r0_rd_out[204]
  PIN r0_rd_out[205]
    DIRECTION OUTPUT ;
    USE SIGNAL ;
    SHAPE ABUTMENT ;
    PORT
      LAYER M3 ;
      RECT 88.767 146.827 88.785 146.881 ;
    END
  END r0_rd_out[205]
  PIN r0_rd_out[206]
    DIRECTION OUTPUT ;
    USE SIGNAL ;
    SHAPE ABUTMENT ;
    PORT
      LAYER M3 ;
      RECT 89.199 146.827 89.217 146.881 ;
    END
  END r0_rd_out[206]
  PIN r0_rd_out[207]
    DIRECTION OUTPUT ;
    USE SIGNAL ;
    SHAPE ABUTMENT ;
    PORT
      LAYER M3 ;
      RECT 89.631 146.827 89.649 146.881 ;
    END
  END r0_rd_out[207]
  PIN r0_rd_out[208]
    DIRECTION OUTPUT ;
    USE SIGNAL ;
    SHAPE ABUTMENT ;
    PORT
      LAYER M3 ;
      RECT 90.063 146.827 90.081 146.881 ;
    END
  END r0_rd_out[208]
  PIN r0_rd_out[209]
    DIRECTION OUTPUT ;
    USE SIGNAL ;
    SHAPE ABUTMENT ;
    PORT
      LAYER M3 ;
      RECT 90.495 146.827 90.513 146.881 ;
    END
  END r0_rd_out[209]
  PIN r0_rd_out[210]
    DIRECTION OUTPUT ;
    USE SIGNAL ;
    SHAPE ABUTMENT ;
    PORT
      LAYER M3 ;
      RECT 90.927 146.827 90.945 146.881 ;
    END
  END r0_rd_out[210]
  PIN r0_rd_out[211]
    DIRECTION OUTPUT ;
    USE SIGNAL ;
    SHAPE ABUTMENT ;
    PORT
      LAYER M3 ;
      RECT 91.359 146.827 91.377 146.881 ;
    END
  END r0_rd_out[211]
  PIN r0_rd_out[212]
    DIRECTION OUTPUT ;
    USE SIGNAL ;
    SHAPE ABUTMENT ;
    PORT
      LAYER M3 ;
      RECT 91.791 146.827 91.809 146.881 ;
    END
  END r0_rd_out[212]
  PIN r0_rd_out[213]
    DIRECTION OUTPUT ;
    USE SIGNAL ;
    SHAPE ABUTMENT ;
    PORT
      LAYER M3 ;
      RECT 92.223 146.827 92.241 146.881 ;
    END
  END r0_rd_out[213]
  PIN r0_rd_out[214]
    DIRECTION OUTPUT ;
    USE SIGNAL ;
    SHAPE ABUTMENT ;
    PORT
      LAYER M3 ;
      RECT 92.655 146.827 92.673 146.881 ;
    END
  END r0_rd_out[214]
  PIN r0_rd_out[215]
    DIRECTION OUTPUT ;
    USE SIGNAL ;
    SHAPE ABUTMENT ;
    PORT
      LAYER M3 ;
      RECT 93.087 146.827 93.105 146.881 ;
    END
  END r0_rd_out[215]
  PIN r0_rd_out[216]
    DIRECTION OUTPUT ;
    USE SIGNAL ;
    SHAPE ABUTMENT ;
    PORT
      LAYER M3 ;
      RECT 93.519 146.827 93.537 146.881 ;
    END
  END r0_rd_out[216]
  PIN r0_rd_out[217]
    DIRECTION OUTPUT ;
    USE SIGNAL ;
    SHAPE ABUTMENT ;
    PORT
      LAYER M3 ;
      RECT 93.951 146.827 93.969 146.881 ;
    END
  END r0_rd_out[217]
  PIN r0_rd_out[218]
    DIRECTION OUTPUT ;
    USE SIGNAL ;
    SHAPE ABUTMENT ;
    PORT
      LAYER M3 ;
      RECT 94.383 146.827 94.401 146.881 ;
    END
  END r0_rd_out[218]
  PIN r0_rd_out[219]
    DIRECTION OUTPUT ;
    USE SIGNAL ;
    SHAPE ABUTMENT ;
    PORT
      LAYER M3 ;
      RECT 94.815 146.827 94.833 146.881 ;
    END
  END r0_rd_out[219]
  PIN r0_rd_out[220]
    DIRECTION OUTPUT ;
    USE SIGNAL ;
    SHAPE ABUTMENT ;
    PORT
      LAYER M3 ;
      RECT 95.247 146.827 95.265 146.881 ;
    END
  END r0_rd_out[220]
  PIN r0_rd_out[221]
    DIRECTION OUTPUT ;
    USE SIGNAL ;
    SHAPE ABUTMENT ;
    PORT
      LAYER M3 ;
      RECT 95.679 146.827 95.697 146.881 ;
    END
  END r0_rd_out[221]
  PIN r0_rd_out[222]
    DIRECTION OUTPUT ;
    USE SIGNAL ;
    SHAPE ABUTMENT ;
    PORT
      LAYER M3 ;
      RECT 96.111 146.827 96.129 146.881 ;
    END
  END r0_rd_out[222]
  PIN r0_rd_out[223]
    DIRECTION OUTPUT ;
    USE SIGNAL ;
    SHAPE ABUTMENT ;
    PORT
      LAYER M3 ;
      RECT 96.543 146.827 96.561 146.881 ;
    END
  END r0_rd_out[223]
  PIN r0_rd_out[224]
    DIRECTION OUTPUT ;
    USE SIGNAL ;
    SHAPE ABUTMENT ;
    PORT
      LAYER M3 ;
      RECT 96.975 146.827 96.993 146.881 ;
    END
  END r0_rd_out[224]
  PIN r0_rd_out[225]
    DIRECTION OUTPUT ;
    USE SIGNAL ;
    SHAPE ABUTMENT ;
    PORT
      LAYER M3 ;
      RECT 97.407 146.827 97.425 146.881 ;
    END
  END r0_rd_out[225]
  PIN r0_rd_out[226]
    DIRECTION OUTPUT ;
    USE SIGNAL ;
    SHAPE ABUTMENT ;
    PORT
      LAYER M3 ;
      RECT 97.839 146.827 97.857 146.881 ;
    END
  END r0_rd_out[226]
  PIN r0_rd_out[227]
    DIRECTION OUTPUT ;
    USE SIGNAL ;
    SHAPE ABUTMENT ;
    PORT
      LAYER M3 ;
      RECT 98.271 146.827 98.289 146.881 ;
    END
  END r0_rd_out[227]
  PIN r0_rd_out[228]
    DIRECTION OUTPUT ;
    USE SIGNAL ;
    SHAPE ABUTMENT ;
    PORT
      LAYER M3 ;
      RECT 98.703 146.827 98.721 146.881 ;
    END
  END r0_rd_out[228]
  PIN r0_rd_out[229]
    DIRECTION OUTPUT ;
    USE SIGNAL ;
    SHAPE ABUTMENT ;
    PORT
      LAYER M3 ;
      RECT 99.135 146.827 99.153 146.881 ;
    END
  END r0_rd_out[229]
  PIN rw0_addr_in[0]
    DIRECTION INPUT ;
    USE SIGNAL ;
    SHAPE ABUTMENT ;
    PORT
      LAYER M4 ;
      RECT 0.000 128.340 0.072 128.364 ;
    END
  END rw0_addr_in[0]
  PIN rw0_addr_in[1]
    DIRECTION INPUT ;
    USE SIGNAL ;
    SHAPE ABUTMENT ;
    PORT
      LAYER M4 ;
      RECT 0.000 130.548 0.072 130.572 ;
    END
  END rw0_addr_in[1]
  PIN rw0_addr_in[2]
    DIRECTION INPUT ;
    USE SIGNAL ;
    SHAPE ABUTMENT ;
    PORT
      LAYER M4 ;
      RECT 0.000 132.756 0.072 132.780 ;
    END
  END rw0_addr_in[2]
  PIN rw0_addr_in[3]
    DIRECTION INPUT ;
    USE SIGNAL ;
    SHAPE ABUTMENT ;
    PORT
      LAYER M4 ;
      RECT 0.000 134.964 0.072 134.988 ;
    END
  END rw0_addr_in[3]
  PIN rw0_addr_in[4]
    DIRECTION INPUT ;
    USE SIGNAL ;
    SHAPE ABUTMENT ;
    PORT
      LAYER M4 ;
      RECT 105.499 126.132 105.571 126.156 ;
    END
  END rw0_addr_in[4]
  PIN rw0_addr_in[5]
    DIRECTION INPUT ;
    USE SIGNAL ;
    SHAPE ABUTMENT ;
    PORT
      LAYER M4 ;
      RECT 105.499 128.340 105.571 128.364 ;
    END
  END rw0_addr_in[5]
  PIN rw0_addr_in[6]
    DIRECTION INPUT ;
    USE SIGNAL ;
    SHAPE ABUTMENT ;
    PORT
      LAYER M4 ;
      RECT 105.499 130.548 105.571 130.572 ;
    END
  END rw0_addr_in[6]
  PIN r0_addr_in[0]
    DIRECTION INPUT ;
    USE SIGNAL ;
    SHAPE ABUTMENT ;
    PORT
      LAYER M4 ;
      RECT 0.000 137.172 0.072 137.196 ;
    END
  END r0_addr_in[0]
  PIN r0_addr_in[1]
    DIRECTION INPUT ;
    USE SIGNAL ;
    SHAPE ABUTMENT ;
    PORT
      LAYER M4 ;
      RECT 0.000 139.380 0.072 139.404 ;
    END
  END r0_addr_in[1]
  PIN r0_addr_in[2]
    DIRECTION INPUT ;
    USE SIGNAL ;
    SHAPE ABUTMENT ;
    PORT
      LAYER M4 ;
      RECT 0.000 141.588 0.072 141.612 ;
    END
  END r0_addr_in[2]
  PIN r0_addr_in[3]
    DIRECTION INPUT ;
    USE SIGNAL ;
    SHAPE ABUTMENT ;
    PORT
      LAYER M4 ;
      RECT 0.000 143.796 0.072 143.820 ;
    END
  END r0_addr_in[3]
  PIN r0_addr_in[4]
    DIRECTION INPUT ;
    USE SIGNAL ;
    SHAPE ABUTMENT ;
    PORT
      LAYER M4 ;
      RECT 105.499 132.756 105.571 132.780 ;
    END
  END r0_addr_in[4]
  PIN r0_addr_in[5]
    DIRECTION INPUT ;
    USE SIGNAL ;
    SHAPE ABUTMENT ;
    PORT
      LAYER M4 ;
      RECT 105.499 134.964 105.571 134.988 ;
    END
  END r0_addr_in[5]
  PIN r0_addr_in[6]
    DIRECTION INPUT ;
    USE SIGNAL ;
    SHAPE ABUTMENT ;
    PORT
      LAYER M4 ;
      RECT 105.499 137.172 105.571 137.196 ;
    END
  END r0_addr_in[6]
  PIN rw0_we_in
    DIRECTION INPUT ;
    USE SIGNAL ;
    SHAPE ABUTMENT ;
    PORT
      LAYER M3 ;
      RECT 99.567 146.827 99.585 146.881 ;
    END
  END rw0_we_in
  PIN rw0_ce_in
    DIRECTION INPUT ;
    USE SIGNAL ;
    SHAPE ABUTMENT ;
    PORT
      LAYER M3 ;
      RECT 99.999 146.827 100.017 146.881 ;
    END
  END rw0_ce_in
  PIN rw0_clk
    DIRECTION INPUT ;
    USE SIGNAL ;
    SHAPE ABUTMENT ;
    PORT
      LAYER M3 ;
      RECT 100.431 146.827 100.449 146.881 ;
    END
  END rw0_clk
  PIN r0_ce_in
    DIRECTION INPUT ;
    USE SIGNAL ;
    SHAPE ABUTMENT ;
    PORT
      LAYER M3 ;
      RECT 100.863 146.827 100.881 146.881 ;
    END
  END r0_ce_in
  PIN r0_clk
    DIRECTION INPUT ;
    USE SIGNAL ;
    SHAPE ABUTMENT ;
    PORT
      LAYER M3 ;
      RECT 101.295 146.827 101.313 146.881 ;
    END
  END r0_clk
  PIN VSS
    DIRECTION INOUT ;
    USE GROUND ;
    PORT
      LAYER M4 ;
      RECT 0.216 0.240 105.355 0.336 ;
      RECT 0.216 1.008 105.355 1.104 ;
      RECT 0.216 1.776 105.355 1.872 ;
      RECT 0.216 2.544 105.355 2.640 ;
      RECT 0.216 3.312 105.355 3.408 ;
      RECT 0.216 4.080 105.355 4.176 ;
      RECT 0.216 4.848 105.355 4.944 ;
      RECT 0.216 5.616 105.355 5.712 ;
      RECT 0.216 6.384 105.355 6.480 ;
      RECT 0.216 7.152 105.355 7.248 ;
      RECT 0.216 7.920 105.355 8.016 ;
      RECT 0.216 8.688 105.355 8.784 ;
      RECT 0.216 9.456 105.355 9.552 ;
      RECT 0.216 10.224 105.355 10.320 ;
      RECT 0.216 10.992 105.355 11.088 ;
      RECT 0.216 11.760 105.355 11.856 ;
      RECT 0.216 12.528 105.355 12.624 ;
      RECT 0.216 13.296 105.355 13.392 ;
      RECT 0.216 14.064 105.355 14.160 ;
      RECT 0.216 14.832 105.355 14.928 ;
      RECT 0.216 15.600 105.355 15.696 ;
      RECT 0.216 16.368 105.355 16.464 ;
      RECT 0.216 17.136 105.355 17.232 ;
      RECT 0.216 17.904 105.355 18.000 ;
      RECT 0.216 18.672 105.355 18.768 ;
      RECT 0.216 19.440 105.355 19.536 ;
      RECT 0.216 20.208 105.355 20.304 ;
      RECT 0.216 20.976 105.355 21.072 ;
      RECT 0.216 21.744 105.355 21.840 ;
      RECT 0.216 22.512 105.355 22.608 ;
      RECT 0.216 23.280 105.355 23.376 ;
      RECT 0.216 24.048 105.355 24.144 ;
      RECT 0.216 24.816 105.355 24.912 ;
      RECT 0.216 25.584 105.355 25.680 ;
      RECT 0.216 26.352 105.355 26.448 ;
      RECT 0.216 27.120 105.355 27.216 ;
      RECT 0.216 27.888 105.355 27.984 ;
      RECT 0.216 28.656 105.355 28.752 ;
      RECT 0.216 29.424 105.355 29.520 ;
      RECT 0.216 30.192 105.355 30.288 ;
      RECT 0.216 30.960 105.355 31.056 ;
      RECT 0.216 31.728 105.355 31.824 ;
      RECT 0.216 32.496 105.355 32.592 ;
      RECT 0.216 33.264 105.355 33.360 ;
      RECT 0.216 34.032 105.355 34.128 ;
      RECT 0.216 34.800 105.355 34.896 ;
      RECT 0.216 35.568 105.355 35.664 ;
      RECT 0.216 36.336 105.355 36.432 ;
      RECT 0.216 37.104 105.355 37.200 ;
      RECT 0.216 37.872 105.355 37.968 ;
      RECT 0.216 38.640 105.355 38.736 ;
      RECT 0.216 39.408 105.355 39.504 ;
      RECT 0.216 40.176 105.355 40.272 ;
      RECT 0.216 40.944 105.355 41.040 ;
      RECT 0.216 41.712 105.355 41.808 ;
      RECT 0.216 42.480 105.355 42.576 ;
      RECT 0.216 43.248 105.355 43.344 ;
      RECT 0.216 44.016 105.355 44.112 ;
      RECT 0.216 44.784 105.355 44.880 ;
      RECT 0.216 45.552 105.355 45.648 ;
      RECT 0.216 46.320 105.355 46.416 ;
      RECT 0.216 47.088 105.355 47.184 ;
      RECT 0.216 47.856 105.355 47.952 ;
      RECT 0.216 48.624 105.355 48.720 ;
      RECT 0.216 49.392 105.355 49.488 ;
      RECT 0.216 50.160 105.355 50.256 ;
      RECT 0.216 50.928 105.355 51.024 ;
      RECT 0.216 51.696 105.355 51.792 ;
      RECT 0.216 52.464 105.355 52.560 ;
      RECT 0.216 53.232 105.355 53.328 ;
      RECT 0.216 54.000 105.355 54.096 ;
      RECT 0.216 54.768 105.355 54.864 ;
      RECT 0.216 55.536 105.355 55.632 ;
      RECT 0.216 56.304 105.355 56.400 ;
      RECT 0.216 57.072 105.355 57.168 ;
      RECT 0.216 57.840 105.355 57.936 ;
      RECT 0.216 58.608 105.355 58.704 ;
      RECT 0.216 59.376 105.355 59.472 ;
      RECT 0.216 60.144 105.355 60.240 ;
      RECT 0.216 60.912 105.355 61.008 ;
      RECT 0.216 61.680 105.355 61.776 ;
      RECT 0.216 62.448 105.355 62.544 ;
      RECT 0.216 63.216 105.355 63.312 ;
      RECT 0.216 63.984 105.355 64.080 ;
      RECT 0.216 64.752 105.355 64.848 ;
      RECT 0.216 65.520 105.355 65.616 ;
      RECT 0.216 66.288 105.355 66.384 ;
      RECT 0.216 67.056 105.355 67.152 ;
      RECT 0.216 67.824 105.355 67.920 ;
      RECT 0.216 68.592 105.355 68.688 ;
      RECT 0.216 69.360 105.355 69.456 ;
      RECT 0.216 70.128 105.355 70.224 ;
      RECT 0.216 70.896 105.355 70.992 ;
      RECT 0.216 71.664 105.355 71.760 ;
      RECT 0.216 72.432 105.355 72.528 ;
      RECT 0.216 73.200 105.355 73.296 ;
      RECT 0.216 73.968 105.355 74.064 ;
      RECT 0.216 74.736 105.355 74.832 ;
      RECT 0.216 75.504 105.355 75.600 ;
      RECT 0.216 76.272 105.355 76.368 ;
      RECT 0.216 77.040 105.355 77.136 ;
      RECT 0.216 77.808 105.355 77.904 ;
      RECT 0.216 78.576 105.355 78.672 ;
      RECT 0.216 79.344 105.355 79.440 ;
      RECT 0.216 80.112 105.355 80.208 ;
      RECT 0.216 80.880 105.355 80.976 ;
      RECT 0.216 81.648 105.355 81.744 ;
      RECT 0.216 82.416 105.355 82.512 ;
      RECT 0.216 83.184 105.355 83.280 ;
      RECT 0.216 83.952 105.355 84.048 ;
      RECT 0.216 84.720 105.355 84.816 ;
      RECT 0.216 85.488 105.355 85.584 ;
      RECT 0.216 86.256 105.355 86.352 ;
      RECT 0.216 87.024 105.355 87.120 ;
      RECT 0.216 87.792 105.355 87.888 ;
      RECT 0.216 88.560 105.355 88.656 ;
      RECT 0.216 89.328 105.355 89.424 ;
      RECT 0.216 90.096 105.355 90.192 ;
      RECT 0.216 90.864 105.355 90.960 ;
      RECT 0.216 91.632 105.355 91.728 ;
      RECT 0.216 92.400 105.355 92.496 ;
      RECT 0.216 93.168 105.355 93.264 ;
      RECT 0.216 93.936 105.355 94.032 ;
      RECT 0.216 94.704 105.355 94.800 ;
      RECT 0.216 95.472 105.355 95.568 ;
      RECT 0.216 96.240 105.355 96.336 ;
      RECT 0.216 97.008 105.355 97.104 ;
      RECT 0.216 97.776 105.355 97.872 ;
      RECT 0.216 98.544 105.355 98.640 ;
      RECT 0.216 99.312 105.355 99.408 ;
      RECT 0.216 100.080 105.355 100.176 ;
      RECT 0.216 100.848 105.355 100.944 ;
      RECT 0.216 101.616 105.355 101.712 ;
      RECT 0.216 102.384 105.355 102.480 ;
      RECT 0.216 103.152 105.355 103.248 ;
      RECT 0.216 103.920 105.355 104.016 ;
      RECT 0.216 104.688 105.355 104.784 ;
      RECT 0.216 105.456 105.355 105.552 ;
      RECT 0.216 106.224 105.355 106.320 ;
      RECT 0.216 106.992 105.355 107.088 ;
      RECT 0.216 107.760 105.355 107.856 ;
      RECT 0.216 108.528 105.355 108.624 ;
      RECT 0.216 109.296 105.355 109.392 ;
      RECT 0.216 110.064 105.355 110.160 ;
      RECT 0.216 110.832 105.355 110.928 ;
      RECT 0.216 111.600 105.355 111.696 ;
      RECT 0.216 112.368 105.355 112.464 ;
      RECT 0.216 113.136 105.355 113.232 ;
      RECT 0.216 113.904 105.355 114.000 ;
      RECT 0.216 114.672 105.355 114.768 ;
      RECT 0.216 115.440 105.355 115.536 ;
      RECT 0.216 116.208 105.355 116.304 ;
      RECT 0.216 116.976 105.355 117.072 ;
      RECT 0.216 117.744 105.355 117.840 ;
      RECT 0.216 118.512 105.355 118.608 ;
      RECT 0.216 119.280 105.355 119.376 ;
      RECT 0.216 120.048 105.355 120.144 ;
      RECT 0.216 120.816 105.355 120.912 ;
      RECT 0.216 121.584 105.355 121.680 ;
      RECT 0.216 122.352 105.355 122.448 ;
      RECT 0.216 123.120 105.355 123.216 ;
      RECT 0.216 123.888 105.355 123.984 ;
      RECT 0.216 124.656 105.355 124.752 ;
      RECT 0.216 125.424 105.355 125.520 ;
      RECT 0.216 126.192 105.355 126.288 ;
      RECT 0.216 126.960 105.355 127.056 ;
      RECT 0.216 127.728 105.355 127.824 ;
      RECT 0.216 128.496 105.355 128.592 ;
      RECT 0.216 129.264 105.355 129.360 ;
      RECT 0.216 130.032 105.355 130.128 ;
      RECT 0.216 130.800 105.355 130.896 ;
      RECT 0.216 131.568 105.355 131.664 ;
      RECT 0.216 132.336 105.355 132.432 ;
      RECT 0.216 133.104 105.355 133.200 ;
      RECT 0.216 133.872 105.355 133.968 ;
      RECT 0.216 134.640 105.355 134.736 ;
      RECT 0.216 135.408 105.355 135.504 ;
      RECT 0.216 136.176 105.355 136.272 ;
      RECT 0.216 136.944 105.355 137.040 ;
      RECT 0.216 137.712 105.355 137.808 ;
      RECT 0.216 138.480 105.355 138.576 ;
      RECT 0.216 139.248 105.355 139.344 ;
      RECT 0.216 140.016 105.355 140.112 ;
      RECT 0.216 140.784 105.355 140.880 ;
      RECT 0.216 141.552 105.355 141.648 ;
      RECT 0.216 142.320 105.355 142.416 ;
      RECT 0.216 143.088 105.355 143.184 ;
      RECT 0.216 143.856 105.355 143.952 ;
      RECT 0.216 144.624 105.355 144.720 ;
      RECT 0.216 145.392 105.355 145.488 ;
      RECT 0.216 146.160 105.355 146.256 ;
    END
  END VSS
  PIN VDD
    DIRECTION INOUT ;
    USE POWER ;
    PORT
      LAYER M4 ;
      RECT 0.216 0.624 105.355 0.720 ;
      RECT 0.216 1.392 105.355 1.488 ;
      RECT 0.216 2.160 105.355 2.256 ;
      RECT 0.216 2.928 105.355 3.024 ;
      RECT 0.216 3.696 105.355 3.792 ;
      RECT 0.216 4.464 105.355 4.560 ;
      RECT 0.216 5.232 105.355 5.328 ;
      RECT 0.216 6.000 105.355 6.096 ;
      RECT 0.216 6.768 105.355 6.864 ;
      RECT 0.216 7.536 105.355 7.632 ;
      RECT 0.216 8.304 105.355 8.400 ;
      RECT 0.216 9.072 105.355 9.168 ;
      RECT 0.216 9.840 105.355 9.936 ;
      RECT 0.216 10.608 105.355 10.704 ;
      RECT 0.216 11.376 105.355 11.472 ;
      RECT 0.216 12.144 105.355 12.240 ;
      RECT 0.216 12.912 105.355 13.008 ;
      RECT 0.216 13.680 105.355 13.776 ;
      RECT 0.216 14.448 105.355 14.544 ;
      RECT 0.216 15.216 105.355 15.312 ;
      RECT 0.216 15.984 105.355 16.080 ;
      RECT 0.216 16.752 105.355 16.848 ;
      RECT 0.216 17.520 105.355 17.616 ;
      RECT 0.216 18.288 105.355 18.384 ;
      RECT 0.216 19.056 105.355 19.152 ;
      RECT 0.216 19.824 105.355 19.920 ;
      RECT 0.216 20.592 105.355 20.688 ;
      RECT 0.216 21.360 105.355 21.456 ;
      RECT 0.216 22.128 105.355 22.224 ;
      RECT 0.216 22.896 105.355 22.992 ;
      RECT 0.216 23.664 105.355 23.760 ;
      RECT 0.216 24.432 105.355 24.528 ;
      RECT 0.216 25.200 105.355 25.296 ;
      RECT 0.216 25.968 105.355 26.064 ;
      RECT 0.216 26.736 105.355 26.832 ;
      RECT 0.216 27.504 105.355 27.600 ;
      RECT 0.216 28.272 105.355 28.368 ;
      RECT 0.216 29.040 105.355 29.136 ;
      RECT 0.216 29.808 105.355 29.904 ;
      RECT 0.216 30.576 105.355 30.672 ;
      RECT 0.216 31.344 105.355 31.440 ;
      RECT 0.216 32.112 105.355 32.208 ;
      RECT 0.216 32.880 105.355 32.976 ;
      RECT 0.216 33.648 105.355 33.744 ;
      RECT 0.216 34.416 105.355 34.512 ;
      RECT 0.216 35.184 105.355 35.280 ;
      RECT 0.216 35.952 105.355 36.048 ;
      RECT 0.216 36.720 105.355 36.816 ;
      RECT 0.216 37.488 105.355 37.584 ;
      RECT 0.216 38.256 105.355 38.352 ;
      RECT 0.216 39.024 105.355 39.120 ;
      RECT 0.216 39.792 105.355 39.888 ;
      RECT 0.216 40.560 105.355 40.656 ;
      RECT 0.216 41.328 105.355 41.424 ;
      RECT 0.216 42.096 105.355 42.192 ;
      RECT 0.216 42.864 105.355 42.960 ;
      RECT 0.216 43.632 105.355 43.728 ;
      RECT 0.216 44.400 105.355 44.496 ;
      RECT 0.216 45.168 105.355 45.264 ;
      RECT 0.216 45.936 105.355 46.032 ;
      RECT 0.216 46.704 105.355 46.800 ;
      RECT 0.216 47.472 105.355 47.568 ;
      RECT 0.216 48.240 105.355 48.336 ;
      RECT 0.216 49.008 105.355 49.104 ;
      RECT 0.216 49.776 105.355 49.872 ;
      RECT 0.216 50.544 105.355 50.640 ;
      RECT 0.216 51.312 105.355 51.408 ;
      RECT 0.216 52.080 105.355 52.176 ;
      RECT 0.216 52.848 105.355 52.944 ;
      RECT 0.216 53.616 105.355 53.712 ;
      RECT 0.216 54.384 105.355 54.480 ;
      RECT 0.216 55.152 105.355 55.248 ;
      RECT 0.216 55.920 105.355 56.016 ;
      RECT 0.216 56.688 105.355 56.784 ;
      RECT 0.216 57.456 105.355 57.552 ;
      RECT 0.216 58.224 105.355 58.320 ;
      RECT 0.216 58.992 105.355 59.088 ;
      RECT 0.216 59.760 105.355 59.856 ;
      RECT 0.216 60.528 105.355 60.624 ;
      RECT 0.216 61.296 105.355 61.392 ;
      RECT 0.216 62.064 105.355 62.160 ;
      RECT 0.216 62.832 105.355 62.928 ;
      RECT 0.216 63.600 105.355 63.696 ;
      RECT 0.216 64.368 105.355 64.464 ;
      RECT 0.216 65.136 105.355 65.232 ;
      RECT 0.216 65.904 105.355 66.000 ;
      RECT 0.216 66.672 105.355 66.768 ;
      RECT 0.216 67.440 105.355 67.536 ;
      RECT 0.216 68.208 105.355 68.304 ;
      RECT 0.216 68.976 105.355 69.072 ;
      RECT 0.216 69.744 105.355 69.840 ;
      RECT 0.216 70.512 105.355 70.608 ;
      RECT 0.216 71.280 105.355 71.376 ;
      RECT 0.216 72.048 105.355 72.144 ;
      RECT 0.216 72.816 105.355 72.912 ;
      RECT 0.216 73.584 105.355 73.680 ;
      RECT 0.216 74.352 105.355 74.448 ;
      RECT 0.216 75.120 105.355 75.216 ;
      RECT 0.216 75.888 105.355 75.984 ;
      RECT 0.216 76.656 105.355 76.752 ;
      RECT 0.216 77.424 105.355 77.520 ;
      RECT 0.216 78.192 105.355 78.288 ;
      RECT 0.216 78.960 105.355 79.056 ;
      RECT 0.216 79.728 105.355 79.824 ;
      RECT 0.216 80.496 105.355 80.592 ;
      RECT 0.216 81.264 105.355 81.360 ;
      RECT 0.216 82.032 105.355 82.128 ;
      RECT 0.216 82.800 105.355 82.896 ;
      RECT 0.216 83.568 105.355 83.664 ;
      RECT 0.216 84.336 105.355 84.432 ;
      RECT 0.216 85.104 105.355 85.200 ;
      RECT 0.216 85.872 105.355 85.968 ;
      RECT 0.216 86.640 105.355 86.736 ;
      RECT 0.216 87.408 105.355 87.504 ;
      RECT 0.216 88.176 105.355 88.272 ;
      RECT 0.216 88.944 105.355 89.040 ;
      RECT 0.216 89.712 105.355 89.808 ;
      RECT 0.216 90.480 105.355 90.576 ;
      RECT 0.216 91.248 105.355 91.344 ;
      RECT 0.216 92.016 105.355 92.112 ;
      RECT 0.216 92.784 105.355 92.880 ;
      RECT 0.216 93.552 105.355 93.648 ;
      RECT 0.216 94.320 105.355 94.416 ;
      RECT 0.216 95.088 105.355 95.184 ;
      RECT 0.216 95.856 105.355 95.952 ;
      RECT 0.216 96.624 105.355 96.720 ;
      RECT 0.216 97.392 105.355 97.488 ;
      RECT 0.216 98.160 105.355 98.256 ;
      RECT 0.216 98.928 105.355 99.024 ;
      RECT 0.216 99.696 105.355 99.792 ;
      RECT 0.216 100.464 105.355 100.560 ;
      RECT 0.216 101.232 105.355 101.328 ;
      RECT 0.216 102.000 105.355 102.096 ;
      RECT 0.216 102.768 105.355 102.864 ;
      RECT 0.216 103.536 105.355 103.632 ;
      RECT 0.216 104.304 105.355 104.400 ;
      RECT 0.216 105.072 105.355 105.168 ;
      RECT 0.216 105.840 105.355 105.936 ;
      RECT 0.216 106.608 105.355 106.704 ;
      RECT 0.216 107.376 105.355 107.472 ;
      RECT 0.216 108.144 105.355 108.240 ;
      RECT 0.216 108.912 105.355 109.008 ;
      RECT 0.216 109.680 105.355 109.776 ;
      RECT 0.216 110.448 105.355 110.544 ;
      RECT 0.216 111.216 105.355 111.312 ;
      RECT 0.216 111.984 105.355 112.080 ;
      RECT 0.216 112.752 105.355 112.848 ;
      RECT 0.216 113.520 105.355 113.616 ;
      RECT 0.216 114.288 105.355 114.384 ;
      RECT 0.216 115.056 105.355 115.152 ;
      RECT 0.216 115.824 105.355 115.920 ;
      RECT 0.216 116.592 105.355 116.688 ;
      RECT 0.216 117.360 105.355 117.456 ;
      RECT 0.216 118.128 105.355 118.224 ;
      RECT 0.216 118.896 105.355 118.992 ;
      RECT 0.216 119.664 105.355 119.760 ;
      RECT 0.216 120.432 105.355 120.528 ;
      RECT 0.216 121.200 105.355 121.296 ;
      RECT 0.216 121.968 105.355 122.064 ;
      RECT 0.216 122.736 105.355 122.832 ;
      RECT 0.216 123.504 105.355 123.600 ;
      RECT 0.216 124.272 105.355 124.368 ;
      RECT 0.216 125.040 105.355 125.136 ;
      RECT 0.216 125.808 105.355 125.904 ;
      RECT 0.216 126.576 105.355 126.672 ;
      RECT 0.216 127.344 105.355 127.440 ;
      RECT 0.216 128.112 105.355 128.208 ;
      RECT 0.216 128.880 105.355 128.976 ;
      RECT 0.216 129.648 105.355 129.744 ;
      RECT 0.216 130.416 105.355 130.512 ;
      RECT 0.216 131.184 105.355 131.280 ;
      RECT 0.216 131.952 105.355 132.048 ;
      RECT 0.216 132.720 105.355 132.816 ;
      RECT 0.216 133.488 105.355 133.584 ;
      RECT 0.216 134.256 105.355 134.352 ;
      RECT 0.216 135.024 105.355 135.120 ;
      RECT 0.216 135.792 105.355 135.888 ;
      RECT 0.216 136.560 105.355 136.656 ;
      RECT 0.216 137.328 105.355 137.424 ;
      RECT 0.216 138.096 105.355 138.192 ;
      RECT 0.216 138.864 105.355 138.960 ;
      RECT 0.216 139.632 105.355 139.728 ;
      RECT 0.216 140.400 105.355 140.496 ;
      RECT 0.216 141.168 105.355 141.264 ;
      RECT 0.216 141.936 105.355 142.032 ;
      RECT 0.216 142.704 105.355 142.800 ;
      RECT 0.216 143.472 105.355 143.568 ;
      RECT 0.216 144.240 105.355 144.336 ;
      RECT 0.216 145.008 105.355 145.104 ;
      RECT 0.216 145.776 105.355 145.872 ;
      RECT 0.216 146.544 105.355 146.640 ;
    END
  END VDD
  OBS
    LAYER M1 ;
    RECT 0 0 105.571 146.881 ;
    LAYER M2 ;
    RECT 0 0 105.571 146.881 ;
    LAYER M3 ;
    RECT 0 0 105.571 146.881 ;
    LAYER M4 ;
    RECT 0 0 105.571 146.881 ;
  END
END fakeram_1rw1r_230w128d_sram

END LIBRARY
